VERSION 5.8 ;
BUSBITCHARS "[]" ;
DIVIDERCHAR "/" ;
UNITS
    DATABASE MICRONS 1000 ;
END UNITS

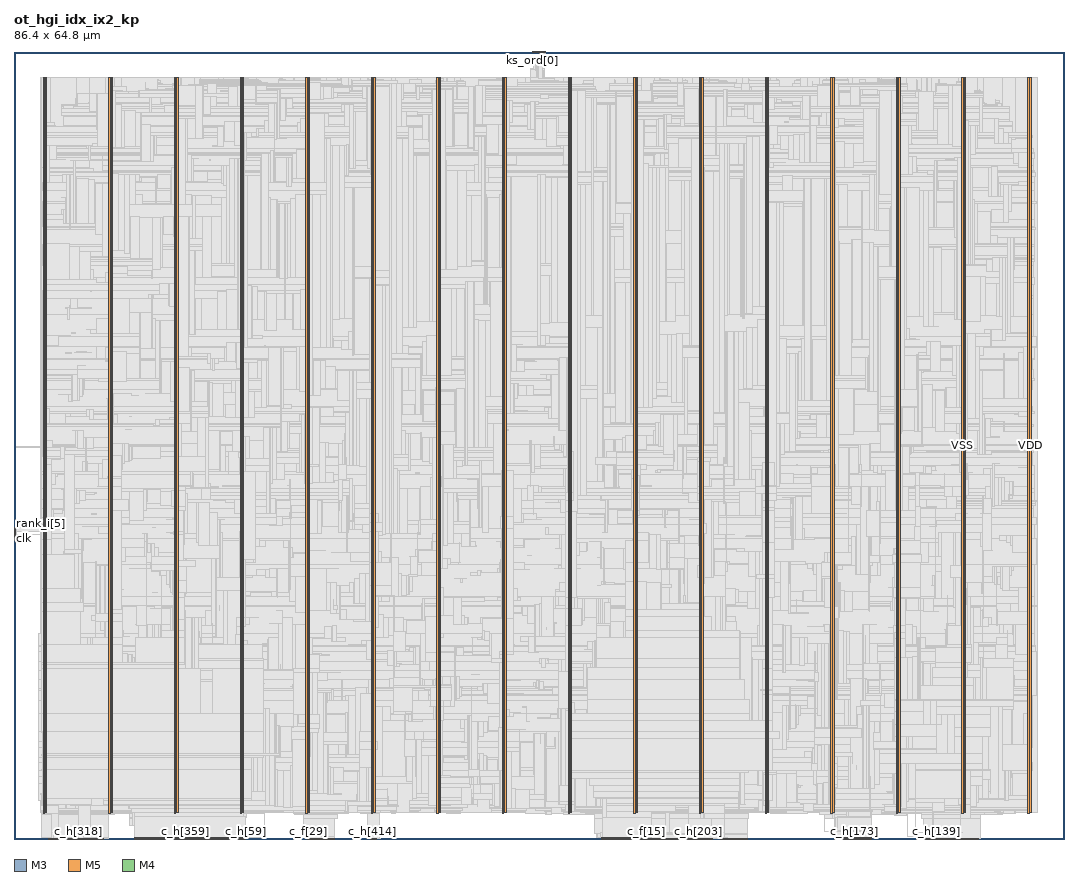
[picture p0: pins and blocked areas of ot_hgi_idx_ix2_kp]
MACRO ot_hgi_idx_ix2_kp
  FOREIGN ot_hgi_idx_ix2_kp 0 0 ;
  CLASS BLOCK ;
  SIZE 86.4 BY 64.8 ;
  PIN c_cr[0]
    DIRECTION OUTPUT ;
    USE SIGNAL ;
    PORT
      LAYER M3 ;
        RECT  50.652 0 50.67 0.037 ;
    END
  END c_cr[0]
  PIN c_cr[1]
    DIRECTION OUTPUT ;
    USE SIGNAL ;
    PORT
      LAYER M3 ;
        RECT  50.724 0 50.742 0.037 ;
    END
  END c_cr[1]
  PIN c_cr[2]
    DIRECTION OUTPUT ;
    USE SIGNAL ;
    PORT
      LAYER M3 ;
        RECT  50.796 0 50.814 0.037 ;
    END
  END c_cr[2]
  PIN c_cr[3]
    DIRECTION OUTPUT ;
    USE SIGNAL ;
    PORT
      LAYER M3 ;
        RECT  50.868 0 50.886 0.037 ;
    END
  END c_cr[3]
  PIN c_f[0]
    DIRECTION INPUT ;
    USE SIGNAL ;
    PORT
      LAYER M3 ;
        RECT  50.94 0 50.958 0.037 ;
    END
  END c_f[0]
  PIN c_f[10]
    DIRECTION INPUT ;
    USE SIGNAL ;
    PORT
      LAYER M3 ;
        RECT  51.66 0 51.678 0.037 ;
    END
  END c_f[10]
  PIN c_f[11]
    DIRECTION INPUT ;
    USE SIGNAL ;
    PORT
      LAYER M3 ;
        RECT  51.732 0 51.75 0.037 ;
    END
  END c_f[11]
  PIN c_f[12]
    DIRECTION INPUT ;
    USE SIGNAL ;
    PORT
      LAYER M3 ;
        RECT  51.804 0 51.822 0.037 ;
    END
  END c_f[12]
  PIN c_f[13]
    DIRECTION INPUT ;
    USE SIGNAL ;
    PORT
      LAYER M3 ;
        RECT  51.876 0 51.894 0.037 ;
    END
  END c_f[13]
  PIN c_f[14]
    DIRECTION INPUT ;
    USE SIGNAL ;
    PORT
      LAYER M3 ;
        RECT  51.948 0 51.966 0.037 ;
    END
  END c_f[14]
  PIN c_f[15]
    DIRECTION INPUT ;
    USE SIGNAL ;
    PORT
      LAYER M3 ;
        RECT  52.02 0 52.038 0.037 ;
    END
  END c_f[15]
  PIN c_f[16]
    DIRECTION INPUT ;
    USE SIGNAL ;
    PORT
      LAYER M3 ;
        RECT  52.092 0 52.11 0.037 ;
    END
  END c_f[16]
  PIN c_f[17]
    DIRECTION INPUT ;
    USE SIGNAL ;
    PORT
      LAYER M3 ;
        RECT  52.164 0 52.182 0.037 ;
    END
  END c_f[17]
  PIN c_f[18]
    DIRECTION INPUT ;
    USE SIGNAL ;
    PORT
      LAYER M3 ;
        RECT  52.236 0 52.254 0.037 ;
    END
  END c_f[18]
  PIN c_f[19]
    DIRECTION INPUT ;
    USE SIGNAL ;
    PORT
      LAYER M3 ;
        RECT  52.308 0 52.326 0.037 ;
    END
  END c_f[19]
  PIN c_f[1]
    DIRECTION INPUT ;
    USE SIGNAL ;
    PORT
      LAYER M3 ;
        RECT  51.012 0 51.03 0.037 ;
    END
  END c_f[1]
  PIN c_f[20]
    DIRECTION INPUT ;
    USE SIGNAL ;
    PORT
      LAYER M3 ;
        RECT  52.38 0 52.398 0.037 ;
    END
  END c_f[20]
  PIN c_f[21]
    DIRECTION INPUT ;
    USE SIGNAL ;
    PORT
      LAYER M3 ;
        RECT  52.452 0 52.47 0.037 ;
    END
  END c_f[21]
  PIN c_f[22]
    DIRECTION INPUT ;
    USE SIGNAL ;
    PORT
      LAYER M3 ;
        RECT  52.524 0 52.542 0.037 ;
    END
  END c_f[22]
  PIN c_f[23]
    DIRECTION INPUT ;
    USE SIGNAL ;
    PORT
      LAYER M3 ;
        RECT  52.596 0 52.614 0.037 ;
    END
  END c_f[23]
  PIN c_f[24]
    DIRECTION INPUT ;
    USE SIGNAL ;
    PORT
      LAYER M3 ;
        RECT  52.668 0 52.686 0.037 ;
    END
  END c_f[24]
  PIN c_f[25]
    DIRECTION INPUT ;
    USE SIGNAL ;
    PORT
      LAYER M3 ;
        RECT  52.74 0 52.758 0.037 ;
    END
  END c_f[25]
  PIN c_f[26]
    DIRECTION INPUT ;
    USE SIGNAL ;
    PORT
      LAYER M3 ;
        RECT  52.812 0 52.83 0.037 ;
    END
  END c_f[26]
  PIN c_f[27]
    DIRECTION INPUT ;
    USE SIGNAL ;
    PORT
      LAYER M3 ;
        RECT  52.884 0 52.902 0.037 ;
    END
  END c_f[27]
  PIN c_f[28]
    DIRECTION INPUT ;
    USE SIGNAL ;
    PORT
      LAYER M3 ;
        RECT  24.156 0 24.174 0.037 ;
    END
  END c_f[28]
  PIN c_f[29]
    DIRECTION INPUT ;
    USE SIGNAL ;
    PORT
      LAYER M3 ;
        RECT  24.228 0 24.246 0.037 ;
    END
  END c_f[29]
  PIN c_f[2]
    DIRECTION INPUT ;
    USE SIGNAL ;
    PORT
      LAYER M3 ;
        RECT  51.084 0 51.102 0.037 ;
    END
  END c_f[2]
  PIN c_f[30]
    DIRECTION INPUT ;
    USE SIGNAL ;
    PORT
      LAYER M3 ;
        RECT  24.3 0 24.318 0.037 ;
    END
  END c_f[30]
  PIN c_f[31]
    DIRECTION INPUT ;
    USE SIGNAL ;
    PORT
      LAYER M3 ;
        RECT  24.372 0 24.39 0.037 ;
    END
  END c_f[31]
  PIN c_f[3]
    DIRECTION INPUT ;
    USE SIGNAL ;
    PORT
      LAYER M3 ;
        RECT  51.156 0 51.174 0.037 ;
    END
  END c_f[3]
  PIN c_f[4]
    DIRECTION INPUT ;
    USE SIGNAL ;
    PORT
      LAYER M3 ;
        RECT  51.228 0 51.246 0.037 ;
    END
  END c_f[4]
  PIN c_f[5]
    DIRECTION INPUT ;
    USE SIGNAL ;
    PORT
      LAYER M3 ;
        RECT  51.3 0 51.318 0.037 ;
    END
  END c_f[5]
  PIN c_f[6]
    DIRECTION INPUT ;
    USE SIGNAL ;
    PORT
      LAYER M3 ;
        RECT  51.372 0 51.39 0.037 ;
    END
  END c_f[6]
  PIN c_f[7]
    DIRECTION INPUT ;
    USE SIGNAL ;
    PORT
      LAYER M3 ;
        RECT  51.444 0 51.462 0.037 ;
    END
  END c_f[7]
  PIN c_f[8]
    DIRECTION INPUT ;
    USE SIGNAL ;
    PORT
      LAYER M3 ;
        RECT  51.516 0 51.534 0.037 ;
    END
  END c_f[8]
  PIN c_f[9]
    DIRECTION INPUT ;
    USE SIGNAL ;
    PORT
      LAYER M3 ;
        RECT  51.588 0 51.606 0.037 ;
    END
  END c_f[9]
  PIN c_h[0]
    DIRECTION INPUT ;
    USE SIGNAL ;
    PORT
      LAYER M3 ;
        RECT  24.444 0 24.462 0.037 ;
    END
  END c_h[0]
  PIN c_h[100]
    DIRECTION INPUT ;
    USE SIGNAL ;
    PORT
      LAYER M3 ;
        RECT  53.532 0 53.55 0.037 ;
    END
  END c_h[100]
  PIN c_h[101]
    DIRECTION INPUT ;
    USE SIGNAL ;
    PORT
      LAYER M3 ;
        RECT  53.604 0 53.622 0.037 ;
    END
  END c_h[101]
  PIN c_h[102]
    DIRECTION INPUT ;
    USE SIGNAL ;
    PORT
      LAYER M3 ;
        RECT  53.676 0 53.694 0.037 ;
    END
  END c_h[102]
  PIN c_h[103]
    DIRECTION INPUT ;
    USE SIGNAL ;
    PORT
      LAYER M3 ;
        RECT  53.748 0 53.766 0.037 ;
    END
  END c_h[103]
  PIN c_h[104]
    DIRECTION INPUT ;
    USE SIGNAL ;
    PORT
      LAYER M3 ;
        RECT  53.82 0 53.838 0.037 ;
    END
  END c_h[104]
  PIN c_h[105]
    DIRECTION INPUT ;
    USE SIGNAL ;
    PORT
      LAYER M3 ;
        RECT  53.892 0 53.91 0.037 ;
    END
  END c_h[105]
  PIN c_h[106]
    DIRECTION INPUT ;
    USE SIGNAL ;
    PORT
      LAYER M3 ;
        RECT  53.964 0 53.982 0.037 ;
    END
  END c_h[106]
  PIN c_h[107]
    DIRECTION INPUT ;
    USE SIGNAL ;
    PORT
      LAYER M3 ;
        RECT  54.036 0 54.054 0.037 ;
    END
  END c_h[107]
  PIN c_h[108]
    DIRECTION INPUT ;
    USE SIGNAL ;
    PORT
      LAYER M3 ;
        RECT  54.108 0 54.126 0.037 ;
    END
  END c_h[108]
  PIN c_h[109]
    DIRECTION INPUT ;
    USE SIGNAL ;
    PORT
      LAYER M3 ;
        RECT  54.18 0 54.198 0.037 ;
    END
  END c_h[109]
  PIN c_h[10]
    DIRECTION INPUT ;
    USE SIGNAL ;
    PORT
      LAYER M3 ;
        RECT  25.164 0 25.182 0.037 ;
    END
  END c_h[10]
  PIN c_h[110]
    DIRECTION INPUT ;
    USE SIGNAL ;
    PORT
      LAYER M3 ;
        RECT  54.252 0 54.27 0.037 ;
    END
  END c_h[110]
  PIN c_h[111]
    DIRECTION INPUT ;
    USE SIGNAL ;
    PORT
      LAYER M3 ;
        RECT  54.324 0 54.342 0.037 ;
    END
  END c_h[111]
  PIN c_h[112]
    DIRECTION INPUT ;
    USE SIGNAL ;
    PORT
      LAYER M3 ;
        RECT  54.396 0 54.414 0.037 ;
    END
  END c_h[112]
  PIN c_h[113]
    DIRECTION INPUT ;
    USE SIGNAL ;
    PORT
      LAYER M3 ;
        RECT  54.468 0 54.486 0.037 ;
    END
  END c_h[113]
  PIN c_h[114]
    DIRECTION INPUT ;
    USE SIGNAL ;
    PORT
      LAYER M3 ;
        RECT  54.54 0 54.558 0.037 ;
    END
  END c_h[114]
  PIN c_h[115]
    DIRECTION INPUT ;
    USE SIGNAL ;
    PORT
      LAYER M3 ;
        RECT  54.612 0 54.63 0.037 ;
    END
  END c_h[115]
  PIN c_h[116]
    DIRECTION INPUT ;
    USE SIGNAL ;
    PORT
      LAYER M3 ;
        RECT  54.684 0 54.702 0.037 ;
    END
  END c_h[116]
  PIN c_h[117]
    DIRECTION INPUT ;
    USE SIGNAL ;
    PORT
      LAYER M3 ;
        RECT  54.756 0 54.774 0.037 ;
    END
  END c_h[117]
  PIN c_h[118]
    DIRECTION INPUT ;
    USE SIGNAL ;
    PORT
      LAYER M3 ;
        RECT  54.828 0 54.846 0.037 ;
    END
  END c_h[118]
  PIN c_h[119]
    DIRECTION INPUT ;
    USE SIGNAL ;
    PORT
      LAYER M3 ;
        RECT  54.9 0 54.918 0.037 ;
    END
  END c_h[119]
  PIN c_h[11]
    DIRECTION INPUT ;
    USE SIGNAL ;
    PORT
      LAYER M3 ;
        RECT  25.236 0 25.254 0.037 ;
    END
  END c_h[11]
  PIN c_h[120]
    DIRECTION INPUT ;
    USE SIGNAL ;
    PORT
      LAYER M3 ;
        RECT  54.972 0 54.99 0.037 ;
    END
  END c_h[120]
  PIN c_h[121]
    DIRECTION INPUT ;
    USE SIGNAL ;
    PORT
      LAYER M3 ;
        RECT  55.044 0 55.062 0.037 ;
    END
  END c_h[121]
  PIN c_h[122]
    DIRECTION INPUT ;
    USE SIGNAL ;
    PORT
      LAYER M3 ;
        RECT  55.116 0 55.134 0.037 ;
    END
  END c_h[122]
  PIN c_h[123]
    DIRECTION INPUT ;
    USE SIGNAL ;
    PORT
      LAYER M3 ;
        RECT  55.188 0 55.206 0.037 ;
    END
  END c_h[123]
  PIN c_h[124]
    DIRECTION INPUT ;
    USE SIGNAL ;
    PORT
      LAYER M3 ;
        RECT  74.844 0 74.862 0.037 ;
    END
  END c_h[124]
  PIN c_h[125]
    DIRECTION INPUT ;
    USE SIGNAL ;
    PORT
      LAYER M3 ;
        RECT  74.916 0 74.934 0.037 ;
    END
  END c_h[125]
  PIN c_h[126]
    DIRECTION INPUT ;
    USE SIGNAL ;
    PORT
      LAYER M3 ;
        RECT  74.988 0 75.006 0.037 ;
    END
  END c_h[126]
  PIN c_h[127]
    DIRECTION INPUT ;
    USE SIGNAL ;
    PORT
      LAYER M3 ;
        RECT  75.06 0 75.078 0.037 ;
    END
  END c_h[127]
  PIN c_h[128]
    DIRECTION INPUT ;
    USE SIGNAL ;
    PORT
      LAYER M3 ;
        RECT  75.132 0 75.15 0.037 ;
    END
  END c_h[128]
  PIN c_h[129]
    DIRECTION INPUT ;
    USE SIGNAL ;
    PORT
      LAYER M3 ;
        RECT  75.204 0 75.222 0.037 ;
    END
  END c_h[129]
  PIN c_h[12]
    DIRECTION INPUT ;
    USE SIGNAL ;
    PORT
      LAYER M3 ;
        RECT  25.308 0 25.326 0.037 ;
    END
  END c_h[12]
  PIN c_h[130]
    DIRECTION INPUT ;
    USE SIGNAL ;
    PORT
      LAYER M3 ;
        RECT  75.276 0 75.294 0.037 ;
    END
  END c_h[130]
  PIN c_h[131]
    DIRECTION INPUT ;
    USE SIGNAL ;
    PORT
      LAYER M3 ;
        RECT  75.348 0 75.366 0.037 ;
    END
  END c_h[131]
  PIN c_h[132]
    DIRECTION INPUT ;
    USE SIGNAL ;
    PORT
      LAYER M3 ;
        RECT  75.42 0 75.438 0.037 ;
    END
  END c_h[132]
  PIN c_h[133]
    DIRECTION INPUT ;
    USE SIGNAL ;
    PORT
      LAYER M3 ;
        RECT  75.492 0 75.51 0.037 ;
    END
  END c_h[133]
  PIN c_h[134]
    DIRECTION INPUT ;
    USE SIGNAL ;
    PORT
      LAYER M3 ;
        RECT  75.564 0 75.582 0.037 ;
    END
  END c_h[134]
  PIN c_h[135]
    DIRECTION INPUT ;
    USE SIGNAL ;
    PORT
      LAYER M3 ;
        RECT  75.636 0 75.654 0.037 ;
    END
  END c_h[135]
  PIN c_h[136]
    DIRECTION INPUT ;
    USE SIGNAL ;
    PORT
      LAYER M3 ;
        RECT  75.708 0 75.726 0.037 ;
    END
  END c_h[136]
  PIN c_h[137]
    DIRECTION INPUT ;
    USE SIGNAL ;
    PORT
      LAYER M3 ;
        RECT  75.78 0 75.798 0.037 ;
    END
  END c_h[137]
  PIN c_h[138]
    DIRECTION INPUT ;
    USE SIGNAL ;
    PORT
      LAYER M3 ;
        RECT  75.852 0 75.87 0.037 ;
    END
  END c_h[138]
  PIN c_h[139]
    DIRECTION INPUT ;
    USE SIGNAL ;
    PORT
      LAYER M3 ;
        RECT  75.924 0 75.942 0.037 ;
    END
  END c_h[139]
  PIN c_h[13]
    DIRECTION INPUT ;
    USE SIGNAL ;
    PORT
      LAYER M3 ;
        RECT  25.38 0 25.398 0.037 ;
    END
  END c_h[13]
  PIN c_h[140]
    DIRECTION INPUT ;
    USE SIGNAL ;
    PORT
      LAYER M3 ;
        RECT  75.996 0 76.014 0.037 ;
    END
  END c_h[140]
  PIN c_h[141]
    DIRECTION INPUT ;
    USE SIGNAL ;
    PORT
      LAYER M3 ;
        RECT  76.068 0 76.086 0.037 ;
    END
  END c_h[141]
  PIN c_h[142]
    DIRECTION INPUT ;
    USE SIGNAL ;
    PORT
      LAYER M3 ;
        RECT  76.14 0 76.158 0.037 ;
    END
  END c_h[142]
  PIN c_h[143]
    DIRECTION INPUT ;
    USE SIGNAL ;
    PORT
      LAYER M3 ;
        RECT  76.212 0 76.23 0.037 ;
    END
  END c_h[143]
  PIN c_h[144]
    DIRECTION INPUT ;
    USE SIGNAL ;
    PORT
      LAYER M3 ;
        RECT  76.284 0 76.302 0.037 ;
    END
  END c_h[144]
  PIN c_h[145]
    DIRECTION INPUT ;
    USE SIGNAL ;
    PORT
      LAYER M3 ;
        RECT  76.356 0 76.374 0.037 ;
    END
  END c_h[145]
  PIN c_h[146]
    DIRECTION INPUT ;
    USE SIGNAL ;
    PORT
      LAYER M3 ;
        RECT  76.428 0 76.446 0.037 ;
    END
  END c_h[146]
  PIN c_h[147]
    DIRECTION INPUT ;
    USE SIGNAL ;
    PORT
      LAYER M3 ;
        RECT  76.5 0 76.518 0.037 ;
    END
  END c_h[147]
  PIN c_h[148]
    DIRECTION INPUT ;
    USE SIGNAL ;
    PORT
      LAYER M3 ;
        RECT  76.572 0 76.59 0.037 ;
    END
  END c_h[148]
  PIN c_h[149]
    DIRECTION INPUT ;
    USE SIGNAL ;
    PORT
      LAYER M3 ;
        RECT  76.644 0 76.662 0.037 ;
    END
  END c_h[149]
  PIN c_h[14]
    DIRECTION INPUT ;
    USE SIGNAL ;
    PORT
      LAYER M3 ;
        RECT  25.452 0 25.47 0.037 ;
    END
  END c_h[14]
  PIN c_h[150]
    DIRECTION INPUT ;
    USE SIGNAL ;
    PORT
      LAYER M3 ;
        RECT  76.716 0 76.734 0.037 ;
    END
  END c_h[150]
  PIN c_h[151]
    DIRECTION INPUT ;
    USE SIGNAL ;
    PORT
      LAYER M3 ;
        RECT  76.788 0 76.806 0.037 ;
    END
  END c_h[151]
  PIN c_h[152]
    DIRECTION INPUT ;
    USE SIGNAL ;
    PORT
      LAYER M3 ;
        RECT  76.86 0 76.878 0.037 ;
    END
  END c_h[152]
  PIN c_h[153]
    DIRECTION INPUT ;
    USE SIGNAL ;
    PORT
      LAYER M3 ;
        RECT  76.932 0 76.95 0.037 ;
    END
  END c_h[153]
  PIN c_h[154]
    DIRECTION INPUT ;
    USE SIGNAL ;
    PORT
      LAYER M3 ;
        RECT  77.004 0 77.022 0.037 ;
    END
  END c_h[154]
  PIN c_h[155]
    DIRECTION INPUT ;
    USE SIGNAL ;
    PORT
      LAYER M3 ;
        RECT  77.076 0 77.094 0.037 ;
    END
  END c_h[155]
  PIN c_h[156]
    DIRECTION INPUT ;
    USE SIGNAL ;
    PORT
      LAYER M5 ;
        RECT  67.536 0 67.56 0.084 ;
    END
  END c_h[156]
  PIN c_h[157]
    DIRECTION INPUT ;
    USE SIGNAL ;
    PORT
      LAYER M5 ;
        RECT  67.632 0 67.656 0.084 ;
    END
  END c_h[157]
  PIN c_h[158]
    DIRECTION INPUT ;
    USE SIGNAL ;
    PORT
      LAYER M5 ;
        RECT  67.728 0 67.752 0.084 ;
    END
  END c_h[158]
  PIN c_h[159]
    DIRECTION INPUT ;
    USE SIGNAL ;
    PORT
      LAYER M5 ;
        RECT  67.824 0 67.848 0.084 ;
    END
  END c_h[159]
  PIN c_h[15]
    DIRECTION INPUT ;
    USE SIGNAL ;
    PORT
      LAYER M3 ;
        RECT  25.524 0 25.542 0.037 ;
    END
  END c_h[15]
  PIN c_h[160]
    DIRECTION INPUT ;
    USE SIGNAL ;
    PORT
      LAYER M5 ;
        RECT  67.92 0 67.944 0.084 ;
    END
  END c_h[160]
  PIN c_h[161]
    DIRECTION INPUT ;
    USE SIGNAL ;
    PORT
      LAYER M5 ;
        RECT  68.016 0 68.04 0.084 ;
    END
  END c_h[161]
  PIN c_h[162]
    DIRECTION INPUT ;
    USE SIGNAL ;
    PORT
      LAYER M5 ;
        RECT  68.112 0 68.136 0.084 ;
    END
  END c_h[162]
  PIN c_h[163]
    DIRECTION INPUT ;
    USE SIGNAL ;
    PORT
      LAYER M5 ;
        RECT  68.208 0 68.232 0.084 ;
    END
  END c_h[163]
  PIN c_h[164]
    DIRECTION INPUT ;
    USE SIGNAL ;
    PORT
      LAYER M5 ;
        RECT  68.304 0 68.328 0.084 ;
    END
  END c_h[164]
  PIN c_h[165]
    DIRECTION INPUT ;
    USE SIGNAL ;
    PORT
      LAYER M5 ;
        RECT  68.4 0 68.424 0.084 ;
    END
  END c_h[165]
  PIN c_h[166]
    DIRECTION INPUT ;
    USE SIGNAL ;
    PORT
      LAYER M5 ;
        RECT  68.496 0 68.52 0.084 ;
    END
  END c_h[166]
  PIN c_h[167]
    DIRECTION INPUT ;
    USE SIGNAL ;
    PORT
      LAYER M5 ;
        RECT  68.592 0 68.616 0.084 ;
    END
  END c_h[167]
  PIN c_h[168]
    DIRECTION INPUT ;
    USE SIGNAL ;
    PORT
      LAYER M5 ;
        RECT  68.688 0 68.712 0.084 ;
    END
  END c_h[168]
  PIN c_h[169]
    DIRECTION INPUT ;
    USE SIGNAL ;
    PORT
      LAYER M5 ;
        RECT  68.784 0 68.808 0.084 ;
    END
  END c_h[169]
  PIN c_h[16]
    DIRECTION INPUT ;
    USE SIGNAL ;
    PORT
      LAYER M3 ;
        RECT  25.596 0 25.614 0.037 ;
    END
  END c_h[16]
  PIN c_h[170]
    DIRECTION INPUT ;
    USE SIGNAL ;
    PORT
      LAYER M5 ;
        RECT  68.88 0 68.904 0.084 ;
    END
  END c_h[170]
  PIN c_h[171]
    DIRECTION INPUT ;
    USE SIGNAL ;
    PORT
      LAYER M5 ;
        RECT  68.976 0 69 0.084 ;
    END
  END c_h[171]
  PIN c_h[172]
    DIRECTION INPUT ;
    USE SIGNAL ;
    PORT
      LAYER M5 ;
        RECT  69.072 0 69.096 0.084 ;
    END
  END c_h[172]
  PIN c_h[173]
    DIRECTION INPUT ;
    USE SIGNAL ;
    PORT
      LAYER M5 ;
        RECT  69.168 0 69.192 0.084 ;
    END
  END c_h[173]
  PIN c_h[174]
    DIRECTION INPUT ;
    USE SIGNAL ;
    PORT
      LAYER M5 ;
        RECT  69.264 0 69.288 0.084 ;
    END
  END c_h[174]
  PIN c_h[175]
    DIRECTION INPUT ;
    USE SIGNAL ;
    PORT
      LAYER M5 ;
        RECT  69.36 0 69.384 0.084 ;
    END
  END c_h[175]
  PIN c_h[176]
    DIRECTION INPUT ;
    USE SIGNAL ;
    PORT
      LAYER M5 ;
        RECT  69.456 0 69.48 0.084 ;
    END
  END c_h[176]
  PIN c_h[177]
    DIRECTION INPUT ;
    USE SIGNAL ;
    PORT
      LAYER M5 ;
        RECT  69.552 0 69.576 0.084 ;
    END
  END c_h[177]
  PIN c_h[178]
    DIRECTION INPUT ;
    USE SIGNAL ;
    PORT
      LAYER M5 ;
        RECT  69.648 0 69.672 0.084 ;
    END
  END c_h[178]
  PIN c_h[179]
    DIRECTION INPUT ;
    USE SIGNAL ;
    PORT
      LAYER M5 ;
        RECT  69.744 0 69.768 0.084 ;
    END
  END c_h[179]
  PIN c_h[17]
    DIRECTION INPUT ;
    USE SIGNAL ;
    PORT
      LAYER M3 ;
        RECT  25.668 0 25.686 0.037 ;
    END
  END c_h[17]
  PIN c_h[180]
    DIRECTION INPUT ;
    USE SIGNAL ;
    PORT
      LAYER M5 ;
        RECT  69.84 0 69.864 0.084 ;
    END
  END c_h[180]
  PIN c_h[181]
    DIRECTION INPUT ;
    USE SIGNAL ;
    PORT
      LAYER M5 ;
        RECT  69.936 0 69.96 0.084 ;
    END
  END c_h[181]
  PIN c_h[182]
    DIRECTION INPUT ;
    USE SIGNAL ;
    PORT
      LAYER M5 ;
        RECT  70.032 0 70.056 0.084 ;
    END
  END c_h[182]
  PIN c_h[183]
    DIRECTION INPUT ;
    USE SIGNAL ;
    PORT
      LAYER M5 ;
        RECT  70.128 0 70.152 0.084 ;
    END
  END c_h[183]
  PIN c_h[184]
    DIRECTION INPUT ;
    USE SIGNAL ;
    PORT
      LAYER M5 ;
        RECT  70.224 0 70.248 0.084 ;
    END
  END c_h[184]
  PIN c_h[185]
    DIRECTION INPUT ;
    USE SIGNAL ;
    PORT
      LAYER M5 ;
        RECT  70.32 0 70.344 0.084 ;
    END
  END c_h[185]
  PIN c_h[186]
    DIRECTION INPUT ;
    USE SIGNAL ;
    PORT
      LAYER M5 ;
        RECT  70.416 0 70.44 0.084 ;
    END
  END c_h[186]
  PIN c_h[187]
    DIRECTION INPUT ;
    USE SIGNAL ;
    PORT
      LAYER M5 ;
        RECT  70.512 0 70.536 0.084 ;
    END
  END c_h[187]
  PIN c_h[188]
    DIRECTION INPUT ;
    USE SIGNAL ;
    PORT
      LAYER M3 ;
        RECT  55.26 0 55.278 0.037 ;
    END
  END c_h[188]
  PIN c_h[189]
    DIRECTION INPUT ;
    USE SIGNAL ;
    PORT
      LAYER M3 ;
        RECT  55.332 0 55.35 0.037 ;
    END
  END c_h[189]
  PIN c_h[18]
    DIRECTION INPUT ;
    USE SIGNAL ;
    PORT
      LAYER M3 ;
        RECT  25.74 0 25.758 0.037 ;
    END
  END c_h[18]
  PIN c_h[190]
    DIRECTION INPUT ;
    USE SIGNAL ;
    PORT
      LAYER M3 ;
        RECT  55.404 0 55.422 0.037 ;
    END
  END c_h[190]
  PIN c_h[191]
    DIRECTION INPUT ;
    USE SIGNAL ;
    PORT
      LAYER M3 ;
        RECT  55.476 0 55.494 0.037 ;
    END
  END c_h[191]
  PIN c_h[192]
    DIRECTION INPUT ;
    USE SIGNAL ;
    PORT
      LAYER M3 ;
        RECT  55.548 0 55.566 0.037 ;
    END
  END c_h[192]
  PIN c_h[193]
    DIRECTION INPUT ;
    USE SIGNAL ;
    PORT
      LAYER M3 ;
        RECT  55.62 0 55.638 0.037 ;
    END
  END c_h[193]
  PIN c_h[194]
    DIRECTION INPUT ;
    USE SIGNAL ;
    PORT
      LAYER M3 ;
        RECT  55.692 0 55.71 0.037 ;
    END
  END c_h[194]
  PIN c_h[195]
    DIRECTION INPUT ;
    USE SIGNAL ;
    PORT
      LAYER M3 ;
        RECT  55.764 0 55.782 0.037 ;
    END
  END c_h[195]
  PIN c_h[196]
    DIRECTION INPUT ;
    USE SIGNAL ;
    PORT
      LAYER M3 ;
        RECT  55.836 0 55.854 0.037 ;
    END
  END c_h[196]
  PIN c_h[197]
    DIRECTION INPUT ;
    USE SIGNAL ;
    PORT
      LAYER M3 ;
        RECT  55.908 0 55.926 0.037 ;
    END
  END c_h[197]
  PIN c_h[198]
    DIRECTION INPUT ;
    USE SIGNAL ;
    PORT
      LAYER M3 ;
        RECT  55.98 0 55.998 0.037 ;
    END
  END c_h[198]
  PIN c_h[199]
    DIRECTION INPUT ;
    USE SIGNAL ;
    PORT
      LAYER M3 ;
        RECT  56.052 0 56.07 0.037 ;
    END
  END c_h[199]
  PIN c_h[19]
    DIRECTION INPUT ;
    USE SIGNAL ;
    PORT
      LAYER M3 ;
        RECT  25.812 0 25.83 0.037 ;
    END
  END c_h[19]
  PIN c_h[1]
    DIRECTION INPUT ;
    USE SIGNAL ;
    PORT
      LAYER M3 ;
        RECT  24.516 0 24.534 0.037 ;
    END
  END c_h[1]
  PIN c_h[200]
    DIRECTION INPUT ;
    USE SIGNAL ;
    PORT
      LAYER M3 ;
        RECT  56.124 0 56.142 0.037 ;
    END
  END c_h[200]
  PIN c_h[201]
    DIRECTION INPUT ;
    USE SIGNAL ;
    PORT
      LAYER M3 ;
        RECT  56.196 0 56.214 0.037 ;
    END
  END c_h[201]
  PIN c_h[202]
    DIRECTION INPUT ;
    USE SIGNAL ;
    PORT
      LAYER M3 ;
        RECT  56.268 0 56.286 0.037 ;
    END
  END c_h[202]
  PIN c_h[203]
    DIRECTION INPUT ;
    USE SIGNAL ;
    PORT
      LAYER M3 ;
        RECT  56.34 0 56.358 0.037 ;
    END
  END c_h[203]
  PIN c_h[204]
    DIRECTION INPUT ;
    USE SIGNAL ;
    PORT
      LAYER M3 ;
        RECT  56.412 0 56.43 0.037 ;
    END
  END c_h[204]
  PIN c_h[205]
    DIRECTION INPUT ;
    USE SIGNAL ;
    PORT
      LAYER M3 ;
        RECT  56.484 0 56.502 0.037 ;
    END
  END c_h[205]
  PIN c_h[206]
    DIRECTION INPUT ;
    USE SIGNAL ;
    PORT
      LAYER M3 ;
        RECT  56.556 0 56.574 0.037 ;
    END
  END c_h[206]
  PIN c_h[207]
    DIRECTION INPUT ;
    USE SIGNAL ;
    PORT
      LAYER M3 ;
        RECT  56.628 0 56.646 0.037 ;
    END
  END c_h[207]
  PIN c_h[208]
    DIRECTION INPUT ;
    USE SIGNAL ;
    PORT
      LAYER M3 ;
        RECT  56.7 0 56.718 0.037 ;
    END
  END c_h[208]
  PIN c_h[209]
    DIRECTION INPUT ;
    USE SIGNAL ;
    PORT
      LAYER M3 ;
        RECT  56.772 0 56.79 0.037 ;
    END
  END c_h[209]
  PIN c_h[20]
    DIRECTION INPUT ;
    USE SIGNAL ;
    PORT
      LAYER M3 ;
        RECT  25.884 0 25.902 0.037 ;
    END
  END c_h[20]
  PIN c_h[210]
    DIRECTION INPUT ;
    USE SIGNAL ;
    PORT
      LAYER M3 ;
        RECT  56.844 0 56.862 0.037 ;
    END
  END c_h[210]
  PIN c_h[211]
    DIRECTION INPUT ;
    USE SIGNAL ;
    PORT
      LAYER M3 ;
        RECT  56.916 0 56.934 0.037 ;
    END
  END c_h[211]
  PIN c_h[212]
    DIRECTION INPUT ;
    USE SIGNAL ;
    PORT
      LAYER M3 ;
        RECT  56.988 0 57.006 0.037 ;
    END
  END c_h[212]
  PIN c_h[213]
    DIRECTION INPUT ;
    USE SIGNAL ;
    PORT
      LAYER M3 ;
        RECT  57.06 0 57.078 0.037 ;
    END
  END c_h[213]
  PIN c_h[214]
    DIRECTION INPUT ;
    USE SIGNAL ;
    PORT
      LAYER M3 ;
        RECT  57.132 0 57.15 0.037 ;
    END
  END c_h[214]
  PIN c_h[215]
    DIRECTION INPUT ;
    USE SIGNAL ;
    PORT
      LAYER M3 ;
        RECT  57.204 0 57.222 0.037 ;
    END
  END c_h[215]
  PIN c_h[216]
    DIRECTION INPUT ;
    USE SIGNAL ;
    PORT
      LAYER M3 ;
        RECT  57.276 0 57.294 0.037 ;
    END
  END c_h[216]
  PIN c_h[217]
    DIRECTION INPUT ;
    USE SIGNAL ;
    PORT
      LAYER M3 ;
        RECT  57.348 0 57.366 0.037 ;
    END
  END c_h[217]
  PIN c_h[218]
    DIRECTION INPUT ;
    USE SIGNAL ;
    PORT
      LAYER M3 ;
        RECT  57.42 0 57.438 0.037 ;
    END
  END c_h[218]
  PIN c_h[219]
    DIRECTION INPUT ;
    USE SIGNAL ;
    PORT
      LAYER M3 ;
        RECT  57.492 0 57.51 0.037 ;
    END
  END c_h[219]
  PIN c_h[21]
    DIRECTION INPUT ;
    USE SIGNAL ;
    PORT
      LAYER M3 ;
        RECT  25.956 0 25.974 0.037 ;
    END
  END c_h[21]
  PIN c_h[220]
    DIRECTION INPUT ;
    USE SIGNAL ;
    PORT
      LAYER M5 ;
        RECT  48.336 0 48.36 0.084 ;
    END
  END c_h[220]
  PIN c_h[221]
    DIRECTION INPUT ;
    USE SIGNAL ;
    PORT
      LAYER M5 ;
        RECT  48.432 0 48.456 0.084 ;
    END
  END c_h[221]
  PIN c_h[222]
    DIRECTION INPUT ;
    USE SIGNAL ;
    PORT
      LAYER M5 ;
        RECT  48.528 0 48.552 0.084 ;
    END
  END c_h[222]
  PIN c_h[223]
    DIRECTION INPUT ;
    USE SIGNAL ;
    PORT
      LAYER M5 ;
        RECT  48.624 0 48.648 0.084 ;
    END
  END c_h[223]
  PIN c_h[224]
    DIRECTION INPUT ;
    USE SIGNAL ;
    PORT
      LAYER M5 ;
        RECT  48.72 0 48.744 0.084 ;
    END
  END c_h[224]
  PIN c_h[225]
    DIRECTION INPUT ;
    USE SIGNAL ;
    PORT
      LAYER M5 ;
        RECT  48.816 0 48.84 0.084 ;
    END
  END c_h[225]
  PIN c_h[226]
    DIRECTION INPUT ;
    USE SIGNAL ;
    PORT
      LAYER M5 ;
        RECT  48.912 0 48.936 0.084 ;
    END
  END c_h[226]
  PIN c_h[227]
    DIRECTION INPUT ;
    USE SIGNAL ;
    PORT
      LAYER M5 ;
        RECT  49.008 0 49.032 0.084 ;
    END
  END c_h[227]
  PIN c_h[228]
    DIRECTION INPUT ;
    USE SIGNAL ;
    PORT
      LAYER M5 ;
        RECT  49.104 0 49.128 0.084 ;
    END
  END c_h[228]
  PIN c_h[229]
    DIRECTION INPUT ;
    USE SIGNAL ;
    PORT
      LAYER M5 ;
        RECT  49.2 0 49.224 0.084 ;
    END
  END c_h[229]
  PIN c_h[22]
    DIRECTION INPUT ;
    USE SIGNAL ;
    PORT
      LAYER M3 ;
        RECT  26.028 0 26.046 0.037 ;
    END
  END c_h[22]
  PIN c_h[230]
    DIRECTION INPUT ;
    USE SIGNAL ;
    PORT
      LAYER M5 ;
        RECT  49.296 0 49.32 0.084 ;
    END
  END c_h[230]
  PIN c_h[231]
    DIRECTION INPUT ;
    USE SIGNAL ;
    PORT
      LAYER M5 ;
        RECT  49.392 0 49.416 0.084 ;
    END
  END c_h[231]
  PIN c_h[232]
    DIRECTION INPUT ;
    USE SIGNAL ;
    PORT
      LAYER M5 ;
        RECT  49.488 0 49.512 0.084 ;
    END
  END c_h[232]
  PIN c_h[233]
    DIRECTION INPUT ;
    USE SIGNAL ;
    PORT
      LAYER M5 ;
        RECT  49.584 0 49.608 0.084 ;
    END
  END c_h[233]
  PIN c_h[234]
    DIRECTION INPUT ;
    USE SIGNAL ;
    PORT
      LAYER M5 ;
        RECT  49.68 0 49.704 0.084 ;
    END
  END c_h[234]
  PIN c_h[235]
    DIRECTION INPUT ;
    USE SIGNAL ;
    PORT
      LAYER M5 ;
        RECT  49.776 0 49.8 0.084 ;
    END
  END c_h[235]
  PIN c_h[236]
    DIRECTION INPUT ;
    USE SIGNAL ;
    PORT
      LAYER M5 ;
        RECT  49.872 0 49.896 0.084 ;
    END
  END c_h[236]
  PIN c_h[237]
    DIRECTION INPUT ;
    USE SIGNAL ;
    PORT
      LAYER M5 ;
        RECT  49.968 0 49.992 0.084 ;
    END
  END c_h[237]
  PIN c_h[238]
    DIRECTION INPUT ;
    USE SIGNAL ;
    PORT
      LAYER M5 ;
        RECT  50.064 0 50.088 0.084 ;
    END
  END c_h[238]
  PIN c_h[239]
    DIRECTION INPUT ;
    USE SIGNAL ;
    PORT
      LAYER M5 ;
        RECT  50.16 0 50.184 0.084 ;
    END
  END c_h[239]
  PIN c_h[23]
    DIRECTION INPUT ;
    USE SIGNAL ;
    PORT
      LAYER M3 ;
        RECT  26.1 0 26.118 0.037 ;
    END
  END c_h[23]
  PIN c_h[240]
    DIRECTION INPUT ;
    USE SIGNAL ;
    PORT
      LAYER M5 ;
        RECT  50.256 0 50.28 0.084 ;
    END
  END c_h[240]
  PIN c_h[241]
    DIRECTION INPUT ;
    USE SIGNAL ;
    PORT
      LAYER M5 ;
        RECT  50.352 0 50.376 0.084 ;
    END
  END c_h[241]
  PIN c_h[242]
    DIRECTION INPUT ;
    USE SIGNAL ;
    PORT
      LAYER M5 ;
        RECT  50.448 0 50.472 0.084 ;
    END
  END c_h[242]
  PIN c_h[243]
    DIRECTION INPUT ;
    USE SIGNAL ;
    PORT
      LAYER M5 ;
        RECT  50.544 0 50.568 0.084 ;
    END
  END c_h[243]
  PIN c_h[244]
    DIRECTION INPUT ;
    USE SIGNAL ;
    PORT
      LAYER M5 ;
        RECT  50.64 0 50.664 0.084 ;
    END
  END c_h[244]
  PIN c_h[245]
    DIRECTION INPUT ;
    USE SIGNAL ;
    PORT
      LAYER M5 ;
        RECT  50.736 0 50.76 0.084 ;
    END
  END c_h[245]
  PIN c_h[246]
    DIRECTION INPUT ;
    USE SIGNAL ;
    PORT
      LAYER M5 ;
        RECT  50.832 0 50.856 0.084 ;
    END
  END c_h[246]
  PIN c_h[247]
    DIRECTION INPUT ;
    USE SIGNAL ;
    PORT
      LAYER M5 ;
        RECT  50.928 0 50.952 0.084 ;
    END
  END c_h[247]
  PIN c_h[248]
    DIRECTION INPUT ;
    USE SIGNAL ;
    PORT
      LAYER M5 ;
        RECT  51.024 0 51.048 0.084 ;
    END
  END c_h[248]
  PIN c_h[249]
    DIRECTION INPUT ;
    USE SIGNAL ;
    PORT
      LAYER M5 ;
        RECT  51.12 0 51.144 0.084 ;
    END
  END c_h[249]
  PIN c_h[24]
    DIRECTION INPUT ;
    USE SIGNAL ;
    PORT
      LAYER M3 ;
        RECT  26.172 0 26.19 0.037 ;
    END
  END c_h[24]
  PIN c_h[250]
    DIRECTION INPUT ;
    USE SIGNAL ;
    PORT
      LAYER M5 ;
        RECT  51.216 0 51.24 0.084 ;
    END
  END c_h[250]
  PIN c_h[251]
    DIRECTION INPUT ;
    USE SIGNAL ;
    PORT
      LAYER M5 ;
        RECT  51.312 0 51.336 0.084 ;
    END
  END c_h[251]
  PIN c_h[252]
    DIRECTION INPUT ;
    USE SIGNAL ;
    PORT
      LAYER M3 ;
        RECT  58.14 0 58.158 0.037 ;
    END
  END c_h[252]
  PIN c_h[253]
    DIRECTION INPUT ;
    USE SIGNAL ;
    PORT
      LAYER M3 ;
        RECT  58.212 0 58.23 0.037 ;
    END
  END c_h[253]
  PIN c_h[254]
    DIRECTION INPUT ;
    USE SIGNAL ;
    PORT
      LAYER M3 ;
        RECT  58.284 0 58.302 0.037 ;
    END
  END c_h[254]
  PIN c_h[255]
    DIRECTION INPUT ;
    USE SIGNAL ;
    PORT
      LAYER M3 ;
        RECT  58.356 0 58.374 0.037 ;
    END
  END c_h[255]
  PIN c_h[256]
    DIRECTION INPUT ;
    USE SIGNAL ;
    PORT
      LAYER M3 ;
        RECT  58.428 0 58.446 0.037 ;
    END
  END c_h[256]
  PIN c_h[257]
    DIRECTION INPUT ;
    USE SIGNAL ;
    PORT
      LAYER M3 ;
        RECT  58.5 0 58.518 0.037 ;
    END
  END c_h[257]
  PIN c_h[258]
    DIRECTION INPUT ;
    USE SIGNAL ;
    PORT
      LAYER M3 ;
        RECT  58.572 0 58.59 0.037 ;
    END
  END c_h[258]
  PIN c_h[259]
    DIRECTION INPUT ;
    USE SIGNAL ;
    PORT
      LAYER M3 ;
        RECT  58.644 0 58.662 0.037 ;
    END
  END c_h[259]
  PIN c_h[25]
    DIRECTION INPUT ;
    USE SIGNAL ;
    PORT
      LAYER M3 ;
        RECT  26.244 0 26.262 0.037 ;
    END
  END c_h[25]
  PIN c_h[260]
    DIRECTION INPUT ;
    USE SIGNAL ;
    PORT
      LAYER M3 ;
        RECT  58.716 0 58.734 0.037 ;
    END
  END c_h[260]
  PIN c_h[261]
    DIRECTION INPUT ;
    USE SIGNAL ;
    PORT
      LAYER M3 ;
        RECT  58.788 0 58.806 0.037 ;
    END
  END c_h[261]
  PIN c_h[262]
    DIRECTION INPUT ;
    USE SIGNAL ;
    PORT
      LAYER M3 ;
        RECT  58.86 0 58.878 0.037 ;
    END
  END c_h[262]
  PIN c_h[263]
    DIRECTION INPUT ;
    USE SIGNAL ;
    PORT
      LAYER M3 ;
        RECT  58.932 0 58.95 0.037 ;
    END
  END c_h[263]
  PIN c_h[264]
    DIRECTION INPUT ;
    USE SIGNAL ;
    PORT
      LAYER M3 ;
        RECT  59.004 0 59.022 0.037 ;
    END
  END c_h[264]
  PIN c_h[265]
    DIRECTION INPUT ;
    USE SIGNAL ;
    PORT
      LAYER M3 ;
        RECT  59.076 0 59.094 0.037 ;
    END
  END c_h[265]
  PIN c_h[266]
    DIRECTION INPUT ;
    USE SIGNAL ;
    PORT
      LAYER M3 ;
        RECT  59.148 0 59.166 0.037 ;
    END
  END c_h[266]
  PIN c_h[267]
    DIRECTION INPUT ;
    USE SIGNAL ;
    PORT
      LAYER M3 ;
        RECT  59.22 0 59.238 0.037 ;
    END
  END c_h[267]
  PIN c_h[268]
    DIRECTION INPUT ;
    USE SIGNAL ;
    PORT
      LAYER M3 ;
        RECT  59.292 0 59.31 0.037 ;
    END
  END c_h[268]
  PIN c_h[269]
    DIRECTION INPUT ;
    USE SIGNAL ;
    PORT
      LAYER M3 ;
        RECT  59.364 0 59.382 0.037 ;
    END
  END c_h[269]
  PIN c_h[26]
    DIRECTION INPUT ;
    USE SIGNAL ;
    PORT
      LAYER M3 ;
        RECT  26.316 0 26.334 0.037 ;
    END
  END c_h[26]
  PIN c_h[270]
    DIRECTION INPUT ;
    USE SIGNAL ;
    PORT
      LAYER M3 ;
        RECT  59.436 0 59.454 0.037 ;
    END
  END c_h[270]
  PIN c_h[271]
    DIRECTION INPUT ;
    USE SIGNAL ;
    PORT
      LAYER M3 ;
        RECT  59.508 0 59.526 0.037 ;
    END
  END c_h[271]
  PIN c_h[272]
    DIRECTION INPUT ;
    USE SIGNAL ;
    PORT
      LAYER M3 ;
        RECT  59.58 0 59.598 0.037 ;
    END
  END c_h[272]
  PIN c_h[273]
    DIRECTION INPUT ;
    USE SIGNAL ;
    PORT
      LAYER M3 ;
        RECT  59.652 0 59.67 0.037 ;
    END
  END c_h[273]
  PIN c_h[274]
    DIRECTION INPUT ;
    USE SIGNAL ;
    PORT
      LAYER M3 ;
        RECT  59.724 0 59.742 0.037 ;
    END
  END c_h[274]
  PIN c_h[275]
    DIRECTION INPUT ;
    USE SIGNAL ;
    PORT
      LAYER M3 ;
        RECT  59.796 0 59.814 0.037 ;
    END
  END c_h[275]
  PIN c_h[276]
    DIRECTION INPUT ;
    USE SIGNAL ;
    PORT
      LAYER M3 ;
        RECT  59.868 0 59.886 0.037 ;
    END
  END c_h[276]
  PIN c_h[277]
    DIRECTION INPUT ;
    USE SIGNAL ;
    PORT
      LAYER M3 ;
        RECT  59.94 0 59.958 0.037 ;
    END
  END c_h[277]
  PIN c_h[278]
    DIRECTION INPUT ;
    USE SIGNAL ;
    PORT
      LAYER M3 ;
        RECT  60.012 0 60.03 0.037 ;
    END
  END c_h[278]
  PIN c_h[279]
    DIRECTION INPUT ;
    USE SIGNAL ;
    PORT
      LAYER M3 ;
        RECT  60.084 0 60.102 0.037 ;
    END
  END c_h[279]
  PIN c_h[27]
    DIRECTION INPUT ;
    USE SIGNAL ;
    PORT
      LAYER M3 ;
        RECT  26.388 0 26.406 0.037 ;
    END
  END c_h[27]
  PIN c_h[280]
    DIRECTION INPUT ;
    USE SIGNAL ;
    PORT
      LAYER M3 ;
        RECT  60.156 0 60.174 0.037 ;
    END
  END c_h[280]
  PIN c_h[281]
    DIRECTION INPUT ;
    USE SIGNAL ;
    PORT
      LAYER M3 ;
        RECT  60.228 0 60.246 0.037 ;
    END
  END c_h[281]
  PIN c_h[282]
    DIRECTION INPUT ;
    USE SIGNAL ;
    PORT
      LAYER M3 ;
        RECT  60.3 0 60.318 0.037 ;
    END
  END c_h[282]
  PIN c_h[283]
    DIRECTION INPUT ;
    USE SIGNAL ;
    PORT
      LAYER M3 ;
        RECT  60.372 0 60.39 0.037 ;
    END
  END c_h[283]
  PIN c_h[284]
    DIRECTION INPUT ;
    USE SIGNAL ;
    PORT
      LAYER M3 ;
        RECT  77.148 0 77.166 0.037 ;
    END
  END c_h[284]
  PIN c_h[285]
    DIRECTION INPUT ;
    USE SIGNAL ;
    PORT
      LAYER M3 ;
        RECT  77.22 0 77.238 0.037 ;
    END
  END c_h[285]
  PIN c_h[286]
    DIRECTION INPUT ;
    USE SIGNAL ;
    PORT
      LAYER M3 ;
        RECT  77.292 0 77.31 0.037 ;
    END
  END c_h[286]
  PIN c_h[287]
    DIRECTION INPUT ;
    USE SIGNAL ;
    PORT
      LAYER M3 ;
        RECT  77.364 0 77.382 0.037 ;
    END
  END c_h[287]
  PIN c_h[288]
    DIRECTION INPUT ;
    USE SIGNAL ;
    PORT
      LAYER M3 ;
        RECT  77.436 0 77.454 0.037 ;
    END
  END c_h[288]
  PIN c_h[289]
    DIRECTION INPUT ;
    USE SIGNAL ;
    PORT
      LAYER M3 ;
        RECT  77.508 0 77.526 0.037 ;
    END
  END c_h[289]
  PIN c_h[28]
    DIRECTION INPUT ;
    USE SIGNAL ;
    PORT
      LAYER M5 ;
        RECT  16.08 0 16.104 0.084 ;
    END
  END c_h[28]
  PIN c_h[290]
    DIRECTION INPUT ;
    USE SIGNAL ;
    PORT
      LAYER M3 ;
        RECT  77.58 0 77.598 0.037 ;
    END
  END c_h[290]
  PIN c_h[291]
    DIRECTION INPUT ;
    USE SIGNAL ;
    PORT
      LAYER M3 ;
        RECT  77.652 0 77.67 0.037 ;
    END
  END c_h[291]
  PIN c_h[292]
    DIRECTION INPUT ;
    USE SIGNAL ;
    PORT
      LAYER M3 ;
        RECT  77.724 0 77.742 0.037 ;
    END
  END c_h[292]
  PIN c_h[293]
    DIRECTION INPUT ;
    USE SIGNAL ;
    PORT
      LAYER M3 ;
        RECT  77.796 0 77.814 0.037 ;
    END
  END c_h[293]
  PIN c_h[294]
    DIRECTION INPUT ;
    USE SIGNAL ;
    PORT
      LAYER M3 ;
        RECT  77.868 0 77.886 0.037 ;
    END
  END c_h[294]
  PIN c_h[295]
    DIRECTION INPUT ;
    USE SIGNAL ;
    PORT
      LAYER M3 ;
        RECT  77.94 0 77.958 0.037 ;
    END
  END c_h[295]
  PIN c_h[296]
    DIRECTION INPUT ;
    USE SIGNAL ;
    PORT
      LAYER M3 ;
        RECT  78.012 0 78.03 0.037 ;
    END
  END c_h[296]
  PIN c_h[297]
    DIRECTION INPUT ;
    USE SIGNAL ;
    PORT
      LAYER M3 ;
        RECT  78.084 0 78.102 0.037 ;
    END
  END c_h[297]
  PIN c_h[298]
    DIRECTION INPUT ;
    USE SIGNAL ;
    PORT
      LAYER M3 ;
        RECT  78.156 0 78.174 0.037 ;
    END
  END c_h[298]
  PIN c_h[299]
    DIRECTION INPUT ;
    USE SIGNAL ;
    PORT
      LAYER M3 ;
        RECT  78.228 0 78.246 0.037 ;
    END
  END c_h[299]
  PIN c_h[29]
    DIRECTION INPUT ;
    USE SIGNAL ;
    PORT
      LAYER M5 ;
        RECT  16.176 0 16.2 0.084 ;
    END
  END c_h[29]
  PIN c_h[2]
    DIRECTION INPUT ;
    USE SIGNAL ;
    PORT
      LAYER M3 ;
        RECT  24.588 0 24.606 0.037 ;
    END
  END c_h[2]
  PIN c_h[300]
    DIRECTION INPUT ;
    USE SIGNAL ;
    PORT
      LAYER M3 ;
        RECT  78.3 0 78.318 0.037 ;
    END
  END c_h[300]
  PIN c_h[301]
    DIRECTION INPUT ;
    USE SIGNAL ;
    PORT
      LAYER M3 ;
        RECT  78.372 0 78.39 0.037 ;
    END
  END c_h[301]
  PIN c_h[302]
    DIRECTION INPUT ;
    USE SIGNAL ;
    PORT
      LAYER M3 ;
        RECT  78.444 0 78.462 0.037 ;
    END
  END c_h[302]
  PIN c_h[303]
    DIRECTION INPUT ;
    USE SIGNAL ;
    PORT
      LAYER M3 ;
        RECT  78.516 0 78.534 0.037 ;
    END
  END c_h[303]
  PIN c_h[304]
    DIRECTION INPUT ;
    USE SIGNAL ;
    PORT
      LAYER M3 ;
        RECT  78.588 0 78.606 0.037 ;
    END
  END c_h[304]
  PIN c_h[305]
    DIRECTION INPUT ;
    USE SIGNAL ;
    PORT
      LAYER M3 ;
        RECT  78.66 0 78.678 0.037 ;
    END
  END c_h[305]
  PIN c_h[306]
    DIRECTION INPUT ;
    USE SIGNAL ;
    PORT
      LAYER M3 ;
        RECT  78.732 0 78.75 0.037 ;
    END
  END c_h[306]
  PIN c_h[307]
    DIRECTION INPUT ;
    USE SIGNAL ;
    PORT
      LAYER M3 ;
        RECT  78.804 0 78.822 0.037 ;
    END
  END c_h[307]
  PIN c_h[308]
    DIRECTION INPUT ;
    USE SIGNAL ;
    PORT
      LAYER M3 ;
        RECT  78.876 0 78.894 0.037 ;
    END
  END c_h[308]
  PIN c_h[309]
    DIRECTION INPUT ;
    USE SIGNAL ;
    PORT
      LAYER M3 ;
        RECT  78.948 0 78.966 0.037 ;
    END
  END c_h[309]
  PIN c_h[30]
    DIRECTION INPUT ;
    USE SIGNAL ;
    PORT
      LAYER M5 ;
        RECT  16.272 0 16.296 0.084 ;
    END
  END c_h[30]
  PIN c_h[310]
    DIRECTION INPUT ;
    USE SIGNAL ;
    PORT
      LAYER M3 ;
        RECT  79.02 0 79.038 0.037 ;
    END
  END c_h[310]
  PIN c_h[311]
    DIRECTION INPUT ;
    USE SIGNAL ;
    PORT
      LAYER M3 ;
        RECT  79.092 0 79.11 0.037 ;
    END
  END c_h[311]
  PIN c_h[312]
    DIRECTION INPUT ;
    USE SIGNAL ;
    PORT
      LAYER M3 ;
        RECT  79.164 0 79.182 0.037 ;
    END
  END c_h[312]
  PIN c_h[313]
    DIRECTION INPUT ;
    USE SIGNAL ;
    PORT
      LAYER M3 ;
        RECT  79.236 0 79.254 0.037 ;
    END
  END c_h[313]
  PIN c_h[314]
    DIRECTION INPUT ;
    USE SIGNAL ;
    PORT
      LAYER M3 ;
        RECT  79.308 0 79.326 0.037 ;
    END
  END c_h[314]
  PIN c_h[315]
    DIRECTION INPUT ;
    USE SIGNAL ;
    PORT
      LAYER M3 ;
        RECT  79.38 0 79.398 0.037 ;
    END
  END c_h[315]
  PIN c_h[316]
    DIRECTION INPUT ;
    USE SIGNAL ;
    PORT
      LAYER M3 ;
        RECT  5.148 0 5.166 0.037 ;
    END
  END c_h[316]
  PIN c_h[317]
    DIRECTION INPUT ;
    USE SIGNAL ;
    PORT
      LAYER M3 ;
        RECT  5.22 0 5.238 0.037 ;
    END
  END c_h[317]
  PIN c_h[318]
    DIRECTION INPUT ;
    USE SIGNAL ;
    PORT
      LAYER M3 ;
        RECT  5.292 0 5.31 0.037 ;
    END
  END c_h[318]
  PIN c_h[319]
    DIRECTION INPUT ;
    USE SIGNAL ;
    PORT
      LAYER M3 ;
        RECT  5.364 0 5.382 0.037 ;
    END
  END c_h[319]
  PIN c_h[31]
    DIRECTION INPUT ;
    USE SIGNAL ;
    PORT
      LAYER M5 ;
        RECT  16.368 0 16.392 0.084 ;
    END
  END c_h[31]
  PIN c_h[320]
    DIRECTION INPUT ;
    USE SIGNAL ;
    PORT
      LAYER M3 ;
        RECT  5.436 0 5.454 0.037 ;
    END
  END c_h[320]
  PIN c_h[321]
    DIRECTION INPUT ;
    USE SIGNAL ;
    PORT
      LAYER M3 ;
        RECT  5.508 0 5.526 0.037 ;
    END
  END c_h[321]
  PIN c_h[322]
    DIRECTION INPUT ;
    USE SIGNAL ;
    PORT
      LAYER M3 ;
        RECT  5.58 0 5.598 0.037 ;
    END
  END c_h[322]
  PIN c_h[323]
    DIRECTION INPUT ;
    USE SIGNAL ;
    PORT
      LAYER M3 ;
        RECT  5.652 0 5.67 0.037 ;
    END
  END c_h[323]
  PIN c_h[324]
    DIRECTION INPUT ;
    USE SIGNAL ;
    PORT
      LAYER M3 ;
        RECT  5.724 0 5.742 0.037 ;
    END
  END c_h[324]
  PIN c_h[325]
    DIRECTION INPUT ;
    USE SIGNAL ;
    PORT
      LAYER M3 ;
        RECT  5.796 0 5.814 0.037 ;
    END
  END c_h[325]
  PIN c_h[326]
    DIRECTION INPUT ;
    USE SIGNAL ;
    PORT
      LAYER M3 ;
        RECT  5.868 0 5.886 0.037 ;
    END
  END c_h[326]
  PIN c_h[327]
    DIRECTION INPUT ;
    USE SIGNAL ;
    PORT
      LAYER M3 ;
        RECT  5.94 0 5.958 0.037 ;
    END
  END c_h[327]
  PIN c_h[328]
    DIRECTION INPUT ;
    USE SIGNAL ;
    PORT
      LAYER M3 ;
        RECT  6.012 0 6.03 0.037 ;
    END
  END c_h[328]
  PIN c_h[329]
    DIRECTION INPUT ;
    USE SIGNAL ;
    PORT
      LAYER M3 ;
        RECT  6.084 0 6.102 0.037 ;
    END
  END c_h[329]
  PIN c_h[32]
    DIRECTION INPUT ;
    USE SIGNAL ;
    PORT
      LAYER M5 ;
        RECT  16.464 0 16.488 0.084 ;
    END
  END c_h[32]
  PIN c_h[330]
    DIRECTION INPUT ;
    USE SIGNAL ;
    PORT
      LAYER M3 ;
        RECT  6.156 0 6.174 0.037 ;
    END
  END c_h[330]
  PIN c_h[331]
    DIRECTION INPUT ;
    USE SIGNAL ;
    PORT
      LAYER M3 ;
        RECT  6.228 0 6.246 0.037 ;
    END
  END c_h[331]
  PIN c_h[332]
    DIRECTION INPUT ;
    USE SIGNAL ;
    PORT
      LAYER M3 ;
        RECT  6.3 0 6.318 0.037 ;
    END
  END c_h[332]
  PIN c_h[333]
    DIRECTION INPUT ;
    USE SIGNAL ;
    PORT
      LAYER M3 ;
        RECT  6.372 0 6.39 0.037 ;
    END
  END c_h[333]
  PIN c_h[334]
    DIRECTION INPUT ;
    USE SIGNAL ;
    PORT
      LAYER M3 ;
        RECT  6.444 0 6.462 0.037 ;
    END
  END c_h[334]
  PIN c_h[335]
    DIRECTION INPUT ;
    USE SIGNAL ;
    PORT
      LAYER M3 ;
        RECT  6.516 0 6.534 0.037 ;
    END
  END c_h[335]
  PIN c_h[336]
    DIRECTION INPUT ;
    USE SIGNAL ;
    PORT
      LAYER M3 ;
        RECT  6.588 0 6.606 0.037 ;
    END
  END c_h[336]
  PIN c_h[337]
    DIRECTION INPUT ;
    USE SIGNAL ;
    PORT
      LAYER M3 ;
        RECT  6.66 0 6.678 0.037 ;
    END
  END c_h[337]
  PIN c_h[338]
    DIRECTION INPUT ;
    USE SIGNAL ;
    PORT
      LAYER M3 ;
        RECT  6.732 0 6.75 0.037 ;
    END
  END c_h[338]
  PIN c_h[339]
    DIRECTION INPUT ;
    USE SIGNAL ;
    PORT
      LAYER M3 ;
        RECT  6.804 0 6.822 0.037 ;
    END
  END c_h[339]
  PIN c_h[33]
    DIRECTION INPUT ;
    USE SIGNAL ;
    PORT
      LAYER M5 ;
        RECT  16.56 0 16.584 0.084 ;
    END
  END c_h[33]
  PIN c_h[340]
    DIRECTION INPUT ;
    USE SIGNAL ;
    PORT
      LAYER M3 ;
        RECT  6.876 0 6.894 0.037 ;
    END
  END c_h[340]
  PIN c_h[341]
    DIRECTION INPUT ;
    USE SIGNAL ;
    PORT
      LAYER M3 ;
        RECT  6.948 0 6.966 0.037 ;
    END
  END c_h[341]
  PIN c_h[342]
    DIRECTION INPUT ;
    USE SIGNAL ;
    PORT
      LAYER M3 ;
        RECT  7.02 0 7.038 0.037 ;
    END
  END c_h[342]
  PIN c_h[343]
    DIRECTION INPUT ;
    USE SIGNAL ;
    PORT
      LAYER M3 ;
        RECT  7.092 0 7.11 0.037 ;
    END
  END c_h[343]
  PIN c_h[344]
    DIRECTION INPUT ;
    USE SIGNAL ;
    PORT
      LAYER M3 ;
        RECT  7.164 0 7.182 0.037 ;
    END
  END c_h[344]
  PIN c_h[345]
    DIRECTION INPUT ;
    USE SIGNAL ;
    PORT
      LAYER M3 ;
        RECT  7.236 0 7.254 0.037 ;
    END
  END c_h[345]
  PIN c_h[346]
    DIRECTION INPUT ;
    USE SIGNAL ;
    PORT
      LAYER M3 ;
        RECT  7.308 0 7.326 0.037 ;
    END
  END c_h[346]
  PIN c_h[347]
    DIRECTION INPUT ;
    USE SIGNAL ;
    PORT
      LAYER M3 ;
        RECT  7.38 0 7.398 0.037 ;
    END
  END c_h[347]
  PIN c_h[348]
    DIRECTION INPUT ;
    USE SIGNAL ;
    PORT
      LAYER M5 ;
        RECT  13.008 0 13.032 0.084 ;
    END
  END c_h[348]
  PIN c_h[349]
    DIRECTION INPUT ;
    USE SIGNAL ;
    PORT
      LAYER M5 ;
        RECT  13.104 0 13.128 0.084 ;
    END
  END c_h[349]
  PIN c_h[34]
    DIRECTION INPUT ;
    USE SIGNAL ;
    PORT
      LAYER M5 ;
        RECT  16.656 0 16.68 0.084 ;
    END
  END c_h[34]
  PIN c_h[350]
    DIRECTION INPUT ;
    USE SIGNAL ;
    PORT
      LAYER M5 ;
        RECT  13.2 0 13.224 0.084 ;
    END
  END c_h[350]
  PIN c_h[351]
    DIRECTION INPUT ;
    USE SIGNAL ;
    PORT
      LAYER M5 ;
        RECT  13.296 0 13.32 0.084 ;
    END
  END c_h[351]
  PIN c_h[352]
    DIRECTION INPUT ;
    USE SIGNAL ;
    PORT
      LAYER M5 ;
        RECT  13.392 0 13.416 0.084 ;
    END
  END c_h[352]
  PIN c_h[353]
    DIRECTION INPUT ;
    USE SIGNAL ;
    PORT
      LAYER M5 ;
        RECT  13.488 0 13.512 0.084 ;
    END
  END c_h[353]
  PIN c_h[354]
    DIRECTION INPUT ;
    USE SIGNAL ;
    PORT
      LAYER M5 ;
        RECT  13.584 0 13.608 0.084 ;
    END
  END c_h[354]
  PIN c_h[355]
    DIRECTION INPUT ;
    USE SIGNAL ;
    PORT
      LAYER M5 ;
        RECT  13.68 0 13.704 0.084 ;
    END
  END c_h[355]
  PIN c_h[356]
    DIRECTION INPUT ;
    USE SIGNAL ;
    PORT
      LAYER M5 ;
        RECT  13.776 0 13.8 0.084 ;
    END
  END c_h[356]
  PIN c_h[357]
    DIRECTION INPUT ;
    USE SIGNAL ;
    PORT
      LAYER M5 ;
        RECT  13.872 0 13.896 0.084 ;
    END
  END c_h[357]
  PIN c_h[358]
    DIRECTION INPUT ;
    USE SIGNAL ;
    PORT
      LAYER M5 ;
        RECT  13.968 0 13.992 0.084 ;
    END
  END c_h[358]
  PIN c_h[359]
    DIRECTION INPUT ;
    USE SIGNAL ;
    PORT
      LAYER M5 ;
        RECT  14.064 0 14.088 0.084 ;
    END
  END c_h[359]
  PIN c_h[35]
    DIRECTION INPUT ;
    USE SIGNAL ;
    PORT
      LAYER M5 ;
        RECT  16.752 0 16.776 0.084 ;
    END
  END c_h[35]
  PIN c_h[360]
    DIRECTION INPUT ;
    USE SIGNAL ;
    PORT
      LAYER M5 ;
        RECT  14.16 0 14.184 0.084 ;
    END
  END c_h[360]
  PIN c_h[361]
    DIRECTION INPUT ;
    USE SIGNAL ;
    PORT
      LAYER M5 ;
        RECT  14.256 0 14.28 0.084 ;
    END
  END c_h[361]
  PIN c_h[362]
    DIRECTION INPUT ;
    USE SIGNAL ;
    PORT
      LAYER M5 ;
        RECT  14.352 0 14.376 0.084 ;
    END
  END c_h[362]
  PIN c_h[363]
    DIRECTION INPUT ;
    USE SIGNAL ;
    PORT
      LAYER M5 ;
        RECT  14.448 0 14.472 0.084 ;
    END
  END c_h[363]
  PIN c_h[364]
    DIRECTION INPUT ;
    USE SIGNAL ;
    PORT
      LAYER M5 ;
        RECT  14.544 0 14.568 0.084 ;
    END
  END c_h[364]
  PIN c_h[365]
    DIRECTION INPUT ;
    USE SIGNAL ;
    PORT
      LAYER M5 ;
        RECT  14.64 0 14.664 0.084 ;
    END
  END c_h[365]
  PIN c_h[366]
    DIRECTION INPUT ;
    USE SIGNAL ;
    PORT
      LAYER M5 ;
        RECT  14.736 0 14.76 0.084 ;
    END
  END c_h[366]
  PIN c_h[367]
    DIRECTION INPUT ;
    USE SIGNAL ;
    PORT
      LAYER M5 ;
        RECT  14.832 0 14.856 0.084 ;
    END
  END c_h[367]
  PIN c_h[368]
    DIRECTION INPUT ;
    USE SIGNAL ;
    PORT
      LAYER M5 ;
        RECT  14.928 0 14.952 0.084 ;
    END
  END c_h[368]
  PIN c_h[369]
    DIRECTION INPUT ;
    USE SIGNAL ;
    PORT
      LAYER M5 ;
        RECT  15.024 0 15.048 0.084 ;
    END
  END c_h[369]
  PIN c_h[36]
    DIRECTION INPUT ;
    USE SIGNAL ;
    PORT
      LAYER M5 ;
        RECT  16.848 0 16.872 0.084 ;
    END
  END c_h[36]
  PIN c_h[370]
    DIRECTION INPUT ;
    USE SIGNAL ;
    PORT
      LAYER M5 ;
        RECT  15.12 0 15.144 0.084 ;
    END
  END c_h[370]
  PIN c_h[371]
    DIRECTION INPUT ;
    USE SIGNAL ;
    PORT
      LAYER M5 ;
        RECT  15.216 0 15.24 0.084 ;
    END
  END c_h[371]
  PIN c_h[372]
    DIRECTION INPUT ;
    USE SIGNAL ;
    PORT
      LAYER M5 ;
        RECT  15.312 0 15.336 0.084 ;
    END
  END c_h[372]
  PIN c_h[373]
    DIRECTION INPUT ;
    USE SIGNAL ;
    PORT
      LAYER M5 ;
        RECT  15.408 0 15.432 0.084 ;
    END
  END c_h[373]
  PIN c_h[374]
    DIRECTION INPUT ;
    USE SIGNAL ;
    PORT
      LAYER M5 ;
        RECT  15.504 0 15.528 0.084 ;
    END
  END c_h[374]
  PIN c_h[375]
    DIRECTION INPUT ;
    USE SIGNAL ;
    PORT
      LAYER M5 ;
        RECT  15.6 0 15.624 0.084 ;
    END
  END c_h[375]
  PIN c_h[376]
    DIRECTION INPUT ;
    USE SIGNAL ;
    PORT
      LAYER M5 ;
        RECT  15.696 0 15.72 0.084 ;
    END
  END c_h[376]
  PIN c_h[377]
    DIRECTION INPUT ;
    USE SIGNAL ;
    PORT
      LAYER M5 ;
        RECT  15.792 0 15.816 0.084 ;
    END
  END c_h[377]
  PIN c_h[378]
    DIRECTION INPUT ;
    USE SIGNAL ;
    PORT
      LAYER M5 ;
        RECT  15.888 0 15.912 0.084 ;
    END
  END c_h[378]
  PIN c_h[379]
    DIRECTION INPUT ;
    USE SIGNAL ;
    PORT
      LAYER M5 ;
        RECT  15.984 0 16.008 0.084 ;
    END
  END c_h[379]
  PIN c_h[37]
    DIRECTION INPUT ;
    USE SIGNAL ;
    PORT
      LAYER M5 ;
        RECT  16.944 0 16.968 0.084 ;
    END
  END c_h[37]
  PIN c_h[380]
    DIRECTION INPUT ;
    USE SIGNAL ;
    PORT
      LAYER M5 ;
        RECT  9.936 0 9.96 0.084 ;
    END
  END c_h[380]
  PIN c_h[381]
    DIRECTION INPUT ;
    USE SIGNAL ;
    PORT
      LAYER M5 ;
        RECT  10.032 0 10.056 0.084 ;
    END
  END c_h[381]
  PIN c_h[382]
    DIRECTION INPUT ;
    USE SIGNAL ;
    PORT
      LAYER M5 ;
        RECT  10.128 0 10.152 0.084 ;
    END
  END c_h[382]
  PIN c_h[383]
    DIRECTION INPUT ;
    USE SIGNAL ;
    PORT
      LAYER M5 ;
        RECT  10.224 0 10.248 0.084 ;
    END
  END c_h[383]
  PIN c_h[384]
    DIRECTION INPUT ;
    USE SIGNAL ;
    PORT
      LAYER M5 ;
        RECT  10.32 0 10.344 0.084 ;
    END
  END c_h[384]
  PIN c_h[385]
    DIRECTION INPUT ;
    USE SIGNAL ;
    PORT
      LAYER M5 ;
        RECT  10.416 0 10.44 0.084 ;
    END
  END c_h[385]
  PIN c_h[386]
    DIRECTION INPUT ;
    USE SIGNAL ;
    PORT
      LAYER M5 ;
        RECT  10.512 0 10.536 0.084 ;
    END
  END c_h[386]
  PIN c_h[387]
    DIRECTION INPUT ;
    USE SIGNAL ;
    PORT
      LAYER M5 ;
        RECT  10.608 0 10.632 0.084 ;
    END
  END c_h[387]
  PIN c_h[388]
    DIRECTION INPUT ;
    USE SIGNAL ;
    PORT
      LAYER M5 ;
        RECT  10.704 0 10.728 0.084 ;
    END
  END c_h[388]
  PIN c_h[389]
    DIRECTION INPUT ;
    USE SIGNAL ;
    PORT
      LAYER M5 ;
        RECT  10.8 0 10.824 0.084 ;
    END
  END c_h[389]
  PIN c_h[38]
    DIRECTION INPUT ;
    USE SIGNAL ;
    PORT
      LAYER M5 ;
        RECT  17.04 0 17.064 0.084 ;
    END
  END c_h[38]
  PIN c_h[390]
    DIRECTION INPUT ;
    USE SIGNAL ;
    PORT
      LAYER M5 ;
        RECT  10.896 0 10.92 0.084 ;
    END
  END c_h[390]
  PIN c_h[391]
    DIRECTION INPUT ;
    USE SIGNAL ;
    PORT
      LAYER M5 ;
        RECT  10.992 0 11.016 0.084 ;
    END
  END c_h[391]
  PIN c_h[392]
    DIRECTION INPUT ;
    USE SIGNAL ;
    PORT
      LAYER M5 ;
        RECT  11.088 0 11.112 0.084 ;
    END
  END c_h[392]
  PIN c_h[393]
    DIRECTION INPUT ;
    USE SIGNAL ;
    PORT
      LAYER M5 ;
        RECT  11.184 0 11.208 0.084 ;
    END
  END c_h[393]
  PIN c_h[394]
    DIRECTION INPUT ;
    USE SIGNAL ;
    PORT
      LAYER M5 ;
        RECT  11.28 0 11.304 0.084 ;
    END
  END c_h[394]
  PIN c_h[395]
    DIRECTION INPUT ;
    USE SIGNAL ;
    PORT
      LAYER M5 ;
        RECT  11.376 0 11.4 0.084 ;
    END
  END c_h[395]
  PIN c_h[396]
    DIRECTION INPUT ;
    USE SIGNAL ;
    PORT
      LAYER M5 ;
        RECT  11.472 0 11.496 0.084 ;
    END
  END c_h[396]
  PIN c_h[397]
    DIRECTION INPUT ;
    USE SIGNAL ;
    PORT
      LAYER M5 ;
        RECT  11.568 0 11.592 0.084 ;
    END
  END c_h[397]
  PIN c_h[398]
    DIRECTION INPUT ;
    USE SIGNAL ;
    PORT
      LAYER M5 ;
        RECT  11.664 0 11.688 0.084 ;
    END
  END c_h[398]
  PIN c_h[399]
    DIRECTION INPUT ;
    USE SIGNAL ;
    PORT
      LAYER M5 ;
        RECT  11.76 0 11.784 0.084 ;
    END
  END c_h[399]
  PIN c_h[39]
    DIRECTION INPUT ;
    USE SIGNAL ;
    PORT
      LAYER M5 ;
        RECT  17.136 0 17.16 0.084 ;
    END
  END c_h[39]
  PIN c_h[3]
    DIRECTION INPUT ;
    USE SIGNAL ;
    PORT
      LAYER M3 ;
        RECT  24.66 0 24.678 0.037 ;
    END
  END c_h[3]
  PIN c_h[400]
    DIRECTION INPUT ;
    USE SIGNAL ;
    PORT
      LAYER M5 ;
        RECT  11.856 0 11.88 0.084 ;
    END
  END c_h[400]
  PIN c_h[401]
    DIRECTION INPUT ;
    USE SIGNAL ;
    PORT
      LAYER M5 ;
        RECT  11.952 0 11.976 0.084 ;
    END
  END c_h[401]
  PIN c_h[402]
    DIRECTION INPUT ;
    USE SIGNAL ;
    PORT
      LAYER M5 ;
        RECT  12.048 0 12.072 0.084 ;
    END
  END c_h[402]
  PIN c_h[403]
    DIRECTION INPUT ;
    USE SIGNAL ;
    PORT
      LAYER M5 ;
        RECT  12.144 0 12.168 0.084 ;
    END
  END c_h[403]
  PIN c_h[404]
    DIRECTION INPUT ;
    USE SIGNAL ;
    PORT
      LAYER M5 ;
        RECT  12.24 0 12.264 0.084 ;
    END
  END c_h[404]
  PIN c_h[405]
    DIRECTION INPUT ;
    USE SIGNAL ;
    PORT
      LAYER M5 ;
        RECT  12.336 0 12.36 0.084 ;
    END
  END c_h[405]
  PIN c_h[406]
    DIRECTION INPUT ;
    USE SIGNAL ;
    PORT
      LAYER M5 ;
        RECT  12.432 0 12.456 0.084 ;
    END
  END c_h[406]
  PIN c_h[407]
    DIRECTION INPUT ;
    USE SIGNAL ;
    PORT
      LAYER M5 ;
        RECT  12.528 0 12.552 0.084 ;
    END
  END c_h[407]
  PIN c_h[408]
    DIRECTION INPUT ;
    USE SIGNAL ;
    PORT
      LAYER M5 ;
        RECT  12.624 0 12.648 0.084 ;
    END
  END c_h[408]
  PIN c_h[409]
    DIRECTION INPUT ;
    USE SIGNAL ;
    PORT
      LAYER M5 ;
        RECT  12.72 0 12.744 0.084 ;
    END
  END c_h[409]
  PIN c_h[40]
    DIRECTION INPUT ;
    USE SIGNAL ;
    PORT
      LAYER M5 ;
        RECT  17.232 0 17.256 0.084 ;
    END
  END c_h[40]
  PIN c_h[410]
    DIRECTION INPUT ;
    USE SIGNAL ;
    PORT
      LAYER M5 ;
        RECT  12.816 0 12.84 0.084 ;
    END
  END c_h[410]
  PIN c_h[411]
    DIRECTION INPUT ;
    USE SIGNAL ;
    PORT
      LAYER M5 ;
        RECT  12.912 0 12.936 0.084 ;
    END
  END c_h[411]
  PIN c_h[412]
    DIRECTION INPUT ;
    USE SIGNAL ;
    PORT
      LAYER M3 ;
        RECT  29.34 0 29.358 0.037 ;
    END
  END c_h[412]
  PIN c_h[413]
    DIRECTION INPUT ;
    USE SIGNAL ;
    PORT
      LAYER M3 ;
        RECT  29.412 0 29.43 0.037 ;
    END
  END c_h[413]
  PIN c_h[414]
    DIRECTION INPUT ;
    USE SIGNAL ;
    PORT
      LAYER M3 ;
        RECT  29.484 0 29.502 0.037 ;
    END
  END c_h[414]
  PIN c_h[415]
    DIRECTION INPUT ;
    USE SIGNAL ;
    PORT
      LAYER M3 ;
        RECT  29.556 0 29.574 0.037 ;
    END
  END c_h[415]
  PIN c_h[41]
    DIRECTION INPUT ;
    USE SIGNAL ;
    PORT
      LAYER M5 ;
        RECT  17.328 0 17.352 0.084 ;
    END
  END c_h[41]
  PIN c_h[42]
    DIRECTION INPUT ;
    USE SIGNAL ;
    PORT
      LAYER M5 ;
        RECT  17.424 0 17.448 0.084 ;
    END
  END c_h[42]
  PIN c_h[43]
    DIRECTION INPUT ;
    USE SIGNAL ;
    PORT
      LAYER M5 ;
        RECT  17.52 0 17.544 0.084 ;
    END
  END c_h[43]
  PIN c_h[44]
    DIRECTION INPUT ;
    USE SIGNAL ;
    PORT
      LAYER M5 ;
        RECT  17.616 0 17.64 0.084 ;
    END
  END c_h[44]
  PIN c_h[45]
    DIRECTION INPUT ;
    USE SIGNAL ;
    PORT
      LAYER M5 ;
        RECT  17.712 0 17.736 0.084 ;
    END
  END c_h[45]
  PIN c_h[46]
    DIRECTION INPUT ;
    USE SIGNAL ;
    PORT
      LAYER M5 ;
        RECT  17.808 0 17.832 0.084 ;
    END
  END c_h[46]
  PIN c_h[47]
    DIRECTION INPUT ;
    USE SIGNAL ;
    PORT
      LAYER M5 ;
        RECT  17.904 0 17.928 0.084 ;
    END
  END c_h[47]
  PIN c_h[48]
    DIRECTION INPUT ;
    USE SIGNAL ;
    PORT
      LAYER M5 ;
        RECT  18 0 18.024 0.084 ;
    END
  END c_h[48]
  PIN c_h[49]
    DIRECTION INPUT ;
    USE SIGNAL ;
    PORT
      LAYER M5 ;
        RECT  18.096 0 18.12 0.084 ;
    END
  END c_h[49]
  PIN c_h[4]
    DIRECTION INPUT ;
    USE SIGNAL ;
    PORT
      LAYER M3 ;
        RECT  24.732 0 24.75 0.037 ;
    END
  END c_h[4]
  PIN c_h[50]
    DIRECTION INPUT ;
    USE SIGNAL ;
    PORT
      LAYER M5 ;
        RECT  18.192 0 18.216 0.084 ;
    END
  END c_h[50]
  PIN c_h[51]
    DIRECTION INPUT ;
    USE SIGNAL ;
    PORT
      LAYER M5 ;
        RECT  18.288 0 18.312 0.084 ;
    END
  END c_h[51]
  PIN c_h[52]
    DIRECTION INPUT ;
    USE SIGNAL ;
    PORT
      LAYER M5 ;
        RECT  18.384 0 18.408 0.084 ;
    END
  END c_h[52]
  PIN c_h[53]
    DIRECTION INPUT ;
    USE SIGNAL ;
    PORT
      LAYER M5 ;
        RECT  18.48 0 18.504 0.084 ;
    END
  END c_h[53]
  PIN c_h[54]
    DIRECTION INPUT ;
    USE SIGNAL ;
    PORT
      LAYER M5 ;
        RECT  18.576 0 18.6 0.084 ;
    END
  END c_h[54]
  PIN c_h[55]
    DIRECTION INPUT ;
    USE SIGNAL ;
    PORT
      LAYER M5 ;
        RECT  18.672 0 18.696 0.084 ;
    END
  END c_h[55]
  PIN c_h[56]
    DIRECTION INPUT ;
    USE SIGNAL ;
    PORT
      LAYER M5 ;
        RECT  18.768 0 18.792 0.084 ;
    END
  END c_h[56]
  PIN c_h[57]
    DIRECTION INPUT ;
    USE SIGNAL ;
    PORT
      LAYER M5 ;
        RECT  18.864 0 18.888 0.084 ;
    END
  END c_h[57]
  PIN c_h[58]
    DIRECTION INPUT ;
    USE SIGNAL ;
    PORT
      LAYER M5 ;
        RECT  18.96 0 18.984 0.084 ;
    END
  END c_h[58]
  PIN c_h[59]
    DIRECTION INPUT ;
    USE SIGNAL ;
    PORT
      LAYER M5 ;
        RECT  19.056 0 19.08 0.084 ;
    END
  END c_h[59]
  PIN c_h[5]
    DIRECTION INPUT ;
    USE SIGNAL ;
    PORT
      LAYER M3 ;
        RECT  24.804 0 24.822 0.037 ;
    END
  END c_h[5]
  PIN c_h[60]
    DIRECTION INPUT ;
    USE SIGNAL ;
    PORT
      LAYER M3 ;
        RECT  2.844 0 2.862 0.037 ;
    END
  END c_h[60]
  PIN c_h[61]
    DIRECTION INPUT ;
    USE SIGNAL ;
    PORT
      LAYER M3 ;
        RECT  2.916 0 2.934 0.037 ;
    END
  END c_h[61]
  PIN c_h[62]
    DIRECTION INPUT ;
    USE SIGNAL ;
    PORT
      LAYER M3 ;
        RECT  2.988 0 3.006 0.037 ;
    END
  END c_h[62]
  PIN c_h[63]
    DIRECTION INPUT ;
    USE SIGNAL ;
    PORT
      LAYER M3 ;
        RECT  3.06 0 3.078 0.037 ;
    END
  END c_h[63]
  PIN c_h[64]
    DIRECTION INPUT ;
    USE SIGNAL ;
    PORT
      LAYER M3 ;
        RECT  3.132 0 3.15 0.037 ;
    END
  END c_h[64]
  PIN c_h[65]
    DIRECTION INPUT ;
    USE SIGNAL ;
    PORT
      LAYER M3 ;
        RECT  3.204 0 3.222 0.037 ;
    END
  END c_h[65]
  PIN c_h[66]
    DIRECTION INPUT ;
    USE SIGNAL ;
    PORT
      LAYER M3 ;
        RECT  3.276 0 3.294 0.037 ;
    END
  END c_h[66]
  PIN c_h[67]
    DIRECTION INPUT ;
    USE SIGNAL ;
    PORT
      LAYER M3 ;
        RECT  3.348 0 3.366 0.037 ;
    END
  END c_h[67]
  PIN c_h[68]
    DIRECTION INPUT ;
    USE SIGNAL ;
    PORT
      LAYER M3 ;
        RECT  3.42 0 3.438 0.037 ;
    END
  END c_h[68]
  PIN c_h[69]
    DIRECTION INPUT ;
    USE SIGNAL ;
    PORT
      LAYER M3 ;
        RECT  3.492 0 3.51 0.037 ;
    END
  END c_h[69]
  PIN c_h[6]
    DIRECTION INPUT ;
    USE SIGNAL ;
    PORT
      LAYER M3 ;
        RECT  24.876 0 24.894 0.037 ;
    END
  END c_h[6]
  PIN c_h[70]
    DIRECTION INPUT ;
    USE SIGNAL ;
    PORT
      LAYER M3 ;
        RECT  3.564 0 3.582 0.037 ;
    END
  END c_h[70]
  PIN c_h[71]
    DIRECTION INPUT ;
    USE SIGNAL ;
    PORT
      LAYER M3 ;
        RECT  3.636 0 3.654 0.037 ;
    END
  END c_h[71]
  PIN c_h[72]
    DIRECTION INPUT ;
    USE SIGNAL ;
    PORT
      LAYER M3 ;
        RECT  3.708 0 3.726 0.037 ;
    END
  END c_h[72]
  PIN c_h[73]
    DIRECTION INPUT ;
    USE SIGNAL ;
    PORT
      LAYER M3 ;
        RECT  3.78 0 3.798 0.037 ;
    END
  END c_h[73]
  PIN c_h[74]
    DIRECTION INPUT ;
    USE SIGNAL ;
    PORT
      LAYER M3 ;
        RECT  3.852 0 3.87 0.037 ;
    END
  END c_h[74]
  PIN c_h[75]
    DIRECTION INPUT ;
    USE SIGNAL ;
    PORT
      LAYER M3 ;
        RECT  3.924 0 3.942 0.037 ;
    END
  END c_h[75]
  PIN c_h[76]
    DIRECTION INPUT ;
    USE SIGNAL ;
    PORT
      LAYER M3 ;
        RECT  3.996 0 4.014 0.037 ;
    END
  END c_h[76]
  PIN c_h[77]
    DIRECTION INPUT ;
    USE SIGNAL ;
    PORT
      LAYER M3 ;
        RECT  4.068 0 4.086 0.037 ;
    END
  END c_h[77]
  PIN c_h[78]
    DIRECTION INPUT ;
    USE SIGNAL ;
    PORT
      LAYER M3 ;
        RECT  4.14 0 4.158 0.037 ;
    END
  END c_h[78]
  PIN c_h[79]
    DIRECTION INPUT ;
    USE SIGNAL ;
    PORT
      LAYER M3 ;
        RECT  4.212 0 4.23 0.037 ;
    END
  END c_h[79]
  PIN c_h[7]
    DIRECTION INPUT ;
    USE SIGNAL ;
    PORT
      LAYER M3 ;
        RECT  24.948 0 24.966 0.037 ;
    END
  END c_h[7]
  PIN c_h[80]
    DIRECTION INPUT ;
    USE SIGNAL ;
    PORT
      LAYER M3 ;
        RECT  4.284 0 4.302 0.037 ;
    END
  END c_h[80]
  PIN c_h[81]
    DIRECTION INPUT ;
    USE SIGNAL ;
    PORT
      LAYER M3 ;
        RECT  4.356 0 4.374 0.037 ;
    END
  END c_h[81]
  PIN c_h[82]
    DIRECTION INPUT ;
    USE SIGNAL ;
    PORT
      LAYER M3 ;
        RECT  4.428 0 4.446 0.037 ;
    END
  END c_h[82]
  PIN c_h[83]
    DIRECTION INPUT ;
    USE SIGNAL ;
    PORT
      LAYER M3 ;
        RECT  4.5 0 4.518 0.037 ;
    END
  END c_h[83]
  PIN c_h[84]
    DIRECTION INPUT ;
    USE SIGNAL ;
    PORT
      LAYER M3 ;
        RECT  4.572 0 4.59 0.037 ;
    END
  END c_h[84]
  PIN c_h[85]
    DIRECTION INPUT ;
    USE SIGNAL ;
    PORT
      LAYER M3 ;
        RECT  4.644 0 4.662 0.037 ;
    END
  END c_h[85]
  PIN c_h[86]
    DIRECTION INPUT ;
    USE SIGNAL ;
    PORT
      LAYER M3 ;
        RECT  4.716 0 4.734 0.037 ;
    END
  END c_h[86]
  PIN c_h[87]
    DIRECTION INPUT ;
    USE SIGNAL ;
    PORT
      LAYER M3 ;
        RECT  4.788 0 4.806 0.037 ;
    END
  END c_h[87]
  PIN c_h[88]
    DIRECTION INPUT ;
    USE SIGNAL ;
    PORT
      LAYER M3 ;
        RECT  4.86 0 4.878 0.037 ;
    END
  END c_h[88]
  PIN c_h[89]
    DIRECTION INPUT ;
    USE SIGNAL ;
    PORT
      LAYER M3 ;
        RECT  4.932 0 4.95 0.037 ;
    END
  END c_h[89]
  PIN c_h[8]
    DIRECTION INPUT ;
    USE SIGNAL ;
    PORT
      LAYER M3 ;
        RECT  25.02 0 25.038 0.037 ;
    END
  END c_h[8]
  PIN c_h[90]
    DIRECTION INPUT ;
    USE SIGNAL ;
    PORT
      LAYER M3 ;
        RECT  5.004 0 5.022 0.037 ;
    END
  END c_h[90]
  PIN c_h[91]
    DIRECTION INPUT ;
    USE SIGNAL ;
    PORT
      LAYER M3 ;
        RECT  5.076 0 5.094 0.037 ;
    END
  END c_h[91]
  PIN c_h[92]
    DIRECTION INPUT ;
    USE SIGNAL ;
    PORT
      LAYER M3 ;
        RECT  52.956 0 52.974 0.037 ;
    END
  END c_h[92]
  PIN c_h[93]
    DIRECTION INPUT ;
    USE SIGNAL ;
    PORT
      LAYER M3 ;
        RECT  53.028 0 53.046 0.037 ;
    END
  END c_h[93]
  PIN c_h[94]
    DIRECTION INPUT ;
    USE SIGNAL ;
    PORT
      LAYER M3 ;
        RECT  53.1 0 53.118 0.037 ;
    END
  END c_h[94]
  PIN c_h[95]
    DIRECTION INPUT ;
    USE SIGNAL ;
    PORT
      LAYER M3 ;
        RECT  53.172 0 53.19 0.037 ;
    END
  END c_h[95]
  PIN c_h[96]
    DIRECTION INPUT ;
    USE SIGNAL ;
    PORT
      LAYER M3 ;
        RECT  53.244 0 53.262 0.037 ;
    END
  END c_h[96]
  PIN c_h[97]
    DIRECTION INPUT ;
    USE SIGNAL ;
    PORT
      LAYER M3 ;
        RECT  53.316 0 53.334 0.037 ;
    END
  END c_h[97]
  PIN c_h[98]
    DIRECTION INPUT ;
    USE SIGNAL ;
    PORT
      LAYER M3 ;
        RECT  53.388 0 53.406 0.037 ;
    END
  END c_h[98]
  PIN c_h[99]
    DIRECTION INPUT ;
    USE SIGNAL ;
    PORT
      LAYER M3 ;
        RECT  53.46 0 53.478 0.037 ;
    END
  END c_h[99]
  PIN c_h[9]
    DIRECTION INPUT ;
    USE SIGNAL ;
    PORT
      LAYER M3 ;
        RECT  25.092 0 25.11 0.037 ;
    END
  END c_h[9]
  PIN c_v[0]
    DIRECTION INPUT ;
    USE SIGNAL ;
    PORT
      LAYER M3 ;
        RECT  29.628 0 29.646 0.037 ;
    END
  END c_v[0]
  PIN c_v[1]
    DIRECTION INPUT ;
    USE SIGNAL ;
    PORT
      LAYER M3 ;
        RECT  29.7 0 29.718 0.037 ;
    END
  END c_v[1]
  PIN c_v[2]
    DIRECTION INPUT ;
    USE SIGNAL ;
    PORT
      LAYER M3 ;
        RECT  29.772 0 29.79 0.037 ;
    END
  END c_v[2]
  PIN c_v[3]
    DIRECTION INPUT ;
    USE SIGNAL ;
    PORT
      LAYER M3 ;
        RECT  29.844 0 29.862 0.037 ;
    END
  END c_v[3]
  PIN clk
    DIRECTION INPUT ;
    USE SIGNAL ;
    PORT
      LAYER M4 ;
        RECT  0 24.72 0.084 24.744 ;
    END
  END clk
  PIN ks_ord[0]
    DIRECTION OUTPUT ;
    USE SIGNAL ;
    PORT
      LAYER M5 ;
        RECT  42.672 64.716 42.696 64.8 ;
    END
  END ks_ord[0]
  PIN ks_ord[10]
    DIRECTION OUTPUT ;
    USE SIGNAL ;
    PORT
      LAYER M5 ;
        RECT  43.632 64.716 43.656 64.8 ;
    END
  END ks_ord[10]
  PIN ks_ord[1]
    DIRECTION OUTPUT ;
    USE SIGNAL ;
    PORT
      LAYER M5 ;
        RECT  42.768 64.716 42.792 64.8 ;
    END
  END ks_ord[1]
  PIN ks_ord[2]
    DIRECTION OUTPUT ;
    USE SIGNAL ;
    PORT
      LAYER M5 ;
        RECT  42.864 64.716 42.888 64.8 ;
    END
  END ks_ord[2]
  PIN ks_ord[3]
    DIRECTION OUTPUT ;
    USE SIGNAL ;
    PORT
      LAYER M5 ;
        RECT  42.96 64.716 42.984 64.8 ;
    END
  END ks_ord[3]
  PIN ks_ord[4]
    DIRECTION OUTPUT ;
    USE SIGNAL ;
    PORT
      LAYER M5 ;
        RECT  43.056 64.716 43.08 64.8 ;
    END
  END ks_ord[4]
  PIN ks_ord[5]
    DIRECTION OUTPUT ;
    USE SIGNAL ;
    PORT
      LAYER M5 ;
        RECT  43.152 64.716 43.176 64.8 ;
    END
  END ks_ord[5]
  PIN ks_ord[6]
    DIRECTION OUTPUT ;
    USE SIGNAL ;
    PORT
      LAYER M5 ;
        RECT  43.248 64.716 43.272 64.8 ;
    END
  END ks_ord[6]
  PIN ks_ord[7]
    DIRECTION OUTPUT ;
    USE SIGNAL ;
    PORT
      LAYER M5 ;
        RECT  43.344 64.716 43.368 64.8 ;
    END
  END ks_ord[7]
  PIN ks_ord[8]
    DIRECTION OUTPUT ;
    USE SIGNAL ;
    PORT
      LAYER M5 ;
        RECT  43.44 64.716 43.464 64.8 ;
    END
  END ks_ord[8]
  PIN ks_ord[9]
    DIRECTION OUTPUT ;
    USE SIGNAL ;
    PORT
      LAYER M5 ;
        RECT  43.536 64.716 43.56 64.8 ;
    END
  END ks_ord[9]
  PIN ks_v
    DIRECTION OUTPUT ;
    USE SIGNAL ;
    PORT
      LAYER M5 ;
        RECT  43.728 64.716 43.752 64.8 ;
    END
  END ks_v
  PIN rank_i[0]
    DIRECTION INPUT ;
    USE SIGNAL ;
    PORT
      LAYER M4 ;
        RECT  0 24.816 0.084 24.84 ;
    END
  END rank_i[0]
  PIN rank_i[1]
    DIRECTION INPUT ;
    USE SIGNAL ;
    PORT
      LAYER M4 ;
        RECT  0 24.912 0.084 24.936 ;
    END
  END rank_i[1]
  PIN rank_i[2]
    DIRECTION INPUT ;
    USE SIGNAL ;
    PORT
      LAYER M4 ;
        RECT  0 25.008 0.084 25.032 ;
    END
  END rank_i[2]
  PIN rank_i[3]
    DIRECTION INPUT ;
    USE SIGNAL ;
    PORT
      LAYER M4 ;
        RECT  0 25.104 0.084 25.128 ;
    END
  END rank_i[3]
  PIN rank_i[4]
    DIRECTION INPUT ;
    USE SIGNAL ;
    PORT
      LAYER M4 ;
        RECT  0 25.2 0.084 25.224 ;
    END
  END rank_i[4]
  PIN rank_i[5]
    DIRECTION INPUT ;
    USE SIGNAL ;
    PORT
      LAYER M4 ;
        RECT  0 25.296 0.084 25.32 ;
    END
  END rank_i[5]
  PIN rank_i[6]
    DIRECTION INPUT ;
    USE SIGNAL ;
    PORT
      LAYER M4 ;
        RECT  0 25.392 0.084 25.416 ;
    END
  END rank_i[6]
  PIN rst_n
    DIRECTION INPUT ;
    USE SIGNAL ;
    PORT
      LAYER M4 ;
        RECT  0 25.488 0.084 25.512 ;
    END
  END rst_n
  PIN start
    DIRECTION INPUT ;
    USE SIGNAL ;
    PORT
      LAYER M4 ;
        RECT  0 25.584 0.084 25.608 ;
    END
  END start
  PIN VDD
    DIRECTION INOUT ;
    USE POWER ;
    PORT
      LAYER M5 ;
        RECT  83.592 2.151 83.712 62.649 ;
        RECT  78.192 2.151 78.312 62.649 ;
        RECT  72.792 2.151 72.912 62.649 ;
        RECT  67.392 2.151 67.512 62.649 ;
        RECT  61.992 2.151 62.112 62.649 ;
        RECT  56.592 2.151 56.712 62.649 ;
        RECT  51.192 2.151 51.312 62.649 ;
        RECT  45.792 2.151 45.912 62.649 ;
        RECT  40.392 2.151 40.512 62.649 ;
        RECT  34.992 2.151 35.112 62.649 ;
        RECT  29.592 2.151 29.712 62.649 ;
        RECT  24.192 2.151 24.312 62.649 ;
        RECT  18.792 2.151 18.912 62.649 ;
        RECT  13.392 2.151 13.512 62.649 ;
        RECT  7.992 2.151 8.112 62.649 ;
        RECT  2.592 2.151 2.712 62.649 ;
    END
  END VDD
  PIN VSS
    DIRECTION INOUT ;
    USE GROUND ;
    PORT
      LAYER M5 ;
        RECT  83.4 2.137 83.52 62.663 ;
        RECT  78 2.137 78.12 62.663 ;
        RECT  72.6 2.137 72.72 62.663 ;
        RECT  67.2 2.137 67.32 62.663 ;
        RECT  61.8 2.137 61.92 62.663 ;
        RECT  56.4 2.137 56.52 62.663 ;
        RECT  51 2.137 51.12 62.663 ;
        RECT  45.6 2.137 45.72 62.663 ;
        RECT  40.2 2.137 40.32 62.663 ;
        RECT  34.8 2.137 34.92 62.663 ;
        RECT  29.4 2.137 29.52 62.663 ;
        RECT  24 2.137 24.12 62.663 ;
        RECT  18.6 2.137 18.72 62.663 ;
        RECT  13.2 2.137 13.32 62.663 ;
        RECT  7.8 2.137 7.92 62.663 ;
        RECT  2.4 2.137 2.52 62.663 ;
    END
  END VSS
  # OT_OBS_CLOSED layer=M5 d_um=1.536 added=485
  OBS
    LAYER RVTN ;
     RECT  2.16 2.16 84.24 2.295 ;
     RECT  2.16 2.565 84.24 2.835 ;
     RECT  2.16 3.105 84.24 3.375 ;
     RECT  2.16 3.645 84.24 3.915 ;
     RECT  2.16 4.185 84.24 4.455 ;
     RECT  2.16 4.725 84.24 4.995 ;
     RECT  2.16 5.265 84.24 5.535 ;
     RECT  2.16 5.805 84.24 6.075 ;
     RECT  2.16 6.345 84.24 6.615 ;
     RECT  2.16 6.885 84.24 7.155 ;
     RECT  2.16 7.425 84.24 7.695 ;
     RECT  2.16 7.965 84.24 8.235 ;
     RECT  2.16 8.505 84.24 8.775 ;
     RECT  2.16 9.045 84.24 9.315 ;
     RECT  2.16 9.585 84.24 9.855 ;
     RECT  2.16 10.125 84.24 10.395 ;
     RECT  2.16 10.665 84.24 10.935 ;
     RECT  2.16 11.205 84.24 11.475 ;
     RECT  2.16 11.745 84.24 12.015 ;
     RECT  2.16 12.285 84.24 12.555 ;
     RECT  2.16 12.825 84.24 13.095 ;
     RECT  2.16 13.365 84.24 13.635 ;
     RECT  2.16 13.905 84.24 14.175 ;
     RECT  2.16 14.445 84.24 14.715 ;
     RECT  2.16 14.985 84.24 15.255 ;
     RECT  2.16 15.525 84.24 15.795 ;
     RECT  2.16 16.065 84.24 16.335 ;
     RECT  2.16 16.605 84.24 16.875 ;
     RECT  2.16 17.145 84.24 17.415 ;
     RECT  2.16 17.685 84.24 17.955 ;
     RECT  2.16 18.225 84.24 18.495 ;
     RECT  2.16 18.765 84.24 19.035 ;
     RECT  2.16 19.305 84.24 19.575 ;
     RECT  2.16 19.845 84.24 20.115 ;
     RECT  2.16 20.385 84.24 20.655 ;
     RECT  2.16 20.925 84.24 21.195 ;
     RECT  2.16 21.465 84.24 21.735 ;
     RECT  2.16 22.005 84.24 22.275 ;
     RECT  2.16 22.545 84.24 22.815 ;
     RECT  2.16 23.085 84.24 23.355 ;
     RECT  2.16 23.625 84.24 23.895 ;
     RECT  2.16 24.165 84.24 24.435 ;
     RECT  2.16 24.705 84.24 24.975 ;
     RECT  2.16 25.245 84.24 25.515 ;
     RECT  2.16 25.785 84.24 26.055 ;
     RECT  2.16 26.325 84.24 26.595 ;
     RECT  2.16 26.865 84.24 27.135 ;
     RECT  2.16 27.405 84.24 27.675 ;
     RECT  2.16 27.945 84.24 28.215 ;
     RECT  2.16 28.485 84.24 28.755 ;
     RECT  2.16 29.025 84.24 29.295 ;
     RECT  2.16 29.565 84.24 29.835 ;
     RECT  2.16 30.105 84.24 30.375 ;
     RECT  2.16 30.645 84.24 30.915 ;
     RECT  2.16 31.185 84.24 31.455 ;
     RECT  2.16 31.725 84.24 31.995 ;
     RECT  2.16 32.265 84.24 32.535 ;
     RECT  2.16 32.805 84.24 33.075 ;
     RECT  2.16 33.345 84.24 33.615 ;
     RECT  2.16 33.885 84.24 34.155 ;
     RECT  2.16 34.425 84.24 34.695 ;
     RECT  2.16 34.965 84.24 35.235 ;
     RECT  2.16 35.505 84.24 35.775 ;
     RECT  2.16 36.045 84.24 36.315 ;
     RECT  2.16 36.585 84.24 36.855 ;
     RECT  2.16 37.125 84.24 37.395 ;
     RECT  2.16 37.665 84.24 37.935 ;
     RECT  2.16 38.205 84.24 38.475 ;
     RECT  2.16 38.745 84.24 39.015 ;
     RECT  2.16 39.285 84.24 39.555 ;
     RECT  2.16 39.825 84.24 40.095 ;
     RECT  2.16 40.365 84.24 40.635 ;
     RECT  2.16 40.905 84.24 41.175 ;
     RECT  2.16 41.445 84.24 41.715 ;
     RECT  2.16 41.985 84.24 42.255 ;
     RECT  2.16 42.525 84.24 42.795 ;
     RECT  2.16 43.065 84.24 43.335 ;
     RECT  2.16 43.605 84.24 43.875 ;
     RECT  2.16 44.145 84.24 44.415 ;
     RECT  2.16 44.685 84.24 44.955 ;
     RECT  2.16 45.225 84.24 45.495 ;
     RECT  2.16 45.765 84.24 46.035 ;
     RECT  2.16 46.305 84.24 46.575 ;
     RECT  2.16 46.845 84.24 47.115 ;
     RECT  2.16 47.385 84.24 47.655 ;
     RECT  2.16 47.925 84.24 48.195 ;
     RECT  2.16 48.465 84.24 48.735 ;
     RECT  2.16 49.005 84.24 49.275 ;
     RECT  2.16 49.545 84.24 49.815 ;
     RECT  2.16 50.085 84.24 50.355 ;
     RECT  2.16 50.625 84.24 50.895 ;
     RECT  2.16 51.165 84.24 51.435 ;
     RECT  2.16 51.705 84.24 51.975 ;
     RECT  2.16 52.245 84.24 52.515 ;
     RECT  2.16 52.785 84.24 53.055 ;
     RECT  2.16 53.325 84.24 53.595 ;
     RECT  2.16 53.865 84.24 54.135 ;
     RECT  2.16 54.405 84.24 54.675 ;
     RECT  2.16 54.945 84.24 55.215 ;
     RECT  2.16 55.485 84.24 55.755 ;
     RECT  2.16 56.025 84.24 56.295 ;
     RECT  2.16 56.565 84.24 56.835 ;
     RECT  2.16 57.105 84.24 57.375 ;
     RECT  2.16 57.645 84.24 57.915 ;
     RECT  2.16 58.185 84.24 58.455 ;
     RECT  2.16 58.725 84.24 58.995 ;
     RECT  2.16 59.265 84.24 59.535 ;
     RECT  2.16 59.805 84.24 60.075 ;
     RECT  2.16 60.345 84.24 60.615 ;
     RECT  2.16 60.885 84.24 61.155 ;
     RECT  2.16 61.425 84.24 61.695 ;
     RECT  2.16 61.965 84.24 62.235 ;
     RECT  2.16 62.505 84.24 62.64 ;
    LAYER RVTP ;
     RECT  2.16 2.295 84.24 2.565 ;
     RECT  2.16 2.835 84.24 3.105 ;
     RECT  2.16 3.375 84.24 3.645 ;
     RECT  2.16 3.915 84.24 4.185 ;
     RECT  2.16 4.455 84.24 4.725 ;
     RECT  2.16 4.995 84.24 5.265 ;
     RECT  2.16 5.535 84.24 5.805 ;
     RECT  2.16 6.075 84.24 6.345 ;
     RECT  2.16 6.615 84.24 6.885 ;
     RECT  2.16 7.155 84.24 7.425 ;
     RECT  2.16 7.695 84.24 7.965 ;
     RECT  2.16 8.235 84.24 8.505 ;
     RECT  2.16 8.775 84.24 9.045 ;
     RECT  2.16 9.315 84.24 9.585 ;
     RECT  2.16 9.855 84.24 10.125 ;
     RECT  2.16 10.395 84.24 10.665 ;
     RECT  2.16 10.935 84.24 11.205 ;
     RECT  2.16 11.475 84.24 11.745 ;
     RECT  2.16 12.015 84.24 12.285 ;
     RECT  2.16 12.555 84.24 12.825 ;
     RECT  2.16 13.095 84.24 13.365 ;
     RECT  2.16 13.635 84.24 13.905 ;
     RECT  2.16 14.175 84.24 14.445 ;
     RECT  2.16 14.715 84.24 14.985 ;
     RECT  2.16 15.255 84.24 15.525 ;
     RECT  2.16 15.795 84.24 16.065 ;
     RECT  2.16 16.335 84.24 16.605 ;
     RECT  2.16 16.875 84.24 17.145 ;
     RECT  2.16 17.415 84.24 17.685 ;
     RECT  2.16 17.955 84.24 18.225 ;
     RECT  2.16 18.495 84.24 18.765 ;
     RECT  2.16 19.035 84.24 19.305 ;
     RECT  2.16 19.575 84.24 19.845 ;
     RECT  2.16 20.115 84.24 20.385 ;
     RECT  2.16 20.655 84.24 20.925 ;
     RECT  2.16 21.195 84.24 21.465 ;
     RECT  2.16 21.735 84.24 22.005 ;
     RECT  2.16 22.275 84.24 22.545 ;
     RECT  2.16 22.815 84.24 23.085 ;
     RECT  2.16 23.355 84.24 23.625 ;
     RECT  2.16 23.895 84.24 24.165 ;
     RECT  2.16 24.435 84.24 24.705 ;
     RECT  2.16 24.975 84.24 25.245 ;
     RECT  2.16 25.515 84.24 25.785 ;
     RECT  2.16 26.055 84.24 26.325 ;
     RECT  2.16 26.595 84.24 26.865 ;
     RECT  2.16 27.135 84.24 27.405 ;
     RECT  2.16 27.675 84.24 27.945 ;
     RECT  2.16 28.215 84.24 28.485 ;
     RECT  2.16 28.755 84.24 29.025 ;
     RECT  2.16 29.295 84.24 29.565 ;
     RECT  2.16 29.835 84.24 30.105 ;
     RECT  2.16 30.375 84.24 30.645 ;
     RECT  2.16 30.915 84.24 31.185 ;
     RECT  2.16 31.455 84.24 31.725 ;
     RECT  2.16 31.995 84.24 32.265 ;
     RECT  2.16 32.535 84.24 32.805 ;
     RECT  2.16 33.075 84.24 33.345 ;
     RECT  2.16 33.615 84.24 33.885 ;
     RECT  2.16 34.155 84.24 34.425 ;
     RECT  2.16 34.695 84.24 34.965 ;
     RECT  2.16 35.235 84.24 35.505 ;
     RECT  2.16 35.775 84.24 36.045 ;
     RECT  2.16 36.315 84.24 36.585 ;
     RECT  2.16 36.855 84.24 37.125 ;
     RECT  2.16 37.395 84.24 37.665 ;
     RECT  2.16 37.935 84.24 38.205 ;
     RECT  2.16 38.475 84.24 38.745 ;
     RECT  2.16 39.015 84.24 39.285 ;
     RECT  2.16 39.555 84.24 39.825 ;
     RECT  2.16 40.095 84.24 40.365 ;
     RECT  2.16 40.635 84.24 40.905 ;
     RECT  2.16 41.175 84.24 41.445 ;
     RECT  2.16 41.715 84.24 41.985 ;
     RECT  2.16 42.255 84.24 42.525 ;
     RECT  2.16 42.795 84.24 43.065 ;
     RECT  2.16 43.335 84.24 43.605 ;
     RECT  2.16 43.875 84.24 44.145 ;
     RECT  2.16 44.415 84.24 44.685 ;
     RECT  2.16 44.955 84.24 45.225 ;
     RECT  2.16 45.495 84.24 45.765 ;
     RECT  2.16 46.035 84.24 46.305 ;
     RECT  2.16 46.575 84.24 46.845 ;
     RECT  2.16 47.115 84.24 47.385 ;
     RECT  2.16 47.655 84.24 47.925 ;
     RECT  2.16 48.195 84.24 48.465 ;
     RECT  2.16 48.735 84.24 49.005 ;
     RECT  2.16 49.275 84.24 49.545 ;
     RECT  2.16 49.815 84.24 50.085 ;
     RECT  2.16 50.355 84.24 50.625 ;
     RECT  2.16 50.895 84.24 51.165 ;
     RECT  2.16 51.435 84.24 51.705 ;
     RECT  2.16 51.975 84.24 52.245 ;
     RECT  2.16 52.515 84.24 52.785 ;
     RECT  2.16 53.055 84.24 53.325 ;
     RECT  2.16 53.595 84.24 53.865 ;
     RECT  2.16 54.135 84.24 54.405 ;
     RECT  2.16 54.675 84.24 54.945 ;
     RECT  2.16 55.215 84.24 55.485 ;
     RECT  2.16 55.755 84.24 56.025 ;
     RECT  2.16 56.295 84.24 56.565 ;
     RECT  2.16 56.835 84.24 57.105 ;
     RECT  2.16 57.375 84.24 57.645 ;
     RECT  2.16 57.915 84.24 58.185 ;
     RECT  2.16 58.455 84.24 58.725 ;
     RECT  2.16 58.995 84.24 59.265 ;
     RECT  2.16 59.535 84.24 59.805 ;
     RECT  2.16 60.075 84.24 60.345 ;
     RECT  2.16 60.615 84.24 60.885 ;
     RECT  2.16 61.155 84.24 61.425 ;
     RECT  2.16 61.695 84.24 61.965 ;
     RECT  2.16 62.235 84.24 62.505 ;
    LAYER M1 ;
     RECT  2.16 2.151 84.24 62.649 ;
    LAYER M2 ;
     RECT  1.975 6.696 2.047 6.714 ;
     RECT  2.047 13.446 2.083 13.464 ;
     RECT  2.047 6.426 2.119 6.714 ;
     RECT  2.083 12.906 2.119 13.464 ;
     RECT  2.119 6.156 2.155 6.714 ;
     RECT  2.119 12.87 2.155 13.464 ;
     RECT  2.011 3.186 2.16 3.204 ;
     RECT  2.155 5.616 2.16 6.714 ;
     RECT  2.083 7.506 2.16 7.524 ;
     RECT  1.975 10.296 2.16 10.314 ;
     RECT  2.155 12.87 2.16 13.86 ;
     RECT  2.011 16.848 2.16 16.866 ;
     RECT  0.103 25.02 2.16 25.038 ;
     RECT  2.16 2.151 2.299 62.649 ;
     RECT  2.263 0.108 2.947 0.126 ;
     RECT  2.299 2.106 3.011 62.649 ;
     RECT  2.947 0.036 3.083 0.126 ;
     RECT  3.083 0.108 3.811 0.126 ;
     RECT  3.811 0.036 4.135 0.126 ;
     RECT  4.459 1.152 4.559 1.17 ;
     RECT  4.135 0.036 4.595 0.234 ;
     RECT  4.595 0.036 4.667 0.126 ;
     RECT  4.667 0.108 4.739 0.126 ;
     RECT  3.011 2.151 5.143 62.649 ;
     RECT  5.143 2.106 6.215 62.649 ;
     RECT  5.539 0.108 6.295 0.126 ;
     RECT  6.295 0.036 6.395 0.234 ;
     RECT  6.395 0.036 6.719 0.198 ;
     RECT  6.719 0.036 7.403 0.09 ;
     RECT  6.215 2.151 7.555 62.649 ;
     RECT  7.403 0.036 7.763 0.054 ;
     RECT  7.555 2.034 8.231 62.649 ;
     RECT  8.231 2.106 8.879 62.649 ;
     RECT  12.559 1.152 12.695 1.17 ;
     RECT  8.879 2.151 13.711 62.649 ;
     RECT  13.711 1.656 13.811 62.649 ;
     RECT  13.811 2.106 14.819 62.649 ;
     RECT  16.987 1.152 17.087 1.17 ;
     RECT  14.819 2.151 17.203 62.649 ;
     RECT  17.203 2.106 19.967 62.649 ;
     RECT  19.967 2.151 22.963 62.649 ;
     RECT  22.963 2.106 23.071 62.649 ;
     RECT  23.071 2.034 23.971 62.649 ;
     RECT  23.971 1.728 24.251 62.649 ;
     RECT  23.791 0.18 24.295 0.198 ;
     RECT  24.295 0.108 24.331 0.198 ;
     RECT  24.251 2.106 24.547 62.649 ;
     RECT  24.331 0.036 24.611 0.198 ;
     RECT  24.611 0.036 24.971 0.126 ;
     RECT  25.087 1.152 25.223 1.17 ;
     RECT  24.971 0.036 25.259 0.054 ;
     RECT  24.547 2.106 25.735 62.694 ;
     RECT  26.095 0.036 26.375 0.054 ;
     RECT  25.735 1.728 26.627 62.694 ;
     RECT  26.627 2.106 26.915 62.694 ;
     RECT  26.915 2.106 27.491 62.649 ;
     RECT  27.491 2.151 28.543 62.649 ;
     RECT  29.047 0.036 29.083 0.054 ;
     RECT  28.543 2.106 29.119 62.649 ;
     RECT  29.119 2.07 29.155 62.649 ;
     RECT  29.155 1.998 29.651 62.649 ;
     RECT  29.695 1.152 29.795 1.17 ;
     RECT  29.083 0.036 29.867 0.126 ;
     RECT  29.867 0.036 30.119 0.054 ;
     RECT  29.651 2.151 31.099 62.649 ;
     RECT  31.099 2.106 31.415 62.649 ;
     RECT  31.415 2.151 35.599 62.649 ;
     RECT  35.599 2.106 35.635 62.649 ;
     RECT  35.635 2.07 36.239 62.649 ;
     RECT  36.239 2.106 36.743 62.649 ;
     RECT  36.743 2.151 42.079 62.649 ;
     RECT  42.079 2.106 43.771 62.649 ;
     RECT  43.771 2.034 44.267 62.649 ;
     RECT  44.267 2.106 45.175 62.649 ;
     RECT  45.175 2.034 50.503 62.649 ;
     RECT  50.791 0.576 51.295 0.594 ;
     RECT  51.295 0.108 51.367 0.594 ;
     RECT  51.367 0.036 51.575 0.594 ;
     RECT  50.503 1.728 51.611 62.649 ;
     RECT  51.575 0.108 51.647 0.594 ;
     RECT  51.647 0.18 52.295 0.594 ;
     RECT  52.295 0.18 52.447 0.198 ;
     RECT  52.447 0.036 52.511 0.198 ;
     RECT  51.611 2.151 52.699 62.649 ;
     RECT  52.511 0.18 52.799 0.198 ;
     RECT  52.699 2.106 53.159 62.649 ;
     RECT  53.095 1.224 53.167 1.242 ;
     RECT  53.347 0.036 53.635 0.126 ;
     RECT  53.167 1.152 53.635 1.242 ;
     RECT  53.635 0.036 53.915 1.242 ;
     RECT  53.159 2.151 54.607 62.649 ;
     RECT  53.915 0.036 54.707 0.594 ;
     RECT  54.607 1.728 55.031 62.649 ;
     RECT  54.707 0.036 55.427 0.279 ;
     RECT  55.031 2.106 55.867 62.649 ;
     RECT  55.427 0.036 56.075 0.054 ;
     RECT  55.867 1.728 56.695 62.649 ;
     RECT  56.695 1.224 56.767 62.649 ;
     RECT  56.767 1.152 57.011 62.649 ;
     RECT  57.011 1.728 57.191 62.649 ;
     RECT  57.191 1.8 57.227 62.649 ;
     RECT  56.875 0.036 57.271 0.054 ;
     RECT  57.271 0.036 57.479 0.549 ;
     RECT  57.479 0.531 58.279 0.549 ;
     RECT  58.279 0.108 58.351 0.549 ;
     RECT  58.351 0.036 58.847 0.549 ;
     RECT  58.847 0.036 58.919 0.504 ;
     RECT  58.919 0.036 59.459 0.234 ;
     RECT  57.227 2.151 59.971 62.649 ;
     RECT  59.459 0.036 60.035 0.126 ;
     RECT  59.971 1.728 60.431 62.649 ;
     RECT  60.431 2.151 62.239 62.649 ;
     RECT  62.239 2.106 65.291 62.649 ;
     RECT  65.291 2.151 66.271 62.649 ;
     RECT  66.271 2.034 66.883 62.649 ;
     RECT  66.883 1.962 67.567 62.649 ;
     RECT  67.567 1.926 69.035 62.649 ;
     RECT  69.035 1.998 71.375 62.649 ;
     RECT  71.375 2.034 72.427 62.649 ;
     RECT  72.427 1.962 73.463 62.649 ;
     RECT  73.463 2.106 74.659 62.649 ;
     RECT  73.507 0.18 75.091 0.198 ;
     RECT  74.659 1.728 75.091 62.649 ;
     RECT  75.091 1.152 75.191 62.649 ;
     RECT  75.191 1.728 75.515 62.649 ;
     RECT  75.091 0.036 75.703 0.198 ;
     RECT  75.703 0.036 75.803 0.279 ;
     RECT  75.803 0.036 76.271 0.198 ;
     RECT  76.271 0.108 76.559 0.198 ;
     RECT  76.559 0.18 77.171 0.198 ;
     RECT  75.515 2.106 77.755 62.649 ;
     RECT  77.755 1.728 77.963 62.649 ;
     RECT  77.611 0.036 78.295 0.054 ;
     RECT  78.295 0.036 78.727 0.126 ;
     RECT  78.727 0.036 78.799 0.162 ;
     RECT  78.799 0.036 79.231 0.198 ;
     RECT  77.963 2.151 79.267 62.649 ;
     RECT  79.231 0.036 79.331 0.234 ;
     RECT  79.331 0.036 79.439 0.09 ;
     RECT  79.439 0.036 79.511 0.054 ;
     RECT  79.267 2.106 79.807 62.649 ;
     RECT  79.807 2.034 81.311 62.649 ;
     RECT  81.311 2.106 82.391 62.649 ;
     RECT  82.391 2.151 84.24 62.649 ;
    LAYER M3 ;
     RECT  2.844 0.012 7.398 0.031 ;
     RECT  29.34 0.012 29.862 0.031 ;
     RECT  74.844 0.012 79.398 0.031 ;
     RECT  2.844 0.031 7.758 0.103 ;
     RECT  12.24 0.091 12.258 0.139 ;
     RECT  18.396 0.091 18.774 0.139 ;
     RECT  48.06 0.091 48.078 0.139 ;
     RECT  24.156 0.012 26.406 0.175 ;
     RECT  17.532 0.139 17.55 0.187 ;
     RECT  18.288 0.139 18.774 0.187 ;
     RECT  47.916 0.139 48.078 0.187 ;
     RECT  49.248 0.091 49.266 0.379 ;
     RECT  50.652 0.012 60.39 0.379 ;
     RECT  47.916 0.187 48.402 0.427 ;
     RECT  47.772 0.427 48.402 0.475 ;
     RECT  49.248 0.379 60.39 0.475 ;
     RECT  11.016 0.091 11.034 0.523 ;
     RECT  11.844 0.139 12.258 0.523 ;
     RECT  13.788 0.091 13.806 0.523 ;
     RECT  15.3 0.427 15.318 0.523 ;
     RECT  17.532 0.187 18.774 0.523 ;
     RECT  68.328 0.091 68.922 0.523 ;
     RECT  10.8 0.523 11.034 0.571 ;
     RECT  11.844 0.523 12.582 0.571 ;
     RECT  13.356 0.523 13.806 0.571 ;
     RECT  15.264 0.523 15.318 0.571 ;
     RECT  67.86 0.523 68.922 0.571 ;
     RECT  9.9 0.571 11.034 1.099 ;
     RECT  67.536 0.571 68.922 1.099 ;
     RECT  15.264 0.571 16.002 1.147 ;
     RECT  9.54 1.099 11.034 1.723 ;
     RECT  11.844 0.571 13.806 1.723 ;
     RECT  14.832 1.147 16.002 1.723 ;
     RECT  16.92 0.523 18.774 1.723 ;
     RECT  23.796 0.175 26.406 1.723 ;
     RECT  47.772 0.475 60.39 1.723 ;
     RECT  66.708 0.619 66.726 1.723 ;
     RECT  67.536 1.099 69.066 1.723 ;
     RECT  70.128 0.571 70.146 1.723 ;
     RECT  74.844 0.031 79.506 1.723 ;
     RECT  9.54 1.723 19.062 1.771 ;
     RECT  73.512 0.175 73.53 1.957 ;
     RECT  2.268 0.103 7.758 2.029 ;
     RECT  23.796 1.723 26.622 2.029 ;
     RECT  66.708 1.723 70.542 2.029 ;
     RECT  72.432 1.957 72.45 2.029 ;
     RECT  74.664 1.723 79.506 2.029 ;
     RECT  2.268 2.029 8.226 2.101 ;
     RECT  9.54 1.771 19.134 2.101 ;
     RECT  20.592 0.091 20.61 2.101 ;
     RECT  23.076 2.029 26.622 2.101 ;
     RECT  29.052 0.031 30.114 2.101 ;
     RECT  35.64 2.065 36.234 2.101 ;
     RECT  47.772 1.723 60.426 2.101 ;
     RECT  71.352 1.993 71.37 2.101 ;
     RECT  72.432 2.029 72.594 2.101 ;
     RECT  73.44 1.957 73.53 2.101 ;
     RECT  81.288 2.029 81.306 2.101 ;
     RECT  35.604 2.101 36.738 2.143 ;
     RECT  45.18 2.029 45.198 2.143 ;
     RECT  62.244 2.101 63.27 2.143 ;
     RECT  2.268 2.101 19.134 2.191 ;
     RECT  19.944 2.101 20.61 2.191 ;
     RECT  22.968 2.101 26.622 2.191 ;
     RECT  27.468 2.101 27.486 2.191 ;
     RECT  28.548 2.101 30.114 2.191 ;
     RECT  31.104 2.101 31.41 2.191 ;
     RECT  47.052 2.101 60.426 2.191 ;
     RECT  61.815 2.143 63.27 2.191 ;
     RECT  71.352 2.101 73.602 2.191 ;
     RECT  74.664 2.029 79.83 2.191 ;
     RECT  80.892 2.101 81.306 2.191 ;
     RECT  30.996 2.191 31.41 2.227 ;
     RECT  40.215 2.143 40.305 2.227 ;
     RECT  41.256 2.191 41.274 2.227 ;
     RECT  45.18 2.143 45.705 2.227 ;
     RECT  46.656 2.191 60.426 2.227 ;
     RECT  61.815 2.191 63.594 2.227 ;
     RECT  66.276 2.029 70.542 2.227 ;
     RECT  2.268 2.191 20.61 2.263 ;
     RECT  22.068 2.191 22.086 2.263 ;
     RECT  40.215 2.227 41.274 2.263 ;
     RECT  42.084 2.101 42.102 2.263 ;
     RECT  43.776 2.029 44.262 2.263 ;
     RECT  45.18 2.227 60.426 2.263 ;
     RECT  65.268 2.101 65.286 2.263 ;
     RECT  65.052 2.263 65.322 2.293 ;
     RECT  32.508 2.191 32.526 2.299 ;
     RECT  34.815 2.143 36.738 2.299 ;
     RECT  45.036 2.263 60.426 2.299 ;
     RECT  61.272 2.227 63.594 2.299 ;
     RECT  64.98 2.293 65.322 2.299 ;
     RECT  66.276 2.227 70.614 2.299 ;
     RECT  2.268 2.263 22.194 2.335 ;
     RECT  22.968 2.191 27.486 2.335 ;
     RECT  28.26 2.191 30.15 2.335 ;
     RECT  30.996 2.227 31.482 2.335 ;
     RECT  32.508 2.299 33.282 2.335 ;
     RECT  40.215 2.263 42.102 2.335 ;
     RECT  43.668 2.263 44.262 2.335 ;
     RECT  45.036 2.299 63.594 2.335 ;
     RECT  2.268 2.335 27.486 2.371 ;
     RECT  32.508 2.335 33.354 2.371 ;
     RECT  34.632 2.299 36.738 2.371 ;
     RECT  39.276 2.299 39.294 2.371 ;
     RECT  40.215 2.335 42.21 2.371 ;
     RECT  45.036 2.335 63.846 2.371 ;
     RECT  64.98 2.299 70.614 2.371 ;
     RECT  71.352 2.191 81.414 2.371 ;
     RECT  82.368 2.101 82.386 2.371 ;
     RECT  83.415 2.143 83.505 2.371 ;
     RECT  71.352 2.371 83.505 2.413 ;
     RECT  45.036 2.371 70.614 2.461 ;
     RECT  71.352 2.413 83.697 2.461 ;
     RECT  32.508 2.371 33.462 2.497 ;
     RECT  34.632 2.371 36.918 2.497 ;
     RECT  39.276 2.371 42.21 2.497 ;
     RECT  42.948 2.335 44.262 2.497 ;
     RECT  39.276 2.497 44.262 2.533 ;
     RECT  39.168 2.533 44.262 2.569 ;
     RECT  45.036 2.461 83.697 2.569 ;
     RECT  32.508 2.497 36.918 2.605 ;
     RECT  28.26 2.335 31.482 2.641 ;
     RECT  28.26 2.641 31.626 2.759 ;
     RECT  2.196 2.371 27.486 2.767 ;
     RECT  28.26 2.759 31.554 2.767 ;
     RECT  32.508 2.605 37.35 2.827 ;
     RECT  38.16 2.641 38.178 2.827 ;
     RECT  32.508 2.827 38.178 2.861 ;
     RECT  32.508 2.861 36.846 3.173 ;
     RECT  2.196 2.767 31.554 3.181 ;
     RECT  37.62 2.861 38.178 3.271 ;
     RECT  39.132 2.569 83.697 3.271 ;
     RECT  32.76 3.173 36.846 3.407 ;
     RECT  32.76 3.407 36.81 3.443 ;
     RECT  37.62 3.271 83.697 3.721 ;
     RECT  37.62 3.721 83.754 3.749 ;
     RECT  37.62 3.749 37.638 4.109 ;
     RECT  32.832 3.443 36.81 4.225 ;
     RECT  32.832 4.225 36.882 4.261 ;
     RECT  2.016 3.181 31.554 4.531 ;
     RECT  32.832 4.261 37.566 4.531 ;
     RECT  2.016 4.531 37.566 5.161 ;
     RECT  38.412 3.749 83.754 5.161 ;
     RECT  2.016 5.161 83.754 5.611 ;
     RECT  2.016 5.611 83.79 6.305 ;
     RECT  2.016 6.305 83.754 6.691 ;
     RECT  1.98 6.691 83.754 7.501 ;
     RECT  1.98 7.501 83.79 8.033 ;
     RECT  1.98 8.033 32.922 8.851 ;
     RECT  33.696 8.033 83.79 8.851 ;
     RECT  1.98 8.851 83.79 10.319 ;
     RECT  2.016 10.319 83.79 11.435 ;
     RECT  34.092 11.435 83.79 11.821 ;
     RECT  34.092 11.821 84.114 11.885 ;
     RECT  2.016 11.435 33.282 12.181 ;
     RECT  34.092 11.885 83.898 12.181 ;
     RECT  2.016 12.181 83.898 12.365 ;
     RECT  34.128 12.365 83.898 12.515 ;
     RECT  2.016 12.365 33.354 13.099 ;
     RECT  34.128 12.515 83.862 13.099 ;
     RECT  2.016 13.099 83.862 13.829 ;
     RECT  2.016 13.829 33.426 13.865 ;
     RECT  2.016 13.865 33.354 14.611 ;
     RECT  34.164 13.829 83.862 14.611 ;
     RECT  2.016 14.611 83.862 15.403 ;
     RECT  2.016 15.403 83.898 15.835 ;
     RECT  2.016 15.835 84.042 15.899 ;
     RECT  2.016 15.899 83.97 16.871 ;
     RECT  2.268 16.871 83.97 19.111 ;
     RECT  2.268 19.111 84.114 19.229 ;
     RECT  2.268 19.229 84.006 19.235 ;
     RECT  2.268 19.235 44.082 19.963 ;
     RECT  44.82 19.235 84.006 19.963 ;
     RECT  2.268 19.963 84.006 22.621 ;
     RECT  2.268 22.621 84.114 24.701 ;
     RECT  0.108 25.015 0.126 25.421 ;
     RECT  2.268 24.701 84.006 25.861 ;
     RECT  2.268 25.861 84.114 26.429 ;
     RECT  2.268 26.429 83.898 27.167 ;
     RECT  77.544 27.167 83.898 27.481 ;
     RECT  77.544 27.481 84.042 27.599 ;
     RECT  77.58 27.599 84.042 27.751 ;
     RECT  77.58 27.751 84.114 27.869 ;
     RECT  2.268 27.167 76.77 27.905 ;
     RECT  16.2 27.905 76.77 28.291 ;
     RECT  16.2 28.291 76.842 28.502 ;
     RECT  77.58 27.869 83.934 28.502 ;
     RECT  2.268 27.905 15.426 28.831 ;
     RECT  16.2 28.502 83.934 28.831 ;
     RECT  2.268 28.831 83.934 30.029 ;
     RECT  2.268 30.029 17.658 30.269 ;
     RECT  18.54 30.029 83.934 30.749 ;
     RECT  18.54 30.749 83.79 31.387 ;
     RECT  2.268 30.269 17.622 31.487 ;
     RECT  18.468 31.387 83.79 31.801 ;
     RECT  2.34 31.487 17.622 31.963 ;
     RECT  18.468 31.801 83.898 31.963 ;
     RECT  2.34 31.963 83.898 32.341 ;
     RECT  2.34 32.341 84.114 32.459 ;
     RECT  2.34 32.459 83.754 33.925 ;
     RECT  2.34 33.925 83.862 34.079 ;
     RECT  2.34 34.079 83.754 34.159 ;
     RECT  2.304 34.159 83.754 35.005 ;
     RECT  2.304 35.005 83.934 35.159 ;
     RECT  2.304 35.159 83.79 35.573 ;
     RECT  2.304 35.573 83.754 37.021 ;
     RECT  2.304 37.021 83.79 37.705 ;
     RECT  2.304 37.705 83.934 37.859 ;
     RECT  2.304 37.859 83.862 38.669 ;
     RECT  2.304 38.669 83.79 39.487 ;
     RECT  2.304 39.487 83.934 39.515 ;
     RECT  7.524 39.515 83.934 40.405 ;
     RECT  2.304 39.515 6.786 40.531 ;
     RECT  7.524 40.405 84.114 40.531 ;
     RECT  2.304 40.531 84.114 41.369 ;
     RECT  2.304 41.369 83.898 43.169 ;
     RECT  2.376 43.169 83.898 44.447 ;
     RECT  75.888 44.447 83.898 44.717 ;
     RECT  2.376 44.447 75.15 45.149 ;
     RECT  2.415 45.149 75.15 45.595 ;
     RECT  76.032 44.717 83.898 45.595 ;
     RECT  2.415 45.595 83.898 45.661 ;
     RECT  2.415 45.661 83.97 46.229 ;
     RECT  2.415 46.229 83.898 47.191 ;
     RECT  2.376 47.191 83.898 47.551 ;
     RECT  2.376 47.551 83.97 47.723 ;
     RECT  74.844 47.723 83.97 47.741 ;
     RECT  2.376 47.723 74.106 47.849 ;
     RECT  74.88 47.741 83.97 47.993 ;
     RECT  2.376 47.849 74.07 48.775 ;
     RECT  74.988 47.993 83.97 48.775 ;
     RECT  2.376 48.775 83.97 48.929 ;
     RECT  2.415 48.929 83.97 50.161 ;
     RECT  2.415 50.161 84.042 50.315 ;
     RECT  2.415 50.315 83.97 50.395 ;
     RECT  2.34 50.395 83.97 50.999 ;
     RECT  2.376 50.999 83.97 52.285 ;
     RECT  2.376 52.285 84.114 52.439 ;
     RECT  2.415 52.439 83.97 53.401 ;
     RECT  2.376 53.401 83.97 54.059 ;
     RECT  2.415 54.059 83.97 54.481 ;
     RECT  2.415 54.481 84.042 54.869 ;
     RECT  2.415 54.869 83.97 54.905 ;
     RECT  7.308 54.905 83.97 54.977 ;
     RECT  2.415 54.905 6.534 55.139 ;
     RECT  2.415 55.139 6.174 55.243 ;
     RECT  2.34 55.243 6.174 55.283 ;
     RECT  7.308 54.977 83.898 55.409 ;
     RECT  53.532 55.409 83.898 55.993 ;
     RECT  2.415 55.283 6.174 56.065 ;
     RECT  2.415 56.065 6.246 56.101 ;
     RECT  2.415 56.101 6.318 56.227 ;
     RECT  7.308 55.409 52.65 56.227 ;
     RECT  2.415 56.227 52.65 56.299 ;
     RECT  2.415 56.299 52.794 56.371 ;
     RECT  53.532 55.993 83.97 56.371 ;
     RECT  2.415 56.371 83.97 56.489 ;
     RECT  2.415 56.489 83.898 56.831 ;
     RECT  63.432 56.831 83.697 57.649 ;
     RECT  2.415 56.831 62.514 57.721 ;
     RECT  63.396 57.649 83.697 57.721 ;
     RECT  2.415 57.721 83.826 57.875 ;
     RECT  2.415 57.875 83.697 58.109 ;
     RECT  2.415 58.109 82.134 58.649 ;
     RECT  4.068 58.649 82.134 58.685 ;
     RECT  2.415 58.649 3.294 58.955 ;
     RECT  67.215 58.685 82.134 59.063 ;
     RECT  67.215 59.063 81.954 59.189 ;
     RECT  4.068 58.685 66.222 59.431 ;
     RECT  4.068 59.431 66.474 59.503 ;
     RECT  3.924 59.503 66.474 59.809 ;
     RECT  67.215 59.189 81.882 59.809 ;
     RECT  3.924 59.809 81.882 60.071 ;
     RECT  3.924 60.071 4.086 60.269 ;
     RECT  4.86 60.071 81.882 60.269 ;
     RECT  3.924 60.269 3.942 60.419 ;
     RECT  5.04 60.269 80.01 60.539 ;
     RECT  80.784 60.269 81.234 60.539 ;
     RECT  6.156 60.539 79.866 60.575 ;
     RECT  80.784 60.539 81.09 60.575 ;
     RECT  6.156 60.575 79.794 60.611 ;
     RECT  5.04 60.539 5.202 60.749 ;
     RECT  80.784 60.575 81.054 60.809 ;
     RECT  80.784 60.809 80.802 60.845 ;
     RECT  5.04 60.749 5.058 60.917 ;
     RECT  6.192 60.611 79.794 60.989 ;
     RECT  26.64 60.989 79.794 61.181 ;
     RECT  6.192 60.989 25.902 61.339 ;
     RECT  5.976 61.339 25.902 61.349 ;
     RECT  26.64 61.181 74.934 61.349 ;
     RECT  75.816 61.181 79.794 61.349 ;
     RECT  7.128 61.349 9.414 61.373 ;
     RECT  5.976 61.349 5.994 61.385 ;
     RECT  79.056 61.349 79.794 61.421 ;
     RECT  26.64 61.349 74.682 61.493 ;
     RECT  7.815 61.373 9.414 61.529 ;
     RECT  48.78 61.493 74.682 61.529 ;
     RECT  79.056 61.421 79.686 61.529 ;
     RECT  10.26 61.349 15.93 61.619 ;
     RECT  48.96 61.529 74.682 61.619 ;
     RECT  79.056 61.529 79.506 61.619 ;
     RECT  10.8 61.619 15.93 61.655 ;
     RECT  74.268 61.619 74.502 61.655 ;
     RECT  79.416 61.619 79.434 61.655 ;
     RECT  26.64 61.493 47.934 61.691 ;
     RECT  10.8 61.655 11.07 61.727 ;
     RECT  16.668 61.349 25.902 61.771 ;
     RECT  26.64 61.691 47.862 61.771 ;
     RECT  7.815 61.529 9.27 61.889 ;
     RECT  11.844 61.655 15.93 61.889 ;
     RECT  16.668 61.771 47.862 61.889 ;
     RECT  52.416 61.619 73.53 61.889 ;
     RECT  16.668 61.889 47.682 61.925 ;
     RECT  52.416 61.889 73.494 61.925 ;
     RECT  16.668 61.925 40.554 61.949 ;
     RECT  63.9 61.925 64.818 61.961 ;
     RECT  16.668 61.949 37.134 61.997 ;
     RECT  37.98 61.949 40.554 61.997 ;
     RECT  48.96 61.619 51.642 61.997 ;
     RECT  14.328 61.889 15.93 62.045 ;
     RECT  65.664 61.925 73.494 62.045 ;
     RECT  11.844 61.889 13.497 62.069 ;
     RECT  15.012 62.045 15.93 62.069 ;
     RECT  16.668 61.997 27.054 62.069 ;
     RECT  41.436 61.925 47.682 62.069 ;
     RECT  75.816 61.349 78.318 62.069 ;
     RECT  15.264 62.069 15.93 62.131 ;
     RECT  16.668 62.069 26.982 62.131 ;
     RECT  27.792 61.997 37.134 62.159 ;
     RECT  46.764 62.069 47.682 62.159 ;
     RECT  48.96 61.997 51.297 62.159 ;
     RECT  52.416 61.925 63.018 62.159 ;
     RECT  66.492 62.045 73.494 62.159 ;
     RECT  75.816 62.069 76.77 62.159 ;
     RECT  27.792 62.159 33.57 62.189 ;
     RECT  11.844 62.069 12.258 62.195 ;
     RECT  13.032 62.069 13.497 62.195 ;
     RECT  15.264 62.131 26.982 62.195 ;
     RECT  32.364 62.189 33.57 62.195 ;
     RECT  48.96 62.159 50.094 62.195 ;
     RECT  52.416 62.159 55.422 62.195 ;
     RECT  56.268 62.159 63.018 62.195 ;
     RECT  64.08 61.961 64.746 62.195 ;
     RECT  66.492 62.159 73.314 62.195 ;
     RECT  10.8 61.727 10.818 62.231 ;
     RECT  11.844 62.195 12.078 62.231 ;
     RECT  41.436 62.069 45.897 62.231 ;
     RECT  56.415 62.195 59.49 62.231 ;
     RECT  69.552 62.195 72.954 62.231 ;
     RECT  77.544 62.069 78.318 62.231 ;
     RECT  15.264 62.195 20.862 62.267 ;
     RECT  52.596 62.195 55.422 62.267 ;
     RECT  57.96 62.231 59.49 62.267 ;
     RECT  34.704 62.159 37.134 62.303 ;
     RECT  57.96 62.267 58.698 62.303 ;
     RECT  71.064 62.231 72.954 62.303 ;
     RECT  77.544 62.231 78.297 62.303 ;
     RECT  15.264 62.267 20.358 62.339 ;
     RECT  34.704 62.303 37.026 62.339 ;
     RECT  42.516 62.231 45.897 62.339 ;
     RECT  65.664 62.045 65.682 62.339 ;
     RECT  2.415 58.955 2.697 62.387 ;
     RECT  7.815 61.889 8.097 62.387 ;
     RECT  13.215 62.195 13.497 62.387 ;
     RECT  38.232 61.997 40.497 62.387 ;
     RECT  45.615 62.339 45.897 62.387 ;
     RECT  51.015 62.159 51.297 62.387 ;
     RECT  60.48 62.195 63.018 62.387 ;
     RECT  71.064 62.303 72.897 62.387 ;
     RECT  78.015 62.303 78.297 62.387 ;
     RECT  83.415 58.109 83.697 62.387 ;
     RECT  11.844 62.231 12.042 62.429 ;
     RECT  15.264 62.339 20.25 62.429 ;
     RECT  21.744 62.195 26.982 62.429 ;
     RECT  27.792 62.189 31.59 62.429 ;
     RECT  34.704 62.339 35.334 62.429 ;
     RECT  36.396 62.339 37.026 62.429 ;
     RECT  42.516 62.339 44.802 62.429 ;
     RECT  46.836 62.159 47.682 62.429 ;
     RECT  49.428 62.195 49.518 62.429 ;
     RECT  51.015 62.387 51.138 62.429 ;
     RECT  52.596 62.267 53.982 62.429 ;
     RECT  54.972 62.267 55.422 62.429 ;
     RECT  56.415 62.231 57.114 62.429 ;
     RECT  57.96 62.303 58.626 62.429 ;
     RECT  60.48 62.387 61.905 62.429 ;
     RECT  62.748 62.387 63.018 62.429 ;
     RECT  64.224 62.195 64.746 62.429 ;
     RECT  66.492 62.195 68.67 62.429 ;
     RECT  74.268 61.655 74.358 62.429 ;
     RECT  76.104 62.159 76.194 62.429 ;
     RECT  36.396 62.429 36.414 62.435 ;
     RECT  11.844 62.429 11.862 62.465 ;
     RECT  15.264 62.429 20.142 62.465 ;
     RECT  21.744 62.429 22.374 62.465 ;
     RECT  24.015 62.429 25.218 62.465 ;
     RECT  26.604 62.429 26.91 62.465 ;
     RECT  27.792 62.429 27.81 62.465 ;
     RECT  29.088 62.429 30.438 62.465 ;
     RECT  32.508 62.195 33.57 62.465 ;
     RECT  38.232 62.387 40.305 62.465 ;
     RECT  41.436 62.231 41.454 62.465 ;
     RECT  49.428 62.429 49.446 62.465 ;
     RECT  53.1 62.429 53.838 62.465 ;
     RECT  55.26 62.429 55.278 62.465 ;
     RECT  59.436 62.267 59.49 62.465 ;
     RECT  60.48 62.429 60.498 62.465 ;
     RECT  62.748 62.429 62.91 62.465 ;
     RECT  66.6 62.429 68.67 62.465 ;
     RECT  71.064 62.387 72.705 62.465 ;
     RECT  74.268 62.429 74.286 62.465 ;
     RECT  76.104 62.429 76.122 62.465 ;
     RECT  57.96 62.429 57.978 62.477 ;
     RECT  21.816 62.465 22.374 62.501 ;
     RECT  29.34 62.465 30.438 62.501 ;
     RECT  32.508 62.465 33.21 62.501 ;
     RECT  38.7 62.465 40.305 62.501 ;
     RECT  64.404 62.429 64.746 62.501 ;
     RECT  66.6 62.465 68.598 62.501 ;
     RECT  69.552 62.231 70.074 62.501 ;
     RECT  71.064 62.465 71.802 62.501 ;
     RECT  15.264 62.465 15.354 62.537 ;
     RECT  16.596 62.465 17.01 62.537 ;
     RECT  38.7 62.501 38.718 62.537 ;
     RECT  56.415 62.429 56.574 62.537 ;
     RECT  59.436 62.465 59.454 62.537 ;
     RECT  71.064 62.501 71.622 62.537 ;
     RECT  18.615 62.465 19.314 62.573 ;
     RECT  21.816 62.501 22.122 62.573 ;
     RECT  24.015 62.465 25.182 62.573 ;
     RECT  29.415 62.501 29.826 62.573 ;
     RECT  33.192 62.501 33.21 62.573 ;
     RECT  34.815 62.429 35.334 62.573 ;
     RECT  39.708 62.501 40.305 62.573 ;
     RECT  47.664 62.429 47.682 62.573 ;
     RECT  53.1 62.465 53.118 62.573 ;
     RECT  64.728 62.501 64.746 62.573 ;
     RECT  68.58 62.501 68.598 62.573 ;
     RECT  71.064 62.537 71.19 62.573 ;
     RECT  15.336 62.537 15.354 62.609 ;
     RECT  16.812 62.537 16.83 62.609 ;
     RECT  62.748 62.465 62.766 62.609 ;
     RECT  71.172 62.573 71.19 62.609 ;
     RECT  42.516 62.429 44.478 62.621 ;
     RECT  2.415 62.387 2.505 62.657 ;
     RECT  7.815 62.387 7.905 62.657 ;
     RECT  13.215 62.387 13.305 62.657 ;
     RECT  18.615 62.573 18.705 62.657 ;
     RECT  24.015 62.573 24.642 62.657 ;
     RECT  29.415 62.573 29.505 62.657 ;
     RECT  34.815 62.573 34.905 62.657 ;
     RECT  40.215 62.573 40.305 62.657 ;
     RECT  45.615 62.387 45.705 62.657 ;
     RECT  51.015 62.429 51.105 62.657 ;
     RECT  56.415 62.537 56.505 62.657 ;
     RECT  61.815 62.429 61.905 62.657 ;
     RECT  67.215 62.501 67.305 62.657 ;
     RECT  72.615 62.465 72.705 62.657 ;
     RECT  78.015 62.387 78.105 62.657 ;
     RECT  83.415 62.387 83.505 62.657 ;
     RECT  42.516 62.621 43.758 62.669 ;
     RECT  24.552 62.657 24.642 62.699 ;
     RECT  26.892 62.465 26.91 62.699 ;
     RECT  42.516 62.669 43.686 63.389 ;
     RECT  42.984 63.389 43.686 63.821 ;
     RECT  43.668 63.821 43.686 64.685 ;
    LAYER M4 ;
     RECT  0.06 24.72 0.227 25.608 ;
     RECT  0.227 25.296 2.245 25.608 ;
     RECT  2.221 3.696 2.293 3.72 ;
     RECT  2.245 8.88 2.293 8.904 ;
     RECT  2.293 6.912 2.329 6.936 ;
     RECT  2.293 8.736 2.329 9.096 ;
     RECT  2.293 10.944 2.329 10.968 ;
     RECT  2.293 2.784 2.365 3.72 ;
     RECT  2.293 5.712 2.365 5.736 ;
     RECT  2.329 6.912 2.365 7.752 ;
     RECT  2.365 5.712 2.401 7.752 ;
     RECT  2.329 8.736 2.401 10.968 ;
     RECT  2.365 2.784 2.408 4.152 ;
     RECT  2.401 5.712 2.408 10.968 ;
     RECT  2.293 13.68 2.408 13.704 ;
     RECT  2.245 24.624 2.408 25.608 ;
     RECT  0.181 32.256 2.408 32.28 ;
     RECT  2.365 44.448 2.408 44.472 ;
     RECT  2.365 48.432 2.408 48.456 ;
     RECT  2.365 51.36 2.408 51.384 ;
     RECT  2.329 55.248 2.408 55.272 ;
     RECT  2.408 2.148 2.512 62.652 ;
     RECT  2.512 2.418 2.704 62.382 ;
     RECT  2.704 19.968 2.873 19.992 ;
     RECT  2.704 54.048 2.915 57.048 ;
     RECT  2.704 34.224 2.945 35.448 ;
     RECT  2.704 29.136 3.107 31.272 ;
     RECT  3.061 0.528 3.121 0.552 ;
     RECT  2.704 32.256 3.203 32.76 ;
     RECT  2.704 26.208 3.233 27.144 ;
     RECT  3.121 0.048 3.305 0.552 ;
     RECT  3.107 29.136 3.413 30.072 ;
     RECT  2.704 58.608 3.443 58.728 ;
     RECT  2.704 44.448 3.485 44.472 ;
     RECT  3.443 58.608 3.485 58.632 ;
     RECT  2.915 55.92 3.521 57.048 ;
     RECT  3.413 29.808 3.593 30.072 ;
     RECT  3.305 0.048 3.635 0.072 ;
     RECT  2.704 18.192 3.697 18.744 ;
     RECT  2.704 21.648 3.697 22.008 ;
     RECT  2.704 40.608 3.701 41.4 ;
     RECT  3.697 21.648 3.733 22.824 ;
     RECT  3.697 18.192 3.773 18.792 ;
     RECT  3.107 31.248 3.805 31.272 ;
     RECT  3.203 32.256 3.805 32.28 ;
     RECT  3.733 21.648 3.841 23.4 ;
     RECT  3.805 31.248 3.845 32.28 ;
     RECT  2.704 51.36 3.877 51.384 ;
     RECT  3.773 18.624 3.913 18.792 ;
     RECT  3.233 26.784 3.953 27.144 ;
     RECT  3.913 18.624 3.997 19.416 ;
     RECT  2.915 54.048 4.021 54.6 ;
     RECT  3.953 27.024 4.057 27.144 ;
     RECT  3.913 28.8 4.057 28.824 ;
     RECT  3.997 18.624 4.067 18.84 ;
     RECT  3.841 20.736 4.093 23.4 ;
     RECT  3.877 51.36 4.093 51.816 ;
     RECT  3.593 30 4.129 30.072 ;
     RECT  4.129 30 4.133 30.264 ;
     RECT  4.067 18.768 4.141 18.84 ;
     RECT  3.845 31.344 4.169 32.28 ;
     RECT  4.169 31.92 4.213 32.28 ;
     RECT  4.093 50.688 4.237 51.816 ;
     RECT  3.949 52.8 4.237 52.824 ;
     RECT  2.945 34.224 4.241 35.016 ;
     RECT  2.704 2.496 4.268 16.872 ;
     RECT  3.521 55.92 4.277 55.944 ;
     RECT  4.237 50.688 4.345 52.824 ;
     RECT  4.021 54.048 4.345 54.648 ;
     RECT  4.268 2.496 4.355 17.112 ;
     RECT  4.237 43.68 4.417 43.704 ;
     RECT  4.093 20.736 4.489 23.64 ;
     RECT  3.697 36.576 4.525 36.6 ;
     RECT  4.417 42.72 4.549 43.704 ;
     RECT  4.345 50.688 4.549 54.648 ;
     RECT  4.489 20.016 4.556 23.64 ;
     RECT  4.556 20.016 4.561 24.024 ;
     RECT  4.201 39.984 4.561 40.008 ;
     RECT  4.549 42.72 4.595 43.896 ;
     RECT  2.704 46.08 4.595 49.032 ;
     RECT  4.561 20.016 4.597 24.12 ;
     RECT  2.704 25.152 4.597 25.176 ;
     RECT  4.057 27.024 4.601 28.824 ;
     RECT  4.549 50.256 4.636 54.648 ;
     RECT  4.241 34.752 4.637 35.016 ;
     RECT  4.595 43.68 4.655 43.896 ;
     RECT  3.701 41.376 4.673 41.4 ;
     RECT  4.525 36 4.741 36.6 ;
     RECT  2.704 38.16 4.741 38.184 ;
     RECT  4.561 39.936 4.745 40.008 ;
     RECT  4.741 36 4.781 38.184 ;
     RECT  4.636 50.688 4.885 54.648 ;
     RECT  4.633 55.824 4.885 55.848 ;
     RECT  4.705 41.616 5.027 41.64 ;
     RECT  4.885 50.688 5.033 55.848 ;
     RECT  4.355 2.496 5.069 16.584 ;
     RECT  4.213 32.256 5.101 32.28 ;
     RECT  4.777 33.6 5.101 33.624 ;
     RECT  5.033 50.688 5.105 54.504 ;
     RECT  3.913 60.384 5.132 60.408 ;
     RECT  4.993 40.032 5.137 40.056 ;
     RECT  4.601 27.648 5.141 28.824 ;
     RECT  5.132 60.384 5.173 60.744 ;
     RECT  5.101 32.256 5.209 33.624 ;
     RECT  4.957 58.128 5.213 58.152 ;
     RECT  5.173 60.384 5.219 61.368 ;
     RECT  4.781 36.048 5.245 38.184 ;
     RECT  5.245 36.048 5.249 39 ;
     RECT  4.655 43.68 5.249 44.472 ;
     RECT  4.849 0.096 5.281 0.12 ;
     RECT  4.597 20.016 5.285 25.176 ;
     RECT  5.281 0.048 5.309 0.12 ;
     RECT  5.141 27.648 5.357 28.68 ;
     RECT  5.249 36.048 5.357 37.896 ;
     RECT  4.595 46.08 5.429 48.744 ;
     RECT  5.069 2.496 5.501 3.432 ;
     RECT  5.285 20.016 5.533 24.696 ;
     RECT  5.533 19.776 5.603 24.696 ;
     RECT  4.133 30.24 5.605 30.264 ;
     RECT  5.357 36.432 5.645 37.896 ;
     RECT  4.141 18.768 5.653 18.792 ;
     RECT  5.603 19.776 5.653 22.776 ;
     RECT  5.603 23.76 5.681 24.696 ;
     RECT  5.209 32.16 5.681 33.624 ;
     RECT  5.645 36.576 5.681 37.896 ;
     RECT  5.653 18.768 5.699 22.776 ;
     RECT  5.137 40.032 5.713 40.104 ;
     RECT  3.521 57.024 5.713 57.048 ;
     RECT  5.681 32.16 5.753 33.096 ;
     RECT  5.681 37.104 5.789 37.896 ;
     RECT  5.309 0.048 5.795 0.552 ;
     RECT  5.605 30.24 5.845 31.08 ;
     RECT  5.753 32.16 5.845 33 ;
     RECT  5.357 27.888 5.897 28.68 ;
     RECT  5.249 38.976 5.897 39 ;
     RECT  5.713 57.024 5.929 57.096 ;
     RECT  5.845 30.24 5.932 33 ;
     RECT  4.637 34.752 5.965 34.776 ;
     RECT  5.713 40.032 6.005 40.152 ;
     RECT  5.795 0.096 6.035 0.552 ;
     RECT  5.069 4.56 6.073 16.584 ;
     RECT  5.932 30.24 6.077 31.08 ;
     RECT  5.033 55.824 6.145 55.848 ;
     RECT  5.929 56.832 6.145 57.096 ;
     RECT  5.105 50.688 6.149 54.36 ;
     RECT  5.219 61.344 6.181 61.368 ;
     RECT  6.035 0.384 6.185 0.552 ;
     RECT  5.965 34.752 6.217 35.352 ;
     RECT  6.181 60.816 6.253 61.368 ;
     RECT  6.185 0.384 6.257 0.504 ;
     RECT  5.429 46.08 6.293 48.312 ;
     RECT  6.145 55.824 6.293 57.096 ;
     RECT  5.929 41.904 6.325 41.928 ;
     RECT  6.073 4.512 6.329 16.584 ;
     RECT  5.501 2.736 6.361 3.432 ;
     RECT  5.681 24.672 6.365 24.696 ;
     RECT  6.361 2.736 6.371 4.152 ;
     RECT  5.249 43.68 6.371 43.704 ;
     RECT  6.289 45.024 6.373 45.048 ;
     RECT  6.005 40.032 6.401 40.056 ;
     RECT  6.293 57.024 6.433 57.096 ;
     RECT  5.932 32.16 6.509 33 ;
     RECT  6.293 46.08 6.509 46.824 ;
     RECT  6.329 5.28 6.515 16.584 ;
     RECT  6.257 0.384 6.545 0.456 ;
     RECT  6.217 34.56 6.545 35.352 ;
     RECT  5.897 28.368 6.617 28.488 ;
     RECT  6.149 50.688 6.653 54.264 ;
     RECT  6.653 50.688 6.685 53.928 ;
     RECT  5.699 19.392 6.709 22.776 ;
     RECT  6.073 58.704 6.757 58.728 ;
     RECT  6.361 26.736 6.761 26.76 ;
     RECT  6.617 28.464 6.761 28.488 ;
     RECT  6.325 41.616 6.764 41.928 ;
     RECT  6.509 46.08 6.793 46.2 ;
     RECT  6.709 19.392 6.797 22.824 ;
     RECT  6.361 18 6.829 18.408 ;
     RECT  6.797 19.392 6.829 22.488 ;
     RECT  6.757 58.704 6.829 58.872 ;
     RECT  6.253 59.904 6.829 61.368 ;
     RECT  6.545 0.384 6.833 0.408 ;
     RECT  6.433 57.024 6.853 57.192 ;
     RECT  6.829 58.368 6.853 61.368 ;
     RECT  6.908 28.992 6.949 29.016 ;
     RECT  6.077 30.24 6.949 30.888 ;
     RECT  5.677 25.728 6.973 25.752 ;
     RECT  5.789 37.872 6.973 37.896 ;
     RECT  6.829 18 7.009 22.488 ;
     RECT  7.009 17.904 7.117 22.488 ;
     RECT  6.293 47.904 7.261 48.312 ;
     RECT  6.685 49.776 7.261 53.928 ;
     RECT  6.515 5.28 7.297 16.008 ;
     RECT  6.949 28.992 7.297 30.888 ;
     RECT  7.297 5.136 7.477 16.008 ;
     RECT  7.117 17.136 7.477 22.488 ;
     RECT  6.371 2.784 7.513 4.152 ;
     RECT  7.477 5.136 7.513 22.488 ;
     RECT  6.793 45.792 7.549 46.2 ;
     RECT  6.545 34.56 7.657 34.92 ;
     RECT  7.621 36.24 7.657 36.264 ;
     RECT  7.513 2.784 7.808 22.488 ;
     RECT  6.973 25.104 7.808 25.752 ;
     RECT  7.297 28.992 7.808 31.224 ;
     RECT  6.509 32.256 7.808 33 ;
     RECT  7.657 34.56 7.808 36.264 ;
     RECT  6.973 37.632 7.808 37.896 ;
     RECT  7.549 39.312 7.808 39.336 ;
     RECT  6.764 41.616 7.808 42.792 ;
     RECT  7.549 45.792 7.808 46.632 ;
     RECT  7.261 47.904 7.808 53.928 ;
     RECT  6.293 55.824 7.808 55.896 ;
     RECT  6.853 57.024 7.808 61.368 ;
     RECT  7.808 2.148 7.912 62.652 ;
     RECT  7.912 2.418 8.104 62.382 ;
     RECT  8.104 18.432 8.201 20.616 ;
     RECT  8.104 34.176 8.201 36.648 ;
     RECT  8.201 18.432 8.273 19.368 ;
     RECT  8.104 22.464 8.273 25.944 ;
     RECT  8.201 20.496 8.309 20.616 ;
     RECT  8.104 56.88 8.345 61.608 ;
     RECT  8.104 16.608 8.381 17.448 ;
     RECT  8.201 34.176 8.525 34.92 ;
     RECT  8.104 2.736 8.561 15.336 ;
     RECT  8.273 22.8 8.561 25.944 ;
     RECT  8.104 48.432 8.597 54.744 ;
     RECT  8.381 16.656 8.633 17.448 ;
     RECT  8.104 27.072 8.669 29.064 ;
     RECT  8.525 34.176 8.749 34.2 ;
     RECT  8.561 25.248 8.805 25.944 ;
     RECT  8.561 22.8 8.812 24.264 ;
     RECT  8.273 18.72 8.849 19.368 ;
     RECT  8.849 18.864 8.867 19.368 ;
     RECT  8.805 25.728 8.867 25.944 ;
     RECT  8.104 55.776 8.867 55.848 ;
     RECT  8.345 56.88 8.885 60.408 ;
     RECT  8.345 61.584 8.893 61.608 ;
     RECT  8.867 18.864 8.915 19.224 ;
     RECT  8.104 30.384 8.957 32.52 ;
     RECT  8.633 16.656 9.029 17.16 ;
     RECT  8.309 20.496 9.029 20.52 ;
     RECT  8.957 30.864 9.065 32.52 ;
     RECT  8.885 56.88 9.101 59.976 ;
     RECT  8.597 48.432 9.133 54.696 ;
     RECT  8.812 22.8 9.173 24.024 ;
     RECT  8.104 37.632 9.245 40.104 ;
     RECT  8.104 46.56 9.313 47.112 ;
     RECT  8.561 2.736 9.317 15.24 ;
     RECT  9.313 46.368 9.317 47.112 ;
     RECT  9.065 31.104 9.425 32.52 ;
     RECT  9.317 2.736 9.452 15.144 ;
     RECT  9.133 48.192 9.484 54.696 ;
     RECT  8.867 25.92 9.493 25.944 ;
     RECT  8.669 27.072 9.493 28.632 ;
     RECT  9.029 16.656 9.533 16.68 ;
     RECT  9.493 25.92 9.533 28.632 ;
     RECT  9.425 31.104 9.533 32.28 ;
     RECT  8.104 41.616 9.533 44.472 ;
     RECT  9.484 48.192 9.601 51.24 ;
     RECT  9.452 2.544 9.637 15.144 ;
     RECT  8.201 36.624 9.637 36.648 ;
     RECT  9.533 31.152 9.677 32.28 ;
     RECT  9.205 33.696 9.677 33.72 ;
     RECT  9.529 34.752 9.683 34.776 ;
     RECT  9.637 36.48 9.683 36.648 ;
     RECT  9.637 2.208 9.713 15.144 ;
     RECT  9.529 1.104 9.745 1.128 ;
     RECT  9.713 2.208 9.745 14.904 ;
     RECT  9.677 31.2 9.785 32.28 ;
     RECT  9.745 1.104 9.889 14.904 ;
     RECT  9.101 56.976 9.971 59.976 ;
     RECT  9.889 0.576 10.001 14.904 ;
     RECT  9.484 52.224 10.001 54.696 ;
     RECT  8.915 19.2 10.137 19.224 ;
     RECT  10.001 0.576 10.163 9.72 ;
     RECT  9.385 61.488 10.213 61.512 ;
     RECT  9.683 36.48 10.253 36.504 ;
     RECT  9.601 47.808 10.289 51.24 ;
     RECT  10.213 61.008 10.289 61.512 ;
     RECT  10.213 18.816 10.297 18.84 ;
     RECT  10.001 54.096 10.325 54.696 ;
     RECT  9.245 37.872 10.357 39.912 ;
     RECT  9.533 41.616 10.357 43.32 ;
     RECT  10.357 37.872 10.403 43.32 ;
     RECT  8.867 55.776 10.429 55.8 ;
     RECT  9.971 56.976 10.429 59.784 ;
     RECT  10.325 54.096 10.469 54.456 ;
     RECT  10.429 55.776 10.469 59.784 ;
     RECT  10.001 52.224 10.613 53.064 ;
     RECT  9.533 26.208 10.645 28.632 ;
     RECT  10.645 26.208 10.649 28.776 ;
     RECT  10.001 10.848 10.681 14.904 ;
     RECT  10.163 0.576 10.739 0.6 ;
     RECT  9.173 23.28 10.741 24.024 ;
     RECT  10.609 25.104 10.741 25.128 ;
     RECT  10.649 27.072 10.937 28.776 ;
     RECT  10.741 23.28 10.945 25.128 ;
     RECT  10.789 0.528 10.961 0.552 ;
     RECT  10.021 16.56 10.969 16.584 ;
     RECT  10.028 17.616 10.969 17.64 ;
     RECT  9.533 44.448 11.077 44.472 ;
     RECT  10.469 59.76 11.113 59.784 ;
     RECT  10.289 61.008 11.113 61.032 ;
     RECT  10.961 0.096 11.123 0.552 ;
     RECT  10.469 55.776 11.233 58.776 ;
     RECT  9.493 22.224 11.257 22.248 ;
     RECT  10.945 23.28 11.257 24.312 ;
     RECT  11.233 55.776 11.257 57.912 ;
     RECT  11.257 22.224 11.293 24.312 ;
     RECT  10.403 40.368 11.324 43.32 ;
     RECT  11.077 44.448 11.324 44.808 ;
     RECT  10.163 1.728 11.329 9.72 ;
     RECT  10.681 10.848 11.329 15.048 ;
     RECT  9.317 46.368 11.329 46.776 ;
     RECT  10.613 52.224 11.329 52.248 ;
     RECT  11.113 59.76 11.333 61.032 ;
     RECT  11.293 22.032 11.341 24.312 ;
     RECT  11.329 46.128 11.365 46.776 ;
     RECT  10.289 47.808 11.365 51.144 ;
     RECT  11.329 1.728 11.401 15.048 ;
     RECT  10.969 16.56 11.401 17.64 ;
     RECT  11.324 40.368 11.411 44.808 ;
     RECT  11.365 46.128 11.413 51.144 ;
     RECT  11.411 44.544 11.452 44.808 ;
     RECT  11.257 55.728 11.477 57.912 ;
     RECT  10.213 34.176 11.509 34.2 ;
     RECT  11.221 18.96 11.545 18.984 ;
     RECT  11.401 1.728 11.549 17.64 ;
     RECT  11.341 23.28 11.549 24.312 ;
     RECT  11.477 56.304 11.549 57.912 ;
     RECT  11.329 52.176 11.612 52.248 ;
     RECT  11.509 34.032 11.617 34.2 ;
     RECT  10.403 37.872 11.617 39.384 ;
     RECT  11.411 40.368 11.617 42.84 ;
     RECT  11.365 25.632 11.621 25.656 ;
     RECT  11.612 52.176 11.653 52.68 ;
     RECT  10.469 54.432 11.653 54.456 ;
     RECT  11.617 37.872 11.657 42.84 ;
     RECT  11.549 56.304 11.693 57.864 ;
     RECT  11.653 52.176 11.699 54.456 ;
     RECT  11.699 53.568 11.833 54.456 ;
     RECT  11.437 20.256 11.837 20.28 ;
     RECT  11.549 23.28 11.873 23.976 ;
     RECT  11.549 3.84 11.891 17.64 ;
     RECT  10.789 36.624 11.941 36.648 ;
     RECT  11.657 37.872 11.941 42.648 ;
     RECT  11.617 34.032 11.945 34.536 ;
     RECT  11.341 22.032 11.977 22.056 ;
     RECT  11.452 44.784 11.989 44.808 ;
     RECT  10.937 27.648 12.017 28.776 ;
     RECT  11.941 36.624 12.017 42.648 ;
     RECT  11.333 60.432 12.017 61.032 ;
     RECT  11.891 5.088 12.028 17.64 ;
     RECT  9.785 31.344 12.053 32.28 ;
     RECT  11.977 21.696 12.077 22.056 ;
     RECT  12.017 27.648 12.085 28.632 ;
     RECT  11.413 46.848 12.089 51.144 ;
     RECT  11.699 52.176 12.089 52.248 ;
     RECT  11.545 18.96 12.125 19.176 ;
     RECT  12.017 36.624 12.161 39.384 ;
     RECT  12.089 47.04 12.197 51.144 ;
     RECT  12.017 60.432 12.197 60.456 ;
     RECT  12.197 49.776 12.265 51.144 ;
     RECT  11.123 0.096 12.269 0.168 ;
     RECT  12.269 0.144 12.553 0.168 ;
     RECT  12.077 21.648 12.589 22.056 ;
     RECT  12.553 0.144 12.625 0.552 ;
     RECT  11.549 1.728 12.733 2.328 ;
     RECT  11.891 3.84 12.733 3.96 ;
     RECT  11.989 44.784 12.733 45.72 ;
     RECT  12.589 20.976 12.805 22.056 ;
     RECT  11.945 34.512 12.805 34.536 ;
     RECT  12.733 43.872 12.805 45.72 ;
     RECT  12.028 9.072 12.841 17.64 ;
     RECT  12.125 18.96 12.841 19.08 ;
     RECT  12.805 20.688 12.841 22.056 ;
     RECT  12.517 25.2 12.841 25.224 ;
     RECT  12.089 52.224 12.841 52.248 ;
     RECT  11.833 53.568 12.841 54.696 ;
     RECT  12.733 1.728 12.853 3.96 ;
     RECT  12.028 5.088 12.853 7.752 ;
     RECT  12.161 36.624 12.913 39.288 ;
     RECT  12.841 52.224 12.985 54.696 ;
     RECT  12.841 9.072 13.013 19.08 ;
     RECT  12.841 25.152 13.055 25.224 ;
     RECT  12.841 20.256 13.057 22.056 ;
     RECT  12.589 26.304 13.057 26.328 ;
     RECT  12.445 61.728 13.057 61.752 ;
     RECT  12.625 0.144 13.093 0.6 ;
     RECT  12.853 1.728 13.093 7.752 ;
     RECT  13.013 8.832 13.093 19.08 ;
     RECT  13.057 20.16 13.093 22.056 ;
     RECT  13.055 25.104 13.093 25.224 ;
     RECT  12.265 49.776 13.165 51.24 ;
     RECT  13.093 0.144 13.177 7.752 ;
     RECT  12.805 34.512 13.201 34.68 ;
     RECT  12.913 36 13.201 39.288 ;
     RECT  12.805 43.824 13.201 45.72 ;
     RECT  12.197 47.04 13.201 48.504 ;
     RECT  13.177 1.728 13.208 7.752 ;
     RECT  13.093 8.832 13.208 22.056 ;
     RECT  11.873 23.28 13.208 23.544 ;
     RECT  13.093 25.104 13.208 25.272 ;
     RECT  13.057 26.304 13.208 26.376 ;
     RECT  12.085 27.408 13.208 28.632 ;
     RECT  12.053 31.92 13.208 32.28 ;
     RECT  13.201 34.512 13.208 39.288 ;
     RECT  12.017 40.416 13.208 42.648 ;
     RECT  13.201 43.824 13.208 48.504 ;
     RECT  13.165 49.584 13.208 51.24 ;
     RECT  12.985 52.224 13.208 55.272 ;
     RECT  11.693 56.304 13.208 57.048 ;
     RECT  12.625 58.656 13.208 58.68 ;
     RECT  12.409 59.76 13.208 60.36 ;
     RECT  13.057 61.728 13.208 62.04 ;
     RECT  13.208 1.728 13.312 62.652 ;
     RECT  13.312 1.728 13.504 62.382 ;
     RECT  13.504 2.832 13.715 7.944 ;
     RECT  13.177 0.144 13.733 0.552 ;
     RECT  13.504 31.44 13.811 34.2 ;
     RECT  13.733 0.096 13.817 0.552 ;
     RECT  13.817 0.144 13.907 0.552 ;
     RECT  13.504 9.12 13.925 28.392 ;
     RECT  13.925 20.064 13.955 28.392 ;
     RECT  13.955 24.24 13.997 28.392 ;
     RECT  13.955 20.064 14.105 23.064 ;
     RECT  13.504 52.224 14.105 59.256 ;
     RECT  13.925 9.12 14.141 18.84 ;
     RECT  14.105 20.208 14.177 23.064 ;
     RECT  13.997 25.104 14.285 28.392 ;
     RECT  13.907 0.144 14.291 0.168 ;
     RECT  14.105 54.144 14.291 59.256 ;
     RECT  13.504 39.744 14.321 51.24 ;
     RECT  13.504 35.184 14.429 38.76 ;
     RECT  14.321 41.52 14.429 51.24 ;
     RECT  13.504 30 14.533 30.216 ;
     RECT  13.811 33.504 14.533 34.2 ;
     RECT  14.429 35.184 14.533 38.52 ;
     RECT  13.715 3.072 14.569 7.944 ;
     RECT  14.141 9.12 14.569 18.216 ;
     RECT  14.533 33.504 14.573 38.52 ;
     RECT  14.321 39.744 14.573 40.44 ;
     RECT  14.105 52.224 14.579 53.016 ;
     RECT  14.291 54.144 14.645 56.328 ;
     RECT  13.504 1.728 14.677 1.848 ;
     RECT  14.569 3.072 14.677 18.216 ;
     RECT  14.533 28.944 14.681 30.216 ;
     RECT  14.429 49.44 14.713 51.24 ;
     RECT  14.579 52.224 14.713 52.92 ;
     RECT  14.681 28.944 14.753 30.072 ;
     RECT  14.645 54.144 14.789 55.992 ;
     RECT  14.429 41.52 14.819 48.456 ;
     RECT  14.677 1.728 14.821 18.216 ;
     RECT  14.573 36 14.861 38.52 ;
     RECT  14.819 45.648 14.897 48.456 ;
     RECT  14.291 57.648 14.929 59.256 ;
     RECT  13.504 60.336 14.929 62.04 ;
     RECT  14.819 41.52 14.933 44.472 ;
     RECT  14.713 49.44 14.969 52.92 ;
     RECT  14.285 25.104 15.001 27.672 ;
     RECT  13.811 31.44 15.073 32.52 ;
     RECT  14.573 33.504 15.073 34.68 ;
     RECT  15.001 24.432 15.145 27.672 ;
     RECT  14.821 1.152 15.185 18.216 ;
     RECT  14.789 55.968 15.185 55.992 ;
     RECT  15.185 1.152 15.203 13.032 ;
     RECT  15.203 1.152 15.251 3.192 ;
     RECT  15.203 4.272 15.257 13.032 ;
     RECT  15.253 0.528 15.289 0.6 ;
     RECT  15.185 14.016 15.437 18.216 ;
     RECT  14.933 41.904 15.437 44.472 ;
     RECT  14.929 57.648 15.473 62.04 ;
     RECT  14.897 46.224 15.505 48.456 ;
     RECT  14.969 49.44 15.505 51.24 ;
     RECT  15.473 57.648 15.617 58.632 ;
     RECT  15.473 59.616 15.617 62.04 ;
     RECT  15.251 1.728 15.689 3.192 ;
     RECT  15.289 0.432 15.731 0.6 ;
     RECT  15.073 31.44 15.757 34.68 ;
     RECT  15.437 17.568 15.793 18.216 ;
     RECT  14.753 28.944 15.793 30.024 ;
     RECT  15.757 31.152 15.793 34.68 ;
     RECT  14.861 36 15.925 37.608 ;
     RECT  14.573 39.744 15.925 39.912 ;
     RECT  14.789 54.144 15.941 54.888 ;
     RECT  15.793 28.944 15.977 34.68 ;
     RECT  15.977 30.384 15.985 34.68 ;
     RECT  15.925 35.712 16.009 37.608 ;
     RECT  15.145 24.144 16.085 27.672 ;
     RECT  16.009 34.752 16.121 37.608 ;
     RECT  15.977 28.944 16.157 29.256 ;
     RECT  15.925 39.12 16.157 39.912 ;
     RECT  15.617 59.616 16.157 61.08 ;
     RECT  16.157 39.12 16.189 39.528 ;
     RECT  16.117 55.872 16.201 55.896 ;
     RECT  15.505 46.224 16.229 51.24 ;
     RECT  15.793 17.568 16.261 18.792 ;
     RECT  14.177 20.304 16.261 23.064 ;
     RECT  14.969 52.224 16.265 52.92 ;
     RECT  16.189 38.64 16.297 39.528 ;
     RECT  16.121 34.752 16.355 37.56 ;
     RECT  15.257 4.272 16.405 12.936 ;
     RECT  16.297 38.592 16.499 39.528 ;
     RECT  15.437 14.016 16.585 16.584 ;
     RECT  16.261 17.568 16.585 23.064 ;
     RECT  16.405 3.84 16.657 12.936 ;
     RECT  16.585 14.016 16.657 23.064 ;
     RECT  16.657 3.84 16.697 23.064 ;
     RECT  16.157 60.24 16.697 61.08 ;
     RECT  15.437 41.952 16.729 44.472 ;
     RECT  16.333 57.024 16.765 57.048 ;
     RECT  15.617 58.56 16.765 58.632 ;
     RECT  16.085 24.144 16.769 26.904 ;
     RECT  16.157 28.944 16.805 28.968 ;
     RECT  16.499 39.12 16.805 39.528 ;
     RECT  16.697 21.504 16.873 23.064 ;
     RECT  16.769 24.144 16.873 26.328 ;
     RECT  15.731 0.576 16.909 0.6 ;
     RECT  15.985 30.384 16.945 33.576 ;
     RECT  16.909 0.528 16.981 0.6 ;
     RECT  15.689 1.728 16.981 2.856 ;
     RECT  16.873 21.504 16.985 26.328 ;
     RECT  16.945 30.24 16.985 33.576 ;
     RECT  16.229 47.376 17.036 51.24 ;
     RECT  16.265 52.224 17.036 52.776 ;
     RECT  15.941 54.288 17.089 54.888 ;
     RECT  16.985 21.504 17.129 25.224 ;
     RECT  16.765 57.024 17.201 58.632 ;
     RECT  16.981 0.528 17.221 2.856 ;
     RECT  17.221 0.096 17.269 2.856 ;
     RECT  16.697 3.84 17.269 20.472 ;
     RECT  17.089 53.904 17.269 55.416 ;
     RECT  16.355 34.752 17.273 37.512 ;
     RECT  16.805 39.312 17.305 39.528 ;
     RECT  17.201 57.36 17.341 58.632 ;
     RECT  16.985 26.304 17.345 26.328 ;
     RECT  16.441 27.888 17.377 27.912 ;
     RECT  16.985 30.24 17.381 32.376 ;
     RECT  17.273 34.752 17.413 35.736 ;
     RECT  17.381 30.24 17.417 30.744 ;
     RECT  17.036 47.376 17.449 52.776 ;
     RECT  17.269 53.808 17.449 55.416 ;
     RECT  17.305 39.312 17.485 40.44 ;
     RECT  16.729 41.952 17.485 45.048 ;
     RECT  17.269 0.096 17.555 20.472 ;
     RECT  16.981 61.536 17.629 61.56 ;
     RECT  16.697 60.24 17.665 60.264 ;
     RECT  17.629 61.536 17.665 61.896 ;
     RECT  17.449 47.376 17.701 55.416 ;
     RECT  17.555 0.096 17.777 0.696 ;
     RECT  17.273 36.768 17.881 37.512 ;
     RECT  17.381 31.872 17.953 32.376 ;
     RECT  16.985 33.504 17.953 33.576 ;
     RECT  16.229 46.224 18.133 46.248 ;
     RECT  17.701 47.376 18.133 55.992 ;
     RECT  17.377 27.696 18.169 27.912 ;
     RECT  17.341 57.36 18.169 59.016 ;
     RECT  17.485 39.312 18.205 40.872 ;
     RECT  17.413 34.656 18.241 35.736 ;
     RECT  17.881 36.768 18.241 37.704 ;
     RECT  18.205 39.216 18.313 40.872 ;
     RECT  17.485 41.952 18.385 45.24 ;
     RECT  18.133 46.224 18.385 55.992 ;
     RECT  17.665 60.24 18.385 61.896 ;
     RECT  18.385 41.952 18.457 55.992 ;
     RECT  17.129 21.504 18.529 24.6 ;
     RECT  17.417 30.24 18.529 30.264 ;
     RECT  17.555 1.728 18.608 20.472 ;
     RECT  18.529 21.504 18.608 25.272 ;
     RECT  18.169 26.784 18.608 27.912 ;
     RECT  17.197 29.04 18.608 29.064 ;
     RECT  18.529 30.24 18.608 30.696 ;
     RECT  17.953 31.872 18.608 33.576 ;
     RECT  18.241 34.656 18.608 37.704 ;
     RECT  18.313 38.736 18.608 40.872 ;
     RECT  18.457 41.904 18.608 55.992 ;
     RECT  18.169 57.072 18.608 59.016 ;
     RECT  18.385 60.24 18.608 61.992 ;
     RECT  17.777 0.096 18.707 0.312 ;
     RECT  18.608 1.728 18.712 62.652 ;
     RECT  18.712 1.728 18.904 62.382 ;
     RECT  18.904 40.416 18.965 58.152 ;
     RECT  18.904 17.472 19.043 18.216 ;
     RECT  18.904 1.728 19.073 1.8 ;
     RECT  18.904 26.448 19.073 33.096 ;
     RECT  18.965 55.824 19.109 58.152 ;
     RECT  19.073 1.776 19.145 1.8 ;
     RECT  18.904 3.168 19.181 16.344 ;
     RECT  19.073 26.448 19.181 30.264 ;
     RECT  18.965 40.416 19.253 54.6 ;
     RECT  18.904 34.656 19.325 39.24 ;
     RECT  19.043 17.616 19.361 18.216 ;
     RECT  19.181 26.448 19.397 27.432 ;
     RECT  19.073 31.296 19.397 33.096 ;
     RECT  18.904 20.064 19.433 20.328 ;
     RECT  19.109 57.696 19.505 58.152 ;
     RECT  19.253 41.184 19.541 45.576 ;
     RECT  19.181 3.168 19.571 16.008 ;
     RECT  18.904 21.504 19.613 21.72 ;
     RECT  19.541 41.184 19.613 45.48 ;
     RECT  18.904 22.752 19.685 25.08 ;
     RECT  19.571 3.888 19.693 16.008 ;
     RECT  19.325 34.656 19.829 36.792 ;
     RECT  19.685 22.752 19.859 23.064 ;
     RECT  19.181 28.512 19.859 30.264 ;
     RECT  19.685 24.096 19.865 25.08 ;
     RECT  18.904 60.816 19.897 61.992 ;
     RECT  19.397 26.448 19.9 27.336 ;
     RECT  19.613 21.696 19.933 21.72 ;
     RECT  19.897 60.48 19.937 61.992 ;
     RECT  19.505 57.84 19.969 58.152 ;
     RECT  19.613 42.72 20.009 45.48 ;
     RECT  19.325 37.92 20.041 39.24 ;
     RECT  19.693 3.888 20.045 14.808 ;
     RECT  19.969 57.84 20.081 58.488 ;
     RECT  19.361 18.192 20.153 18.216 ;
     RECT  19.865 24.096 20.189 24.696 ;
     RECT  19.253 46.848 20.293 54.6 ;
     RECT  19.109 55.824 20.293 56.088 ;
     RECT  19.829 35.472 20.329 36.792 ;
     RECT  20.041 37.92 20.329 39.336 ;
     RECT  20.293 46.848 20.401 56.088 ;
     RECT  19.693 15.984 20.434 16.008 ;
     RECT  20.045 3.888 20.441 11.736 ;
     RECT  20.045 12.768 20.441 14.808 ;
     RECT  20.441 3.888 20.476 11.64 ;
     RECT  20.441 12.768 20.477 12.84 ;
     RECT  19.613 41.184 20.477 41.448 ;
     RECT  19.397 31.296 20.545 32.808 ;
     RECT  20.509 33.84 20.545 33.864 ;
     RECT  20.477 12.768 20.585 12.792 ;
     RECT  20.009 42.72 20.617 45.048 ;
     RECT  18.707 0.096 20.621 0.12 ;
     RECT  20.617 42.528 20.629 45.048 ;
     RECT  20.081 58.128 20.653 58.488 ;
     RECT  20.653 2.736 20.689 2.76 ;
     RECT  20.476 3.888 20.689 10.728 ;
     RECT  20.189 24.096 20.693 24.6 ;
     RECT  20.629 40.416 20.716 40.584 ;
     RECT  19.933 21.696 20.725 22.2 ;
     RECT  19.9 26.784 20.761 27.336 ;
     RECT  19.859 28.512 20.761 30.216 ;
     RECT  20.329 35.472 20.765 39.336 ;
     RECT  20.629 41.856 20.765 45.048 ;
     RECT  19.937 61.584 20.765 61.992 ;
     RECT  20.441 13.968 20.833 14.808 ;
     RECT  20.434 15.984 20.833 16.056 ;
     RECT  20.833 13.968 20.941 16.44 ;
     RECT  20.653 58.128 20.941 59.112 ;
     RECT  19.937 60.48 20.941 60.504 ;
     RECT  20.401 46.848 20.945 56.424 ;
     RECT  20.765 35.712 20.977 39.336 ;
     RECT  20.716 40.416 20.977 40.44 ;
     RECT  20.725 21.552 21.013 22.2 ;
     RECT  20.689 2.736 21.017 10.728 ;
     RECT  20.761 26.784 21.049 30.216 ;
     RECT  20.545 31.296 21.049 33.864 ;
     RECT  20.945 54.048 21.085 56.424 ;
     RECT  21.049 26.784 21.089 33.864 ;
     RECT  20.945 46.848 21.125 52.824 ;
     RECT  19.433 20.304 21.193 20.328 ;
     RECT  21.089 29.28 21.305 33.864 ;
     RECT  21.085 54.048 21.347 56.664 ;
     RECT  21.017 2.736 21.409 10.344 ;
     RECT  21.347 54.096 21.445 56.664 ;
     RECT  20.941 58.128 21.445 60.504 ;
     RECT  21.445 54.096 21.449 60.504 ;
     RECT  21.449 54.096 21.485 56.088 ;
     RECT  21.409 2.64 21.539 10.344 ;
     RECT  21.089 26.784 21.557 28.056 ;
     RECT  21.539 6.72 21.587 10.344 ;
     RECT  21.049 25.776 21.589 25.8 ;
     RECT  21.557 26.784 21.589 27.912 ;
     RECT  21.589 25.776 21.593 27.912 ;
     RECT  20.765 41.856 21.593 44.856 ;
     RECT  21.125 46.848 21.625 52.584 ;
     RECT  21.305 29.616 21.629 33.864 ;
     RECT  21.593 42.528 21.629 44.856 ;
     RECT  21.449 57.6 21.629 60.504 ;
     RECT  21.193 19.92 21.637 20.328 ;
     RECT  21.013 21.552 21.637 22.248 ;
     RECT  21.539 2.64 21.665 5.736 ;
     RECT  21.637 19.92 21.683 22.248 ;
     RECT  21.625 46.272 21.683 52.584 ;
     RECT  21.629 57.648 21.697 60.504 ;
     RECT  20.765 61.584 21.697 61.704 ;
     RECT  20.941 13.968 21.733 16.584 ;
     RECT  21.013 17.712 21.733 17.736 ;
     RECT  21.683 46.272 21.769 52.296 ;
     RECT  21.587 6.72 21.773 9.336 ;
     RECT  21.769 46.224 21.829 52.296 ;
     RECT  21.773 6.816 21.845 9.336 ;
     RECT  21.697 57.648 21.881 61.704 ;
     RECT  21.845 6.816 21.916 9.288 ;
     RECT  21.881 59.088 21.917 61.704 ;
     RECT  21.629 31.92 21.925 33.864 ;
     RECT  20.977 35.712 21.925 40.44 ;
     RECT  21.925 31.92 22.012 40.44 ;
     RECT  21.733 13.968 22.057 17.736 ;
     RECT  21.589 18.816 22.057 18.84 ;
     RECT  22.057 13.968 22.097 18.84 ;
     RECT  21.593 25.776 22.133 26.568 ;
     RECT  21.665 2.64 22.165 5.64 ;
     RECT  20.693 24.528 22.165 24.6 ;
     RECT  22.012 35.424 22.205 40.44 ;
     RECT  21.629 42.72 22.261 44.856 ;
     RECT  21.829 46.128 22.261 52.296 ;
     RECT  21.629 29.616 22.277 30.888 ;
     RECT  21.517 11.376 22.313 11.4 ;
     RECT  21.917 59.088 22.313 60.936 ;
     RECT  22.261 42.72 22.348 52.296 ;
     RECT  21.881 57.648 22.385 57.672 ;
     RECT  21.485 54.096 22.453 56.04 ;
     RECT  22.313 59.568 22.457 60.936 ;
     RECT  22.348 46.128 22.493 52.296 ;
     RECT  22.012 31.92 22.529 34.392 ;
     RECT  21.683 20.304 22.597 22.248 ;
     RECT  22.165 23.952 22.597 24.6 ;
     RECT  22.453 53.712 22.597 56.04 ;
     RECT  22.529 32.112 22.637 34.392 ;
     RECT  22.597 20.304 22.669 24.6 ;
     RECT  22.489 29.088 22.691 29.112 ;
     RECT  22.133 26.4 22.705 26.568 ;
     RECT  22.669 19.584 22.709 24.6 ;
     RECT  22.165 2.592 22.741 5.64 ;
     RECT  22.705 26.4 22.741 26.856 ;
     RECT  21.593 27.888 22.741 27.912 ;
     RECT  22.493 46.224 22.741 52.296 ;
     RECT  22.741 26.4 22.781 27.912 ;
     RECT  21.916 7.2 22.853 9.288 ;
     RECT  22.781 26.4 22.853 27.432 ;
     RECT  22.205 35.424 22.853 35.736 ;
     RECT  22.597 53.664 22.853 56.04 ;
     RECT  22.741 2.592 22.889 6.072 ;
     RECT  22.097 13.968 22.889 18.216 ;
     RECT  22.853 54.096 22.889 56.04 ;
     RECT  22.348 42.72 22.921 44.856 ;
     RECT  22.709 23.136 22.925 23.976 ;
     RECT  22.457 60.144 22.925 60.936 ;
     RECT  22.889 54.336 22.933 56.04 ;
     RECT  22.889 2.64 22.957 6.072 ;
     RECT  22.853 7.2 22.957 8.184 ;
     RECT  22.741 12.528 22.957 12.552 ;
     RECT  22.853 9.216 22.961 9.288 ;
     RECT  22.925 23.136 22.961 23.544 ;
     RECT  22.921 41.952 22.993 44.856 ;
     RECT  22.925 60.144 22.997 60.168 ;
     RECT  22.961 9.264 23.029 9.288 ;
     RECT  21.587 10.32 23.029 10.344 ;
     RECT  22.957 12.48 23.029 12.696 ;
     RECT  23.029 12.432 23.137 12.696 ;
     RECT  22.889 13.968 23.137 17.64 ;
     RECT  22.709 19.584 23.137 21.576 ;
     RECT  22.741 46.224 23.137 52.68 ;
     RECT  22.933 54.336 23.209 56.376 ;
     RECT  22.277 30.24 23.281 30.888 ;
     RECT  22.205 36.96 23.281 40.152 ;
     RECT  23.029 9.264 23.365 10.344 ;
     RECT  23.101 58.128 23.365 58.152 ;
     RECT  23.281 30.144 23.533 30.888 ;
     RECT  22.637 32.112 23.533 33.336 ;
     RECT  22.637 34.368 23.533 34.392 ;
     RECT  23.281 36.96 23.533 40.536 ;
     RECT  22.993 41.904 23.569 44.856 ;
     RECT  23.365 58.128 23.569 58.92 ;
     RECT  23.533 30.144 23.677 33.336 ;
     RECT  23.533 34.368 23.677 34.968 ;
     RECT  23.677 30.144 23.893 34.968 ;
     RECT  22.853 26.832 23.965 27.432 ;
     RECT  23.365 9.264 24.001 10.872 ;
     RECT  23.137 12.192 24.001 17.64 ;
     RECT  22.957 2.64 24.008 8.184 ;
     RECT  24.001 9.264 24.008 17.64 ;
     RECT  23.137 18.672 24.008 21.576 ;
     RECT  22.961 23.52 24.008 23.544 ;
     RECT  23.965 26.832 24.008 27.96 ;
     RECT  23.893 29.28 24.008 34.968 ;
     RECT  23.533 36.864 24.008 40.536 ;
     RECT  23.569 41.904 24.008 45.192 ;
     RECT  23.137 46.224 24.008 53.016 ;
     RECT  23.209 54.336 24.008 56.76 ;
     RECT  23.569 58.128 24.008 59.304 ;
     RECT  22.777 62.016 24.008 62.04 ;
     RECT  24.008 2.148 24.112 62.652 ;
     RECT  24.112 2.418 24.304 62.382 ;
     RECT  24.304 15.12 24.467 16.584 ;
     RECT  24.304 3.744 24.545 14.136 ;
     RECT  24.304 29.28 24.545 35.496 ;
     RECT  24.304 36.48 24.581 53.016 ;
     RECT  24.581 36.48 24.625 39.384 ;
     RECT  24.545 3.744 24.941 13.704 ;
     RECT  24.304 25.152 25.013 27.96 ;
     RECT  24.545 29.376 25.121 35.496 ;
     RECT  25.121 34.08 25.187 35.496 ;
     RECT  24.625 36.48 25.187 39.336 ;
     RECT  24.581 40.416 25.229 53.016 ;
     RECT  24.304 60.864 25.229 62.28 ;
     RECT  24.467 15.12 25.301 15.24 ;
     RECT  25.013 25.152 25.301 27.864 ;
     RECT  25.301 25.68 25.373 27.864 ;
     RECT  25.229 60.864 25.445 61.944 ;
     RECT  24.941 3.744 25.481 12.024 ;
     RECT  24.304 54.048 25.553 59.736 ;
     RECT  24.467 16.512 25.585 16.584 ;
     RECT  25.187 37.056 25.612 39.336 ;
     RECT  25.121 29.376 25.625 32.616 ;
     RECT  25.481 8.736 25.661 12.024 ;
     RECT  24.304 23.712 25.661 23.736 ;
     RECT  25.229 40.464 25.693 53.016 ;
     RECT  25.553 54.048 25.693 57.624 ;
     RECT  25.661 8.784 25.697 12.024 ;
     RECT  24.304 18.816 25.697 22.248 ;
     RECT  25.697 11.232 25.805 12.024 ;
     RECT  24.941 13.056 25.805 13.704 ;
     RECT  25.481 3.744 25.837 7.752 ;
     RECT  25.837 3.696 25.877 7.752 ;
     RECT  25.625 31.44 25.877 32.616 ;
     RECT  25.553 58.656 25.913 59.736 ;
     RECT  25.805 11.376 25.949 12.024 ;
     RECT  25.301 15.12 25.985 15.144 ;
     RECT  25.697 18.816 26.017 21.144 ;
     RECT  25.877 3.696 26.021 5.928 ;
     RECT  25.693 40.464 26.021 57.624 ;
     RECT  25.445 60.96 26.093 61.944 ;
     RECT  25.949 11.424 26.125 12.024 ;
     RECT  25.585 16.512 26.125 17.448 ;
     RECT  26.021 40.464 26.195 57.048 ;
     RECT  26.125 16.272 26.233 17.448 ;
     RECT  26.021 3.696 26.273 5.88 ;
     RECT  25.625 29.376 26.273 30.168 ;
     RECT  26.195 40.464 26.273 41.208 ;
     RECT  26.125 11.424 26.309 12.264 ;
     RECT  25.187 34.752 26.309 35.496 ;
     RECT  26.093 60.96 26.309 61.8 ;
     RECT  26.273 29.376 26.345 29.496 ;
     RECT  25.612 37.056 26.417 38.856 ;
     RECT  26.233 16.272 26.525 17.544 ;
     RECT  26.017 18.528 26.561 21.144 ;
     RECT  26.417 37.056 26.593 38.52 ;
     RECT  25.697 22.224 26.669 22.248 ;
     RECT  25.877 31.44 26.693 32.568 ;
     RECT  25.877 6.96 26.701 7.752 ;
     RECT  25.373 25.68 26.737 27.672 ;
     RECT  26.195 42.768 26.777 57.048 ;
     RECT  26.561 18.528 26.809 20.856 ;
     RECT  25.805 13.68 26.885 13.704 ;
     RECT  26.809 18.048 26.885 20.856 ;
     RECT  26.273 3.696 26.921 3.72 ;
     RECT  26.737 25.2 26.924 27.672 ;
     RECT  26.273 40.464 26.953 41.016 ;
     RECT  26.924 25.2 26.965 27.912 ;
     RECT  26.309 11.424 26.989 11.688 ;
     RECT  26.693 30.72 27.025 32.568 ;
     RECT  26.945 13.104 27.029 13.128 ;
     RECT  26.273 4.704 27.137 5.88 ;
     RECT  26.777 42.816 27.173 57.048 ;
     RECT  27.025 30.72 27.205 32.808 ;
     RECT  25.913 58.656 27.205 58.776 ;
     RECT  26.953 59.856 27.205 60.456 ;
     RECT  26.701 6.96 27.241 7.8 ;
     RECT  26.989 11.376 27.277 11.688 ;
     RECT  26.525 16.272 27.281 16.584 ;
     RECT  27.169 2.304 27.313 2.328 ;
     RECT  25.697 8.784 27.313 10.248 ;
     RECT  27.205 30.72 27.313 33.384 ;
     RECT  26.309 34.752 27.313 35.064 ;
     RECT  26.345 29.472 27.349 29.496 ;
     RECT  27.173 54.576 27.349 57.048 ;
     RECT  26.885 18.048 27.353 18.888 ;
     RECT  26.125 23.568 27.356 23.592 ;
     RECT  26.965 25.2 27.356 28.296 ;
     RECT  27.241 6.816 27.389 7.8 ;
     RECT  27.389 6.96 27.421 7.8 ;
     RECT  27.313 8.784 27.421 10.392 ;
     RECT  27.313 2.304 27.425 3.144 ;
     RECT  27.356 23.568 27.443 28.296 ;
     RECT  27.421 6.96 27.529 10.392 ;
     RECT  27.277 11.376 27.529 11.784 ;
     RECT  26.953 40.32 27.529 41.016 ;
     RECT  27.443 25.2 27.533 28.296 ;
     RECT  27.349 54.576 27.533 57.144 ;
     RECT  26.885 20.304 27.601 20.856 ;
     RECT  27.533 25.44 27.601 28.296 ;
     RECT  27.349 29.472 27.601 29.64 ;
     RECT  27.313 30.72 27.601 35.064 ;
     RECT  26.593 36.048 27.601 38.52 ;
     RECT  26.309 61.44 27.605 61.8 ;
     RECT  27.533 55.152 27.637 57.144 ;
     RECT  27.205 58.656 27.637 60.456 ;
     RECT  27.443 23.568 27.673 23.592 ;
     RECT  27.605 61.632 27.74 61.8 ;
     RECT  27.601 25.44 27.821 29.64 ;
     RECT  27.74 61.632 27.827 62.424 ;
     RECT  27.529 40.32 27.853 41.784 ;
     RECT  27.173 42.816 27.853 53.592 ;
     RECT  27.601 30.72 27.877 38.52 ;
     RECT  27.853 40.32 27.877 53.592 ;
     RECT  27.601 20.304 27.925 21.096 ;
     RECT  27.353 18.048 27.961 18.072 ;
     RECT  27.877 30.72 27.964 38.664 ;
     RECT  27.877 39.792 27.964 53.592 ;
     RECT  27.637 55.152 27.965 60.456 ;
     RECT  27.964 39.84 28.001 53.592 ;
     RECT  27.925 19.344 28.033 21.096 ;
     RECT  27.821 25.44 28.037 29.064 ;
     RECT  27.529 6.96 28.069 11.784 ;
     RECT  27.965 55.152 28.073 59.88 ;
     RECT  27.964 30.72 28.145 38.52 ;
     RECT  27.425 3.12 28.213 3.144 ;
     RECT  28.213 3.12 28.249 3.624 ;
     RECT  27.137 4.704 28.249 5.544 ;
     RECT  28.145 30.72 28.429 36.264 ;
     RECT  28.249 3.12 28.453 5.544 ;
     RECT  28.033 19.344 28.465 21.432 ;
     RECT  27.529 15.984 28.609 16.008 ;
     RECT  27.827 61.632 28.645 61.944 ;
     RECT  28.037 25.44 28.681 25.848 ;
     RECT  27.961 17.904 28.933 18.072 ;
     RECT  28.465 19.344 28.933 21.816 ;
     RECT  28.609 15.984 28.969 16.296 ;
     RECT  28.453 3.12 29.005 5.928 ;
     RECT  28.069 6.96 29.005 12.504 ;
     RECT  28.073 55.824 29.005 59.88 ;
     RECT  28.645 60.912 29.005 61.944 ;
     RECT  28.969 15.936 29.041 16.296 ;
     RECT  28.037 27.6 29.041 29.064 ;
     RECT  28.429 30.672 29.041 36.264 ;
     RECT  29.005 55.824 29.077 61.944 ;
     RECT  29.005 3.12 29.185 12.504 ;
     RECT  28.933 17.904 29.221 21.816 ;
     RECT  27.673 22.8 29.221 23.592 ;
     RECT  28.145 37.584 29.221 38.52 ;
     RECT  28.001 39.84 29.221 46.152 ;
     RECT  28.681 25.2 29.257 25.848 ;
     RECT  29.041 27.6 29.257 36.264 ;
     RECT  29.221 17.904 29.269 23.592 ;
     RECT  29.257 25.2 29.269 36.264 ;
     RECT  29.077 55.152 29.329 61.944 ;
     RECT  29.185 3.12 29.408 13.128 ;
     RECT  29.041 14.736 29.408 16.296 ;
     RECT  29.269 17.904 29.408 36.264 ;
     RECT  29.221 37.584 29.408 46.152 ;
     RECT  28.001 47.136 29.408 53.592 ;
     RECT  29.329 54.672 29.408 61.944 ;
     RECT  29.408 2.148 29.512 62.652 ;
     RECT  29.512 2.418 29.704 62.382 ;
     RECT  29.704 5.136 29.765 11.16 ;
     RECT  29.704 19.584 30.233 23.688 ;
     RECT  29.765 5.136 30.341 10.92 ;
     RECT  29.704 25.008 30.341 45.576 ;
     RECT  29.704 16.608 30.413 18.456 ;
     RECT  30.341 25.056 30.557 45.576 ;
     RECT  29.704 3.36 30.709 4.104 ;
     RECT  29.704 14.736 30.733 15.288 ;
     RECT  30.709 2.832 30.755 4.104 ;
     RECT  30.733 14.304 30.769 15.288 ;
     RECT  30.413 16.608 30.809 18.264 ;
     RECT  30.755 2.832 30.845 3.528 ;
     RECT  29.704 12.48 30.877 13.128 ;
     RECT  30.557 25.104 30.877 45.576 ;
     RECT  29.704 46.8 30.877 61.944 ;
     RECT  30.233 19.584 30.881 23.16 ;
     RECT  30.341 9.792 30.953 10.92 ;
     RECT  30.877 25.104 31.025 62.184 ;
     RECT  31.025 39.84 31.061 62.184 ;
     RECT  31.025 25.104 31.205 38.808 ;
     RECT  30.809 16.752 31.241 18.264 ;
     RECT  30.769 14.304 31.309 15.48 ;
     RECT  31.309 14.208 31.457 15.48 ;
     RECT  30.845 2.832 31.493 2.856 ;
     RECT  31.061 39.936 31.493 62.184 ;
     RECT  31.205 25.104 31.529 30.456 ;
     RECT  30.881 19.968 31.601 23.16 ;
     RECT  31.601 19.968 31.637 22.296 ;
     RECT  31.529 25.104 31.709 30.36 ;
     RECT  31.237 11.328 31.741 11.352 ;
     RECT  30.877 12.48 31.741 13.224 ;
     RECT  31.457 14.208 31.745 14.472 ;
     RECT  31.457 15.456 31.813 15.48 ;
     RECT  31.745 14.352 31.853 14.472 ;
     RECT  31.813 15.456 31.885 15.576 ;
     RECT  31.493 58.608 31.907 62.184 ;
     RECT  31.741 11.328 31.909 13.224 ;
     RECT  31.637 19.968 31.925 21.816 ;
     RECT  31.205 31.68 31.925 38.808 ;
     RECT  31.909 11.328 31.955 13.272 ;
     RECT  31.925 34.944 31.961 38.808 ;
     RECT  31.493 39.936 31.961 57.624 ;
     RECT  31.241 16.896 32.033 18.264 ;
     RECT  31.907 60.816 32.069 62.184 ;
     RECT  31.925 31.68 32.177 33.624 ;
     RECT  30.341 5.136 32.195 8.808 ;
     RECT  32.195 5.136 32.281 8.184 ;
     RECT  32.033 16.896 32.284 18.024 ;
     RECT  31.955 11.808 32.285 13.272 ;
     RECT  31.907 58.608 32.285 59.832 ;
     RECT  31.925 20.016 32.321 21.72 ;
     RECT  31.709 25.104 32.357 28.824 ;
     RECT  30.953 9.792 32.425 10.248 ;
     RECT  31.885 15.456 32.461 15.624 ;
     RECT  32.177 31.68 32.461 33.384 ;
     RECT  31.961 36.912 32.465 38.808 ;
     RECT  31.961 39.936 32.465 40.584 ;
     RECT  31.709 30.336 32.497 30.36 ;
     RECT  32.461 31.392 32.497 33.384 ;
     RECT  32.465 39.936 32.497 39.96 ;
     RECT  31.961 42.096 32.497 57.624 ;
     RECT  32.321 20.16 32.524 21.72 ;
     RECT  32.461 15.408 32.569 15.624 ;
     RECT  32.285 11.952 32.609 13.272 ;
     RECT  32.497 30.336 32.645 33.384 ;
     RECT  32.425 9.648 32.725 10.248 ;
     RECT  32.524 20.4 32.789 21.72 ;
     RECT  32.725 9.648 32.812 10.488 ;
     RECT  32.785 3.312 32.821 3.336 ;
     RECT  32.281 4.752 32.821 8.184 ;
     RECT  31.853 14.352 32.857 14.376 ;
     RECT  32.569 15.408 32.857 15.72 ;
     RECT  32.497 42.096 32.861 58.536 ;
     RECT  31.961 34.944 32.929 35.736 ;
     RECT  32.581 23.232 33.001 23.256 ;
     RECT  32.069 61.44 33.005 62.184 ;
     RECT  32.929 34.944 33.013 35.784 ;
     RECT  32.465 36.912 33.013 38.76 ;
     RECT  32.857 14.352 33.073 15.72 ;
     RECT  33.005 61.44 33.145 61.896 ;
     RECT  32.821 3.312 33.149 8.184 ;
     RECT  32.861 42.096 33.149 56.28 ;
     RECT  32.285 59.568 33.185 59.832 ;
     RECT  33.001 22.752 33.244 23.784 ;
     RECT  32.357 25.104 33.289 25.176 ;
     RECT  33.073 30.096 33.329 30.12 ;
     RECT  33.145 60.816 33.329 61.896 ;
     RECT  32.609 12.48 33.349 13.272 ;
     RECT  33.073 14.352 33.349 15.864 ;
     RECT  32.357 26.208 33.398 28.824 ;
     RECT  33.349 12.48 33.433 15.864 ;
     RECT  32.284 16.896 33.433 16.92 ;
     RECT  33.398 26.256 33.433 28.824 ;
     RECT  32.645 31.2 33.433 33.384 ;
     RECT  33.013 34.944 33.433 38.76 ;
     RECT  32.497 39.84 33.433 39.96 ;
     RECT  33.433 12.48 33.437 16.92 ;
     RECT  33.289 25.056 33.473 25.176 ;
     RECT  32.284 18 33.505 18.024 ;
     RECT  32.789 21.648 33.541 21.72 ;
     RECT  33.244 22.752 33.541 22.776 ;
     RECT  33.149 3.744 33.545 8.184 ;
     RECT  33.433 31.2 33.545 33.48 ;
     RECT  33.433 34.944 33.545 39.96 ;
     RECT  33.545 38.16 33.577 39.96 ;
     RECT  32.861 57.552 33.577 58.536 ;
     RECT  33.185 59.568 33.577 59.592 ;
     RECT  33.505 18 33.613 19.368 ;
     RECT  33.545 31.2 33.613 33.048 ;
     RECT  33.545 34.944 33.613 36.936 ;
     RECT  33.577 38.16 33.644 40.584 ;
     RECT  33.361 2.544 33.653 2.568 ;
     RECT  32.812 9.648 33.653 9.864 ;
     RECT  33.437 12.48 33.653 13.176 ;
     RECT  33.329 61.44 33.653 61.896 ;
     RECT  33.613 34.368 33.689 36.936 ;
     RECT  33.613 18 33.761 19.8 ;
     RECT  33.653 12.48 33.793 13.128 ;
     RECT  33.437 14.64 33.829 16.92 ;
     RECT  33.761 18 33.829 18.312 ;
     RECT  33.829 14.64 33.833 18.312 ;
     RECT  33.644 38.16 33.937 40.968 ;
     RECT  33.545 3.744 34.117 6.84 ;
     RECT  33.577 57.552 34.117 59.592 ;
     RECT  33.613 31.104 34.153 33.048 ;
     RECT  33.149 42.576 34.189 56.28 ;
     RECT  34.117 57.36 34.189 59.592 ;
     RECT  33.433 26.256 34.261 28.968 ;
     RECT  34.22 10.896 34.297 10.92 ;
     RECT  33.244 23.76 34.333 23.784 ;
     RECT  33.653 61.44 34.333 61.656 ;
     RECT  34.297 10.896 34.405 11.256 ;
     RECT  33.793 12.336 34.405 13.128 ;
     RECT  34.261 26.256 34.405 29.784 ;
     RECT  34.153 30.912 34.405 33.048 ;
     RECT  34.189 42.576 34.405 59.592 ;
     RECT  34.333 60.576 34.405 61.656 ;
     RECT  34.333 23.76 34.453 24.504 ;
     RECT  33.653 9.84 34.549 9.864 ;
     RECT  34.405 10.896 34.549 13.128 ;
     RECT  34.549 9.84 34.657 13.128 ;
     RECT  33.689 34.368 34.693 35.784 ;
     RECT  33.689 36.912 34.693 36.936 ;
     RECT  34.453 23.76 34.729 25.128 ;
     RECT  34.405 26.256 34.729 33.048 ;
     RECT  34.693 34.368 34.729 37.176 ;
     RECT  33.541 21.648 34.801 22.776 ;
     RECT  34.729 23.76 34.801 37.176 ;
     RECT  34.117 2.784 34.808 6.84 ;
     RECT  33.545 8.16 34.808 8.184 ;
     RECT  34.657 9.84 34.808 13.224 ;
     RECT  33.833 15.312 34.808 18.312 ;
     RECT  33.761 19.344 34.808 19.8 ;
     RECT  34.801 21.648 34.808 37.176 ;
     RECT  33.937 38.16 34.808 41.4 ;
     RECT  34.405 42.576 34.808 61.656 ;
     RECT  34.808 2.148 34.912 62.652 ;
     RECT  34.912 2.418 35.104 62.382 ;
     RECT  35.104 15.312 35.129 16.92 ;
     RECT  35.104 9.792 35.201 13.368 ;
     RECT  35.104 22.272 35.237 32.472 ;
     RECT  35.104 5.04 35.267 6.84 ;
     RECT  35.201 9.792 35.345 9.864 ;
     RECT  35.267 6.288 35.381 6.84 ;
     RECT  35.129 16.56 35.381 16.92 ;
     RECT  35.104 18.384 35.381 20.712 ;
     RECT  35.237 24.192 35.381 32.472 ;
     RECT  35.381 16.896 35.453 16.92 ;
     RECT  35.104 46.848 35.489 61.656 ;
     RECT  35.489 46.848 35.597 55.8 ;
     RECT  35.381 24.192 35.669 28.536 ;
     RECT  35.237 22.272 35.705 23.064 ;
     RECT  35.267 5.04 35.891 5.208 ;
     RECT  35.104 2.784 35.957 2.808 ;
     RECT  35.201 10.896 35.957 13.368 ;
     RECT  35.705 22.56 35.957 23.064 ;
     RECT  35.104 38.16 35.993 45.288 ;
     RECT  35.993 38.256 36.029 45.288 ;
     RECT  35.489 56.976 36.097 61.656 ;
     RECT  35.381 18.384 36.133 19.848 ;
     RECT  35.669 24.336 36.137 28.536 ;
     RECT  35.381 29.664 36.137 32.472 ;
     RECT  36.097 56.976 36.137 61.944 ;
     RECT  35.104 36.816 36.169 36.936 ;
     RECT  36.133 18.24 36.205 19.848 ;
     RECT  35.957 10.944 36.209 13.368 ;
     RECT  36.209 11.424 36.277 13.368 ;
     RECT  35.129 15.312 36.277 15.336 ;
     RECT  36.137 56.976 36.281 59.736 ;
     RECT  35.104 33.552 36.284 35.784 ;
     RECT  36.169 36.816 36.284 36.984 ;
     RECT  35.381 6.816 36.313 6.84 ;
     RECT  36.137 32.256 36.313 32.472 ;
     RECT  36.284 33.552 36.313 36.984 ;
     RECT  36.277 11.424 36.364 13.896 ;
     RECT  36.137 60.864 36.373 61.944 ;
     RECT  36.277 15.312 36.421 15.72 ;
     RECT  36.313 32.256 36.421 36.984 ;
     RECT  36.029 39.744 36.421 45.288 ;
     RECT  36.364 11.424 36.425 13.368 ;
     RECT  36.137 29.664 36.425 31.176 ;
     RECT  36.373 60.864 36.46 62.424 ;
     RECT  36.137 26.112 36.467 28.536 ;
     RECT  35.597 46.848 36.533 55.032 ;
     RECT  35.957 22.56 36.569 22.776 ;
     RECT  36.467 26.112 36.569 28.008 ;
     RECT  36.425 11.568 36.641 13.368 ;
     RECT  36.641 11.568 36.677 12.504 ;
     RECT  36.569 22.752 36.721 22.776 ;
     RECT  35.345 9.84 36.745 9.864 ;
     RECT  36.241 21.408 36.781 21.432 ;
     RECT  36.137 24.336 36.817 25.128 ;
     RECT  36.205 17.616 36.821 19.848 ;
     RECT  36.677 11.76 36.857 12.504 ;
     RECT  36.857 12.48 36.893 12.504 ;
     RECT  36.781 21.072 36.893 21.432 ;
     RECT  36.425 30.672 36.929 31.176 ;
     RECT  36.817 7.92 36.997 7.944 ;
     RECT  36.421 15.12 37.001 15.72 ;
     RECT  36.029 38.256 37.033 38.52 ;
     RECT  36.421 39.744 37.033 45.336 ;
     RECT  36.313 6.816 37.045 6.888 ;
     RECT  36.821 17.616 37.073 18.408 ;
     RECT  36.997 7.92 37.105 7.992 ;
     RECT  36.745 9.12 37.105 9.864 ;
     RECT  36.929 30.72 37.105 31.176 ;
     RECT  36.421 32.256 37.105 37.032 ;
     RECT  37.033 38.256 37.141 45.336 ;
     RECT  37.105 30.72 37.177 37.032 ;
     RECT  37.141 38.256 37.177 45.864 ;
     RECT  36.893 21.408 37.217 21.432 ;
     RECT  36.533 47.136 37.253 55.032 ;
     RECT  37.045 6.528 37.285 6.888 ;
     RECT  37.105 7.92 37.285 9.864 ;
     RECT  36.281 57.072 37.285 59.736 ;
     RECT  36.425 29.664 37.321 29.688 ;
     RECT  37.073 17.616 37.325 18.264 ;
     RECT  37.177 30.72 37.325 45.864 ;
     RECT  35.891 5.04 37.381 5.064 ;
     RECT  37.285 6.528 37.381 10.2 ;
     RECT  37.285 56.88 37.393 59.736 ;
     RECT  36.46 60.864 37.393 61.944 ;
     RECT  37.325 17.712 37.397 18.264 ;
     RECT  37.381 5.04 37.501 10.2 ;
     RECT  36.817 24.096 37.501 25.128 ;
     RECT  36.569 26.112 37.501 27.912 ;
     RECT  37.501 24.096 37.541 27.912 ;
     RECT  37.253 47.136 37.649 52.92 ;
     RECT  37.501 4.512 37.667 10.2 ;
     RECT  37.321 2.832 37.724 2.856 ;
     RECT  37.001 15.12 37.763 15.336 ;
     RECT  37.724 2.832 37.793 3.384 ;
     RECT  37.793 3.36 37.811 3.384 ;
     RECT  37.393 56.88 37.82 61.944 ;
     RECT  37.325 32.256 37.825 45.864 ;
     RECT  37.253 54 37.861 55.032 ;
     RECT  37.825 32.256 37.865 45.912 ;
     RECT  37.82 56.688 37.9 61.944 ;
     RECT  37.9 58.8 37.969 61.944 ;
     RECT  37.541 24.096 37.973 24.504 ;
     RECT  37.973 24.096 38.081 24.12 ;
     RECT  37.573 21.648 38.113 21.96 ;
     RECT  37.321 29.568 38.113 29.688 ;
     RECT  37.621 12.528 38.149 12.552 ;
     RECT  37.681 16.56 38.149 16.584 ;
     RECT  37.667 4.512 38.153 9.672 ;
     RECT  38.153 8.16 38.189 9.672 ;
     RECT  37.865 32.256 38.189 42.744 ;
     RECT  38.189 8.256 38.225 9.672 ;
     RECT  37.541 25.632 38.257 27.912 ;
     RECT  38.113 29.088 38.257 29.688 ;
     RECT  37.861 54 38.257 55.512 ;
     RECT  37.9 56.688 38.257 57.768 ;
     RECT  38.257 25.632 38.293 29.688 ;
     RECT  37.325 30.72 38.293 31.176 ;
     RECT  37.609 13.536 38.297 13.56 ;
     RECT  38.153 4.512 38.332 7.032 ;
     RECT  37.397 17.712 38.401 17.736 ;
     RECT  38.113 21.648 38.405 22.104 ;
     RECT  38.149 16.416 38.437 16.584 ;
     RECT  37.649 47.568 38.437 52.92 ;
     RECT  38.257 54 38.437 57.768 ;
     RECT  38.405 21.936 38.441 22.104 ;
     RECT  38.293 25.632 38.441 31.176 ;
     RECT  38.441 25.632 38.545 29.016 ;
     RECT  37.969 58.8 38.579 61.992 ;
     RECT  38.149 12.24 38.581 12.552 ;
     RECT  38.437 16.416 38.581 16.68 ;
     RECT  38.401 17.712 38.581 18.216 ;
     RECT  38.581 16.416 38.585 18.216 ;
     RECT  38.581 12.24 38.617 12.792 ;
     RECT  38.332 5.664 38.621 7.032 ;
     RECT  37.865 43.968 38.653 45.912 ;
     RECT  38.225 8.448 38.657 9.672 ;
     RECT  38.653 43.968 38.689 46.104 ;
     RECT  38.437 47.568 38.689 57.768 ;
     RECT  38.585 16.416 38.725 17.16 ;
     RECT  38.725 16.32 38.729 17.16 ;
     RECT  36.821 19.584 38.729 19.848 ;
     RECT  38.189 32.256 38.801 42.648 ;
     RECT  38.689 43.968 38.801 57.768 ;
     RECT  38.579 59.808 38.801 61.992 ;
     RECT  38.801 61.968 38.837 61.992 ;
     RECT  38.621 5.664 38.873 6.84 ;
     RECT  38.801 56.448 38.905 57.768 ;
     RECT  38.579 58.8 38.905 58.824 ;
     RECT  38.801 43.968 38.909 53.016 ;
     RECT  38.617 11.952 38.941 12.792 ;
     RECT  38.657 8.736 38.945 9.672 ;
     RECT  38.801 32.256 38.945 35.352 ;
     RECT  38.873 5.664 38.981 6.792 ;
     RECT  38.909 43.968 38.981 52.776 ;
     RECT  38.945 8.928 39.013 9.672 ;
     RECT  38.545 25.248 39.053 29.016 ;
     RECT  38.801 54 39.053 55.272 ;
     RECT  38.729 16.32 39.089 17.064 ;
     RECT  38.981 43.968 39.121 45.912 ;
     RECT  37.763 15.12 39.157 15.144 ;
     RECT  39.089 16.32 39.157 16.872 ;
     RECT  38.801 36.384 39.193 42.648 ;
     RECT  39.121 43.824 39.193 45.912 ;
     RECT  39.157 15.12 39.301 16.872 ;
     RECT  39.157 2.784 39.337 2.808 ;
     RECT  38.332 4.512 39.337 4.584 ;
     RECT  38.441 30.048 39.481 31.176 ;
     RECT  38.945 32.256 39.481 34.2 ;
     RECT  39.337 2.784 39.517 4.584 ;
     RECT  38.441 21.936 39.769 21.96 ;
     RECT  38.981 5.664 39.788 6.552 ;
     RECT  38.729 19.632 39.805 19.656 ;
     RECT  38.905 56.448 39.841 58.824 ;
     RECT  39.517 2.688 39.913 4.584 ;
     RECT  39.913 2.64 39.949 4.584 ;
     RECT  39.788 5.616 39.949 6.552 ;
     RECT  39.769 21.936 39.949 22.296 ;
     RECT  39.949 2.64 39.985 6.552 ;
     RECT  38.981 47.04 39.985 52.776 ;
     RECT  39.733 24.48 40.021 24.504 ;
     RECT  39.985 2.544 40.057 6.552 ;
     RECT  39.949 21.936 40.069 22.776 ;
     RECT  39.985 47.04 40.093 53.064 ;
     RECT  40.093 47.04 40.129 53.208 ;
     RECT  40.057 2.544 40.208 6.888 ;
     RECT  39.013 8.928 40.208 10.104 ;
     RECT  38.941 11.136 40.208 12.792 ;
     RECT  39.301 14.496 40.208 16.872 ;
     RECT  38.585 18.144 40.208 18.216 ;
     RECT  39.805 19.632 40.208 19.896 ;
     RECT  40.069 21.936 40.208 22.968 ;
     RECT  40.021 23.952 40.208 24.504 ;
     RECT  39.053 25.536 40.208 29.016 ;
     RECT  39.481 30.048 40.208 34.2 ;
     RECT  38.945 35.184 40.208 35.352 ;
     RECT  39.193 36.384 40.208 45.912 ;
     RECT  40.129 47.04 40.208 53.304 ;
     RECT  39.053 54.432 40.208 55.272 ;
     RECT  39.841 56.256 40.208 58.824 ;
     RECT  38.801 59.808 40.208 60.888 ;
     RECT  40.208 2.148 40.312 62.652 ;
     RECT  40.312 2.418 40.504 62.382 ;
     RECT  40.504 19.632 40.529 20.904 ;
     RECT  40.504 22.176 40.643 24.168 ;
     RECT  40.504 25.536 40.643 29.016 ;
     RECT  40.504 33.648 40.709 33.672 ;
     RECT  40.504 10.08 40.781 10.68 ;
     RECT  40.504 58.128 40.781 60.744 ;
     RECT  40.643 25.536 40.817 28.824 ;
     RECT  40.504 35.04 40.853 54.504 ;
     RECT  40.853 38.496 40.925 54.504 ;
     RECT  40.504 2.544 40.961 7.224 ;
     RECT  40.781 58.944 40.997 60.744 ;
     RECT  40.997 59.808 41.033 60.744 ;
     RECT  40.643 23.856 41.068 24.168 ;
     RECT  40.853 35.04 41.075 37.464 ;
     RECT  40.781 10.08 41.105 10.44 ;
     RECT  40.504 15.168 41.123 16.008 ;
     RECT  41.123 15.984 41.177 16.008 ;
     RECT  41.075 35.136 41.177 37.464 ;
     RECT  41.177 35.136 41.213 35.256 ;
     RECT  40.961 2.544 41.249 4.152 ;
     RECT  40.925 38.496 41.321 40.728 ;
     RECT  40.504 55.488 41.357 56.28 ;
     RECT  41.177 36.24 41.429 37.464 ;
     RECT  40.529 19.632 41.465 20.616 ;
     RECT  41.429 36.48 41.537 37.464 ;
     RECT  40.961 5.184 41.557 7.224 ;
     RECT  41.357 56.256 41.573 56.28 ;
     RECT  41.557 5.184 41.681 7.944 ;
     RECT  40.504 13.056 41.681 13.08 ;
     RECT  41.465 19.632 41.681 19.896 ;
     RECT  41.105 10.416 41.717 10.44 ;
     RECT  40.504 18.576 41.749 18.6 ;
     RECT  40.817 26.064 41.789 28.824 ;
     RECT  41.749 18.576 41.821 19.128 ;
     RECT  41.321 40.704 41.861 40.728 ;
     RECT  41.068 23.952 41.893 24.168 ;
     RECT  40.504 11.952 41.933 11.976 ;
     RECT  41.789 26.064 41.933 26.76 ;
     RECT  41.893 23.952 41.969 24.648 ;
     RECT  41.969 24.624 42.001 24.648 ;
     RECT  41.321 38.496 42.005 39.336 ;
     RECT  41.033 59.808 42.037 60.312 ;
     RECT  40.643 22.176 42.041 22.776 ;
     RECT  40.504 8.976 42.077 9 ;
     RECT  42.001 24.624 42.149 24.696 ;
     RECT  41.537 36.48 42.149 37.32 ;
     RECT  41.857 10.848 42.179 10.872 ;
     RECT  41.821 18.432 42.217 19.128 ;
     RECT  41.789 27.888 42.217 28.824 ;
     RECT  42.037 59.76 42.253 60.456 ;
     RECT  41.213 35.184 42.293 35.256 ;
     RECT  41.677 16.224 42.361 16.68 ;
     RECT  40.504 30.912 42.397 32.472 ;
     RECT  42.133 9.648 42.401 9.672 ;
     RECT  42.041 22.176 42.401 22.2 ;
     RECT  41.249 2.544 42.437 4.104 ;
     RECT  42.397 30.912 42.469 32.76 ;
     RECT  42.253 58.368 42.505 60.456 ;
     RECT  42.437 2.544 42.509 2.616 ;
     RECT  42.217 23.328 42.617 23.352 ;
     RECT  42.469 30.144 42.617 32.76 ;
     RECT  42.505 63.36 42.649 63.384 ;
     RECT  42.149 36.528 42.725 37.32 ;
     RECT  42.217 27.888 42.755 29.064 ;
     RECT  41.681 5.904 42.757 7.944 ;
     RECT  42.721 12.528 42.757 12.552 ;
     RECT  42.649 63.312 42.757 63.384 ;
     RECT  42.217 17.712 42.793 19.128 ;
     RECT  42.617 30.144 42.797 32.472 ;
     RECT  42.437 3.696 42.829 4.104 ;
     RECT  42.757 5.28 42.829 8.664 ;
     RECT  42.361 15.36 42.829 16.68 ;
     RECT  42.793 17.712 42.829 19.272 ;
     RECT  42.505 58.368 42.829 60.648 ;
     RECT  42.005 39.264 42.833 39.336 ;
     RECT  42.757 63.312 42.898 63.816 ;
     RECT  42.829 57.6 42.905 60.648 ;
     RECT  42.757 12.528 42.937 12.888 ;
     RECT  42.829 15.36 42.941 19.272 ;
     RECT  42.833 39.264 42.977 39.288 ;
     RECT  42.898 63.264 43.004 63.816 ;
     RECT  42.937 12.48 43.009 12.888 ;
     RECT  41.933 26.304 43.013 26.76 ;
     RECT  40.925 41.76 43.081 54.504 ;
     RECT  43.004 62.736 43.109 63.816 ;
     RECT  43.081 40.608 43.117 54.504 ;
     RECT  42.905 60.432 43.121 60.648 ;
     RECT  43.009 12.48 43.153 13.032 ;
     RECT  43.013 26.304 43.153 26.328 ;
     RECT  42.941 15.36 43.157 15.384 ;
     RECT  42.755 28.512 43.157 29.064 ;
     RECT  43.109 62.64 43.192 63.816 ;
     RECT  42.941 16.656 43.225 19.272 ;
     RECT  43.153 12.336 43.229 13.032 ;
     RECT  42.149 24.672 43.265 24.696 ;
     RECT  43.117 40.608 43.301 54.696 ;
     RECT  42.797 30.48 43.337 32.472 ;
     RECT  43.301 40.608 43.337 46.392 ;
     RECT  43.153 26.256 43.373 26.328 ;
     RECT  43.261 14.448 43.405 14.856 ;
     RECT  43.225 16.656 43.441 19.368 ;
     RECT  43.157 28.512 43.445 29.016 ;
     RECT  42.905 57.6 43.513 59.256 ;
     RECT  43.192 62.592 43.517 63.816 ;
     RECT  43.229 12.336 43.589 12.984 ;
     RECT  43.517 62.592 43.589 63.24 ;
     RECT  42.509 2.592 43.621 2.616 ;
     RECT  42.829 3.696 43.621 8.664 ;
     RECT  42.293 35.184 43.657 35.208 ;
     RECT  43.589 12.336 43.661 12.552 ;
     RECT  43.621 2.592 43.697 8.664 ;
     RECT  43.405 14.112 43.697 14.856 ;
     RECT  43.301 47.376 43.697 54.696 ;
     RECT  43.525 64.656 43.697 64.68 ;
     RECT  43.337 40.608 43.733 41.4 ;
     RECT  43.697 47.376 43.733 54.504 ;
     RECT  43.589 62.592 43.769 62.664 ;
     RECT  43.697 3.072 43.837 8.664 ;
     RECT  43.297 38.208 43.837 38.232 ;
     RECT  43.513 57.552 43.837 59.256 ;
     RECT  43.657 35.184 43.945 35.496 ;
     RECT  43.697 14.448 43.985 14.856 ;
     RECT  43.729 25.056 44.021 25.656 ;
     RECT  43.297 60.96 44.021 61.224 ;
     RECT  43.733 40.752 44.093 41.4 ;
     RECT  43.337 42.432 44.093 46.392 ;
     RECT  43.081 9.936 44.161 9.96 ;
     RECT  42.725 36.528 44.161 36.552 ;
     RECT  43.837 37.824 44.161 38.232 ;
     RECT  43.945 34.608 44.269 35.496 ;
     RECT  44.161 36.528 44.269 38.232 ;
     RECT  44.093 42.48 44.269 46.392 ;
     RECT  43.733 47.376 44.269 54.408 ;
     RECT  43.661 12.336 44.305 12.504 ;
     RECT  43.337 32.304 44.413 32.472 ;
     RECT  43.441 16.656 44.417 19.992 ;
     RECT  44.417 16.656 44.453 17.784 ;
     RECT  44.413 32.304 44.485 33.096 ;
     RECT  44.453 17.664 44.489 17.784 ;
     RECT  43.769 62.592 44.489 62.616 ;
     RECT  44.485 32.016 44.497 33.096 ;
     RECT  44.417 19.008 44.521 19.992 ;
     RECT  44.521 19.008 44.561 20.52 ;
     RECT  44.489 17.76 44.633 17.784 ;
     RECT  43.837 57.024 44.633 59.256 ;
     RECT  44.633 58.128 44.665 59.256 ;
     RECT  44.161 9.936 44.701 10.248 ;
     RECT  44.633 57.024 44.701 57.096 ;
     RECT  44.269 42.48 44.737 54.408 ;
     RECT  44.701 9.936 44.773 10.776 ;
     RECT  43.985 14.448 44.773 14.808 ;
     RECT  44.449 22.272 44.773 22.296 ;
     RECT  44.269 34.608 44.773 38.232 ;
     RECT  44.701 39.408 44.773 39.432 ;
     RECT  44.773 9.936 44.809 10.92 ;
     RECT  44.305 11.904 44.809 12.504 ;
     RECT  43.837 3.072 44.845 8.856 ;
     RECT  43.765 27.696 44.845 27.72 ;
     RECT  44.773 34.608 44.845 39.432 ;
     RECT  44.665 58.128 44.845 59.448 ;
     RECT  44.497 32.016 44.881 32.472 ;
     RECT  44.561 20.4 44.917 20.52 ;
     RECT  44.593 23.904 44.917 23.928 ;
     RECT  44.021 25.056 44.917 25.08 ;
     RECT  44.845 33.6 44.917 39.432 ;
     RECT  44.701 56.976 44.953 57.096 ;
     RECT  44.845 2.832 44.989 8.856 ;
     RECT  44.809 9.936 44.989 12.504 ;
     RECT  44.845 27.696 44.989 27.96 ;
     RECT  44.881 31.968 45.013 32.472 ;
     RECT  44.989 2.832 45.025 12.504 ;
     RECT  44.773 13.776 45.025 14.808 ;
     RECT  44.773 22.272 45.025 22.536 ;
     RECT  44.917 23.904 45.025 25.08 ;
     RECT  45.169 55.488 45.205 55.512 ;
     RECT  44.953 56.832 45.205 57.096 ;
     RECT  43.445 28.992 45.241 29.016 ;
     RECT  43.337 30.48 45.241 30.504 ;
     RECT  45.013 31.92 45.241 32.472 ;
     RECT  44.989 26.88 45.349 27.96 ;
     RECT  45.241 28.992 45.349 30.504 ;
     RECT  45.025 2.832 45.421 14.808 ;
     RECT  45.025 22.272 45.445 25.08 ;
     RECT  45.241 31.488 45.493 32.472 ;
     RECT  44.917 33.6 45.493 39.624 ;
     RECT  45.349 26.88 45.565 30.504 ;
     RECT  45.493 31.488 45.565 39.624 ;
     RECT  45.421 2.256 45.608 14.808 ;
     RECT  44.453 16.656 45.608 16.68 ;
     RECT  44.561 19.008 45.608 19.224 ;
     RECT  44.917 20.4 45.608 21.144 ;
     RECT  45.445 22.272 45.608 25.704 ;
     RECT  45.565 26.88 45.608 39.624 ;
     RECT  44.093 40.752 45.608 41.256 ;
     RECT  44.737 42.48 45.608 54.456 ;
     RECT  45.205 55.488 45.608 57.096 ;
     RECT  44.845 58.128 45.608 59.496 ;
     RECT  44.021 61.2 45.608 61.224 ;
     RECT  45.608 2.148 45.712 62.652 ;
     RECT  45.712 2.256 45.904 62.382 ;
     RECT  45.904 22.272 45.965 24.456 ;
     RECT  45.904 17.616 46.109 20.952 ;
     RECT  45.904 2.256 46.145 11.256 ;
     RECT  46.145 2.256 46.173 10.632 ;
     RECT  46.109 20.928 46.325 20.952 ;
     RECT  45.965 22.272 46.325 24.408 ;
     RECT  46.109 17.616 46.333 19.944 ;
     RECT  45.904 26.784 46.361 61.608 ;
     RECT  46.361 26.784 46.397 53.88 ;
     RECT  46.325 23.328 46.541 24.408 ;
     RECT  46.325 22.272 46.577 22.296 ;
     RECT  46.397 28.272 46.613 53.88 ;
     RECT  46.333 17.616 46.739 19.8 ;
     RECT  45.904 12.48 46.897 12.504 ;
     RECT  45.904 14.112 46.897 14.472 ;
     RECT  46.739 18 46.937 19.8 ;
     RECT  46.361 54.912 47.009 61.608 ;
     RECT  46.613 37.344 47.045 53.88 ;
     RECT  46.173 2.64 47.081 10.632 ;
     RECT  46.541 23.664 47.081 24.408 ;
     RECT  46.613 28.272 47.123 36.216 ;
     RECT  46.897 12.48 47.149 14.472 ;
     RECT  47.081 23.712 47.189 24.408 ;
     RECT  46.933 15.6 47.221 15.624 ;
     RECT  46.397 26.784 47.365 26.808 ;
     RECT  47.149 12.432 47.401 14.472 ;
     RECT  47.045 43.056 47.509 53.88 ;
     RECT  47.009 54.912 47.509 60.984 ;
     RECT  47.401 12.336 47.581 14.472 ;
     RECT  47.221 15.6 47.581 16.248 ;
     RECT  47.509 43.056 47.693 60.984 ;
     RECT  47.581 12.336 47.797 16.248 ;
     RECT  47.081 2.688 47.833 10.632 ;
     RECT  47.797 12.336 47.833 16.296 ;
     RECT  47.833 2.688 47.845 10.92 ;
     RECT  47.761 0.432 47.905 0.456 ;
     RECT  46.937 18.24 47.905 19.8 ;
     RECT  47.693 55.248 47.909 60.984 ;
     RECT  47.845 2.688 47.941 10.968 ;
     RECT  47.833 12.192 47.941 16.296 ;
     RECT  47.045 37.344 47.977 42.072 ;
     RECT  47.123 29.424 47.989 36.216 ;
     RECT  47.977 37.248 47.989 42.072 ;
     RECT  47.905 0.144 48.049 0.456 ;
     RECT  47.905 17.664 48.085 19.8 ;
     RECT  47.941 2.688 48.229 16.296 ;
     RECT  48.049 0.096 48.265 0.456 ;
     RECT  48.229 2.64 48.265 16.296 ;
     RECT  48.085 17.616 48.265 19.8 ;
     RECT  48.049 23.136 48.265 23.16 ;
     RECT  47.365 24.48 48.265 24.504 ;
     RECT  48.013 20.832 48.269 20.856 ;
     RECT  48.265 23.136 48.301 24.504 ;
     RECT  47.123 28.272 48.301 28.296 ;
     RECT  48.301 22.224 48.305 24.504 ;
     RECT  48.301 27.888 48.341 28.296 ;
     RECT  48.265 2.64 48.409 19.8 ;
     RECT  47.989 29.424 48.445 42.072 ;
     RECT  47.693 43.056 48.445 54.12 ;
     RECT  48.445 29.424 48.467 54.12 ;
     RECT  48.373 20.976 48.481 21.192 ;
     RECT  48.305 22.224 48.481 23.976 ;
     RECT  48.481 20.976 48.485 23.976 ;
     RECT  48.467 29.424 48.485 33.048 ;
     RECT  48.409 25.2 48.553 25.224 ;
     RECT  47.365 26.736 48.553 26.808 ;
     RECT  48.265 0.096 48.589 0.552 ;
     RECT  48.485 29.424 48.589 32.904 ;
     RECT  48.485 20.976 48.593 23.88 ;
     RECT  48.593 22.224 48.629 23.88 ;
     RECT  48.553 25.2 48.661 26.808 ;
     RECT  48.341 27.888 48.661 27.912 ;
     RECT  48.593 20.976 48.701 21.192 ;
     RECT  48.661 25.2 48.809 27.912 ;
     RECT  48.467 36.672 48.841 54.12 ;
     RECT  47.909 55.248 48.841 60.408 ;
     RECT  48.809 25.92 48.881 27.912 ;
     RECT  48.409 1.728 48.947 19.8 ;
     RECT  48.589 0.096 48.997 0.6 ;
     RECT  48.947 1.728 48.997 17.976 ;
     RECT  48.841 36.672 49.031 60.408 ;
     RECT  48.947 18.96 49.061 19.8 ;
     RECT  48.467 34.08 49.091 35.496 ;
     RECT  48.997 0.096 49.097 17.976 ;
     RECT  49.031 36.672 49.097 60.456 ;
     RECT  49.061 18.96 49.105 19.464 ;
     RECT  48.589 28.944 49.34 32.904 ;
     RECT  48.701 20.976 49.385 21.096 ;
     RECT  49.097 36.672 49.421 49.56 ;
     RECT  49.34 28.848 49.427 32.904 ;
     RECT  49.427 28.944 49.457 32.904 ;
     RECT  49.097 50.64 49.489 60.456 ;
     RECT  48.661 61.584 49.489 61.608 ;
     RECT  49.489 50.64 49.523 61.608 ;
     RECT  49.091 34.272 49.525 35.496 ;
     RECT  49.421 36.672 49.525 45.816 ;
     RECT  49.523 52.416 49.565 61.608 ;
     RECT  49.457 28.944 49.571 30.84 ;
     RECT  48.881 25.92 49.637 27.096 ;
     RECT  49.571 28.944 49.781 30.408 ;
     RECT  49.097 0.096 49.811 0.6 ;
     RECT  49.781 28.944 49.853 28.968 ;
     RECT  49.811 0.192 50.099 0.6 ;
     RECT  49.457 31.872 50.101 32.904 ;
     RECT  50.099 0.384 50.137 0.6 ;
     RECT  49.097 1.728 50.137 17.928 ;
     RECT  48.629 22.272 50.137 23.88 ;
     RECT  49.421 46.848 50.137 49.56 ;
     RECT  49.523 50.64 50.137 51.432 ;
     RECT  49.385 20.976 50.281 21 ;
     RECT  50.137 22.176 50.281 23.88 ;
     RECT  50.101 31.872 50.281 33 ;
     RECT  50.137 0.384 50.353 17.928 ;
     RECT  49.105 18.96 50.353 19.032 ;
     RECT  50.281 20.592 50.353 21 ;
     RECT  50.281 22.176 50.353 24.552 ;
     RECT  49.525 34.272 50.353 45.816 ;
     RECT  50.353 0.384 50.461 19.032 ;
     RECT  50.353 20.592 50.461 24.552 ;
     RECT  50.353 34.224 50.749 45.816 ;
     RECT  50.137 46.848 50.749 51.432 ;
     RECT  50.749 34.224 50.785 51.432 ;
     RECT  49.565 52.416 50.785 61.128 ;
     RECT  49.781 30.096 50.813 30.408 ;
     RECT  49.637 25.92 50.857 25.944 ;
     RECT  49.637 27.072 50.857 27.096 ;
     RECT  50.461 0.384 50.893 24.552 ;
     RECT  50.281 31.872 50.965 33.24 ;
     RECT  50.893 0.384 51.001 24.648 ;
     RECT  51.001 0.384 51.008 24.744 ;
     RECT  50.857 25.92 51.008 27.096 ;
     RECT  50.965 28.512 51.008 28.536 ;
     RECT  50.813 29.664 51.008 30.408 ;
     RECT  50.965 31.68 51.008 33.24 ;
     RECT  50.785 34.224 51.008 61.176 ;
     RECT  51.008 0.384 51.059 62.652 ;
     RECT  51.059 1.632 51.112 62.652 ;
     RECT  51.059 0.384 51.113 0.504 ;
     RECT  51.112 1.632 51.251 62.382 ;
     RECT  51.251 1.728 51.304 62.382 ;
     RECT  51.304 26.64 51.443 27.096 ;
     RECT  51.304 28.512 51.443 30.792 ;
     RECT  51.304 1.728 51.473 21.144 ;
     RECT  51.443 29.04 51.587 30.792 ;
     RECT  51.304 35.472 51.797 59.208 ;
     RECT  51.797 56.976 51.833 59.208 ;
     RECT  51.833 57.024 51.905 59.208 ;
     RECT  51.587 30.384 52.013 30.792 ;
     RECT  51.304 32.016 52.013 33.192 ;
     RECT  51.473 2.256 52.057 21.144 ;
     RECT  51.797 35.472 52.193 55.56 ;
     RECT  51.721 0.048 52.211 0.216 ;
     RECT  51.304 22.224 52.3 25.176 ;
     RECT  51.304 60.672 52.453 61.608 ;
     RECT  51.587 29.04 52.481 29.064 ;
     RECT  52.211 0.048 52.499 0.072 ;
     RECT  52.453 60.672 52.499 62.184 ;
     RECT  52.193 35.472 52.517 55.272 ;
     RECT  52.499 60.672 52.589 61.128 ;
     RECT  52.013 32.448 52.621 33.192 ;
     RECT  52.621 32.448 52.801 33.576 ;
     RECT  52.499 62.16 52.805 62.184 ;
     RECT  52.3 22.224 52.837 25.08 ;
     RECT  52.517 36.288 52.841 55.272 ;
     RECT  51.905 57.024 52.873 58.152 ;
     RECT  51.905 59.184 52.873 59.208 ;
     RECT  52.589 60.912 52.913 61.128 ;
     RECT  52.801 30.192 52.981 30.36 ;
     RECT  52.801 32.448 53.017 34.248 ;
     RECT  52.873 57.024 53.053 59.208 ;
     RECT  52.841 37.584 53.093 55.272 ;
     RECT  53.017 32.304 53.161 34.248 ;
     RECT  52.057 2.256 53.165 21.096 ;
     RECT  52.837 22.176 53.201 25.08 ;
     RECT  52.981 30.192 53.201 30.408 ;
     RECT  51.443 26.736 53.377 27.096 ;
     RECT  53.161 32.304 53.449 34.968 ;
     RECT  53.053 57.024 53.485 59.304 ;
     RECT  53.377 26.496 53.557 27.096 ;
     RECT  53.485 57.024 53.557 59.592 ;
     RECT  53.557 25.632 53.603 27.096 ;
     RECT  53.093 42.576 53.633 55.272 ;
     RECT  53.564 0.048 53.651 0.072 ;
     RECT  53.165 4.704 53.669 21.096 ;
     RECT  53.603 25.632 53.669 25.656 ;
     RECT  53.633 42.576 53.669 48.984 ;
     RECT  53.557 56.736 53.669 59.592 ;
     RECT  53.669 7.392 53.701 21.096 ;
     RECT  53.201 22.176 53.701 24.552 ;
     RECT  53.701 7.392 53.741 24.552 ;
     RECT  53.603 26.736 53.741 27.096 ;
     RECT  52.841 36.384 53.809 36.504 ;
     RECT  53.093 37.584 53.809 41.544 ;
     RECT  53.633 50.112 53.845 55.272 ;
     RECT  53.669 56.736 53.845 57.192 ;
     RECT  53.845 50.112 53.849 57.192 ;
     RECT  53.845 0.48 53.909 0.504 ;
     RECT  53.909 0.48 53.993 0.552 ;
     RECT  53.165 2.256 54.061 3.72 ;
     RECT  53.809 36.384 54.097 41.544 ;
     RECT  54.061 2.208 54.133 3.72 ;
     RECT  53.669 4.704 54.133 6.312 ;
     RECT  53.669 58.896 54.137 59.592 ;
     RECT  53.201 30.336 54.277 30.408 ;
     RECT  53.449 31.632 54.277 34.968 ;
     RECT  53.993 0.48 54.353 0.504 ;
     RECT  54.133 2.208 54.419 6.312 ;
     RECT  53.669 42.576 54.425 45.816 ;
     RECT  54.097 35.952 54.493 41.544 ;
     RECT  52.913 61.104 54.565 61.128 ;
     RECT  53.809 62.16 54.565 62.184 ;
     RECT  54.277 30.336 54.605 34.968 ;
     RECT  54.565 61.104 54.637 62.184 ;
     RECT  53.849 55.248 54.673 57.192 ;
     RECT  54.419 2.784 54.709 6.312 ;
     RECT  53.741 7.392 54.709 22.776 ;
     RECT  53.741 24.336 54.709 24.552 ;
     RECT  54.709 24.336 54.745 24.888 ;
     RECT  53.741 27.072 54.755 27.096 ;
     RECT  54.709 2.784 54.757 22.776 ;
     RECT  54.137 58.896 54.853 59.304 ;
     RECT  54.757 2.784 54.857 23.112 ;
     RECT  53.669 46.848 54.961 48.984 ;
     RECT  53.849 50.112 54.961 54.216 ;
     RECT  54.493 35.952 54.995 41.592 ;
     RECT  54.605 30.336 54.997 32.328 ;
     RECT  54.637 60.384 55.073 62.184 ;
     RECT  54.997 29.664 55.081 32.328 ;
     RECT  54.605 33.312 55.141 34.968 ;
     RECT  54.995 35.952 55.141 39.624 ;
     RECT  54.425 43.104 55.141 45.816 ;
     RECT  54.961 46.848 55.141 54.216 ;
     RECT  54.853 58.608 55.181 59.304 ;
     RECT  55.181 58.896 55.213 59.304 ;
     RECT  55.073 60.384 55.213 61.752 ;
     RECT  55.081 30.048 55.325 32.328 ;
     RECT  54.857 18.672 55.433 23.112 ;
     RECT  55.141 33.312 55.433 39.624 ;
     RECT  54.857 2.784 55.465 17.688 ;
     RECT  55.436 0.048 55.523 0.072 ;
     RECT  54.997 28.464 55.537 28.488 ;
     RECT  54.995 40.608 55.573 41.592 ;
     RECT  55.141 43.104 55.573 54.216 ;
     RECT  55.573 40.608 55.717 54.216 ;
     RECT  54.673 55.248 55.717 57.624 ;
     RECT  55.325 32.304 56.221 32.328 ;
     RECT  55.433 33.312 56.221 34.104 ;
     RECT  55.465 2.688 56.293 17.688 ;
     RECT  54.745 24.336 56.293 24.936 ;
     RECT  55.213 58.896 56.293 61.752 ;
     RECT  56.293 2.592 56.408 17.688 ;
     RECT  55.433 18.816 56.408 23.112 ;
     RECT  56.293 24.192 56.408 24.936 ;
     RECT  55.573 26.256 56.408 26.28 ;
     RECT  55.537 27.696 56.408 28.488 ;
     RECT  55.325 30.048 56.408 31.224 ;
     RECT  56.221 32.304 56.408 34.104 ;
     RECT  55.433 35.28 56.408 39.624 ;
     RECT  55.717 40.608 56.408 57.624 ;
     RECT  56.293 58.752 56.408 61.752 ;
     RECT  56.408 2.148 56.473 62.652 ;
     RECT  56.473 1.728 56.512 62.652 ;
     RECT  56.512 1.728 56.704 62.472 ;
     RECT  56.704 1.728 56.819 19.944 ;
     RECT  56.704 32.448 56.819 55.224 ;
     RECT  56.819 32.448 56.837 55.176 ;
     RECT  56.704 21.024 56.845 27.912 ;
     RECT  56.704 28.992 57.251 31.368 ;
     RECT  56.401 0.576 57.395 0.6 ;
     RECT  56.845 21.504 57.413 27.912 ;
     RECT  57.251 28.992 57.413 29.64 ;
     RECT  56.837 32.448 57.521 54.888 ;
     RECT  57.413 21.504 57.593 27.768 ;
     RECT  57.593 21.648 57.665 23.88 ;
     RECT  56.819 2.208 57.683 19.944 ;
     RECT  56.704 56.256 57.74 57.192 ;
     RECT  56.704 58.656 57.74 61.08 ;
     RECT  57.74 56.256 57.827 61.08 ;
     RECT  57.251 30.816 57.877 31.368 ;
     RECT  57.521 32.448 57.877 33.912 ;
     RECT  57.593 25.056 57.989 27.768 ;
     RECT  56.704 62.448 57.989 62.472 ;
     RECT  57.521 35.136 58.093 54.888 ;
     RECT  57.827 56.256 58.093 57.192 ;
     RECT  57.683 2.256 58.115 19.944 ;
     RECT  57.973 0.096 58.241 0.552 ;
     RECT  58.115 2.784 58.259 19.944 ;
     RECT  57.827 58.656 58.345 61.08 ;
     RECT  58.241 0.096 58.412 0.12 ;
     RECT  57.413 29.568 58.453 29.64 ;
     RECT  58.093 35.136 58.457 57.192 ;
     RECT  58.412 0.048 58.499 0.12 ;
     RECT  58.259 2.928 58.525 19.944 ;
     RECT  57.989 26.64 58.529 27.768 ;
     RECT  57.665 21.648 58.547 22.872 ;
     RECT  57.665 23.856 58.556 23.88 ;
     RECT  57.989 25.056 58.556 25.08 ;
     RECT  57.877 30.816 58.561 33.912 ;
     RECT  58.457 35.136 58.561 41.784 ;
     RECT  58.345 58.656 58.595 61.704 ;
     RECT  58.525 2.928 58.601 19.992 ;
     RECT  58.561 30.816 58.633 41.784 ;
     RECT  58.595 59.424 58.636 61.704 ;
     RECT  58.556 23.856 58.643 25.08 ;
     RECT  58.633 30.768 58.693 41.784 ;
     RECT  58.499 0.096 58.709 0.12 ;
     RECT  58.547 22.032 58.709 22.872 ;
     RECT  58.457 43.104 58.709 57.192 ;
     RECT  58.636 59.472 58.709 61.704 ;
     RECT  58.709 22.56 58.853 22.872 ;
     RECT  58.709 43.2 58.853 57.192 ;
     RECT  58.601 19.344 58.885 19.992 ;
     RECT  58.709 59.472 59.033 60.264 ;
     RECT  58.453 29.088 59.209 29.64 ;
     RECT  58.693 30.672 59.209 41.784 ;
     RECT  58.643 25.056 59.321 25.08 ;
     RECT  59.209 29.088 59.321 41.784 ;
     RECT  58.601 2.928 59.357 18.312 ;
     RECT  58.885 19.344 59.363 20.568 ;
     RECT  59.357 2.928 59.459 17.88 ;
     RECT  58.643 23.856 59.461 23.928 ;
     RECT  59.459 2.928 59.605 17.112 ;
     RECT  58.853 55.488 59.605 57.192 ;
     RECT  59.363 19.488 59.645 20.568 ;
     RECT  59.321 29.568 59.645 41.784 ;
     RECT  59.605 2.256 59.689 17.112 ;
     RECT  58.529 26.64 59.713 27.72 ;
     RECT  59.689 2.832 59.747 17.112 ;
     RECT  58.853 43.2 59.749 54.312 ;
     RECT  59.749 43.008 59.893 54.312 ;
     RECT  59.281 61.872 59.893 62.184 ;
     RECT  59.893 43.008 59.929 54.36 ;
     RECT  59.929 42.864 60.037 54.36 ;
     RECT  59.605 55.488 60.037 57.24 ;
     RECT  59.645 36.96 60.041 41.784 ;
     RECT  59.747 2.832 60.077 8.184 ;
     RECT  60.037 42.864 60.113 57.24 ;
     RECT  59.033 59.472 60.145 60.024 ;
     RECT  59.461 23.664 60.149 23.928 ;
     RECT  60.077 2.832 60.221 2.856 ;
     RECT  60.113 43.248 60.253 57.24 ;
     RECT  60.041 37.104 60.277 41.784 ;
     RECT  60.217 24.864 60.289 24.888 ;
     RECT  60.253 43.248 60.289 57.624 ;
     RECT  60.145 59.472 60.361 60.456 ;
     RECT  59.645 19.488 60.397 20.328 ;
     RECT  58.853 22.56 60.469 22.632 ;
     RECT  60.149 23.664 60.469 23.688 ;
     RECT  60.289 24.864 60.473 24.936 ;
     RECT  59.645 29.568 60.509 35.928 ;
     RECT  59.893 61.584 60.509 62.184 ;
     RECT  60.509 34.752 60.515 35.928 ;
     RECT  60.509 29.568 60.653 33.624 ;
     RECT  59.747 9.408 60.689 16.584 ;
     RECT  60.509 61.584 60.689 61.8 ;
     RECT  60.689 9.408 60.761 14.904 ;
     RECT  60.277 37.104 60.761 42.072 ;
     RECT  60.289 43.248 60.761 57.768 ;
     RECT  60.361 59.328 60.865 60.456 ;
     RECT  59.713 26.64 60.997 28.584 ;
     RECT  60.653 29.568 60.997 30.408 ;
     RECT  60.397 18.96 61.009 20.328 ;
     RECT  60.469 21.6 61.009 23.688 ;
     RECT  60.761 37.296 61.153 42.072 ;
     RECT  60.077 4.464 61.189 8.184 ;
     RECT  60.689 15.936 61.189 16.584 ;
     RECT  60.901 2.496 61.261 2.52 ;
     RECT  61.189 4.416 61.297 8.376 ;
     RECT  60.761 9.408 61.297 14.808 ;
     RECT  61.189 15.936 61.333 17.544 ;
     RECT  61.009 18.96 61.333 23.688 ;
     RECT  60.761 43.824 61.369 57.768 ;
     RECT  60.473 24.912 61.513 24.936 ;
     RECT  60.997 26.64 61.513 30.408 ;
     RECT  61.261 2.256 61.621 3.144 ;
     RECT  61.297 4.416 61.621 14.808 ;
     RECT  61.333 15.936 61.621 23.688 ;
     RECT  61.513 24.912 61.621 30.408 ;
     RECT  60.865 58.944 61.621 60.456 ;
     RECT  60.689 61.584 61.621 61.608 ;
     RECT  60.515 34.752 61.693 35.448 ;
     RECT  61.693 34.752 61.765 35.496 ;
     RECT  61.621 2.256 61.808 14.808 ;
     RECT  61.621 15.936 61.808 30.408 ;
     RECT  60.653 31.392 61.808 33.336 ;
     RECT  61.765 34.752 61.808 35.544 ;
     RECT  61.153 37.296 61.808 42.744 ;
     RECT  61.369 43.824 61.808 57.864 ;
     RECT  61.621 58.944 61.808 61.608 ;
     RECT  61.808 2.148 61.912 62.652 ;
     RECT  61.912 2.418 62.104 62.382 ;
     RECT  62.104 7.392 62.129 13.08 ;
     RECT  62.104 55.296 62.129 58.728 ;
     RECT  62.104 2.496 62.165 5.592 ;
     RECT  62.129 11.424 62.165 13.08 ;
     RECT  62.104 21.072 62.237 27.912 ;
     RECT  62.237 21.072 62.309 26.136 ;
     RECT  62.104 18.72 62.345 19.944 ;
     RECT  62.309 21.072 62.387 24.648 ;
     RECT  62.165 12 62.417 13.08 ;
     RECT  62.129 55.296 62.489 55.704 ;
     RECT  62.104 60 62.597 60.984 ;
     RECT  62.237 27.888 62.771 27.912 ;
     RECT  62.104 28.992 62.771 52.344 ;
     RECT  62.165 2.592 62.777 5.592 ;
     RECT  62.597 60.624 62.777 60.984 ;
     RECT  62.129 57.12 62.813 58.728 ;
     RECT  62.771 28.992 62.957 34.152 ;
     RECT  62.771 35.136 62.957 52.344 ;
     RECT  62.957 29.232 63.052 34.152 ;
     RECT  62.345 18.768 63.097 19.944 ;
     RECT  62.387 21.072 63.097 22.824 ;
     RECT  62.813 57.12 63.097 57.864 ;
     RECT  62.777 60.624 63.173 60.888 ;
     RECT  62.129 7.392 63.205 10.44 ;
     RECT  62.104 14.4 63.205 14.808 ;
     RECT  62.104 16.032 63.205 17.688 ;
     RECT  62.104 53.376 63.241 53.88 ;
     RECT  62.957 42.24 63.281 52.344 ;
     RECT  63.205 13.68 63.317 17.688 ;
     RECT  63.052 31.68 63.389 34.152 ;
     RECT  63.317 13.68 63.497 17.592 ;
     RECT  62.489 55.68 63.497 55.704 ;
     RECT  62.777 2.592 63.533 5.4 ;
     RECT  62.957 35.136 63.569 41.208 ;
     RECT  63.533 2.688 63.605 5.4 ;
     RECT  63.205 7.392 63.605 10.968 ;
     RECT  63.097 56.736 63.709 57.864 ;
     RECT  63.097 18.768 63.745 22.824 ;
     RECT  63.605 8.16 63.749 10.968 ;
     RECT  63.421 58.992 63.749 59.016 ;
     RECT  63.389 31.92 63.817 34.152 ;
     RECT  63.569 35.136 63.817 39.96 ;
     RECT  63.749 9.024 63.829 10.968 ;
     RECT  62.417 12 63.829 12.552 ;
     RECT  63.497 14.352 63.857 17.592 ;
     RECT  63.745 18.576 63.857 22.824 ;
     RECT  62.309 25.632 63.877 26.136 ;
     RECT  63.277 28.08 63.877 28.104 ;
     RECT  63.877 25.632 63.889 26.52 ;
     RECT  63.857 18.576 63.893 21.096 ;
     RECT  63.893 19.632 63.901 21.096 ;
     RECT  63.829 9.024 63.916 12.552 ;
     RECT  63.857 22.176 63.916 22.824 ;
     RECT  63.889 25.056 63.925 26.52 ;
     RECT  63.916 9.024 63.929 11.016 ;
     RECT  62.387 23.808 63.961 23.832 ;
     RECT  63.925 24.96 63.961 26.52 ;
     RECT  63.877 27.84 63.961 28.104 ;
     RECT  63.857 14.352 64.001 17.544 ;
     RECT  63.173 60.624 64.033 60.648 ;
     RECT  63.961 23.808 64.069 26.52 ;
     RECT  63.961 27.648 64.069 28.104 ;
     RECT  63.241 53.376 64.073 54.6 ;
     RECT  64.069 23.808 64.145 28.104 ;
     RECT  63.052 29.232 64.145 30.072 ;
     RECT  63.709 55.92 64.177 57.864 ;
     RECT  63.916 12.528 64.253 12.552 ;
     RECT  64.145 24.624 64.321 28.104 ;
     RECT  63.929 9.072 64.325 11.016 ;
     RECT  63.817 31.92 64.325 39.96 ;
     RECT  63.605 2.976 64.357 5.4 ;
     RECT  64.325 9.168 64.396 11.016 ;
     RECT  64.357 2.976 64.397 5.64 ;
     RECT  64.325 32.976 64.433 39.96 ;
     RECT  64.397 2.976 64.469 4.488 ;
     RECT  64.393 30.768 64.505 30.792 ;
     RECT  64.433 36.048 64.537 39.96 ;
     RECT  64.396 9.408 64.541 11.016 ;
     RECT  64.469 4.224 64.577 4.488 ;
     RECT  64.001 14.352 64.609 16.584 ;
     RECT  64.177 55.92 64.609 58.008 ;
     RECT  64.469 2.976 64.649 3 ;
     RECT  64.433 32.976 64.649 33.528 ;
     RECT  64.577 4.224 64.685 4.44 ;
     RECT  64.649 33.072 64.685 33.528 ;
     RECT  64.541 10.128 64.721 11.016 ;
     RECT  63.569 41.088 64.741 41.112 ;
     RECT  63.853 59.232 64.753 59.352 ;
     RECT  64.033 60.384 64.753 60.648 ;
     RECT  64.537 36.048 64.789 40.104 ;
     RECT  64.741 41.088 64.789 41.208 ;
     RECT  63.281 42.24 64.861 52.056 ;
     RECT  64.685 4.416 64.865 4.44 ;
     RECT  63.901 19.632 64.897 20.328 ;
     RECT  64.753 59.232 64.897 60.648 ;
     RECT  64.321 24.624 64.901 28.152 ;
     RECT  64.861 42.24 64.933 52.344 ;
     RECT  64.073 53.376 64.933 54.36 ;
     RECT  64.681 2.88 64.969 2.904 ;
     RECT  64.897 19.584 64.969 20.328 ;
     RECT  64.901 24.624 65.009 25.56 ;
     RECT  64.609 55.68 65.041 58.008 ;
     RECT  64.609 14.256 65.045 16.584 ;
     RECT  64.933 6.672 65.077 6.696 ;
     RECT  64.789 36.048 65.077 41.208 ;
     RECT  64.933 42.24 65.077 54.36 ;
     RECT  63.916 22.608 65.153 22.824 ;
     RECT  65.045 14.448 65.261 16.584 ;
     RECT  64.721 10.704 65.293 11.016 ;
     RECT  65.153 22.608 65.329 22.632 ;
     RECT  64.429 13.056 65.365 13.08 ;
     RECT  63.893 18.576 65.405 18.6 ;
     RECT  64.433 34.56 65.437 34.824 ;
     RECT  65.041 55.68 65.461 58.152 ;
     RECT  64.897 59.232 65.461 61.176 ;
     RECT  64.145 29.232 65.509 29.784 ;
     RECT  65.437 34.56 65.509 34.872 ;
     RECT  65.077 36.048 65.513 54.36 ;
     RECT  65.461 55.68 65.549 61.176 ;
     RECT  64.397 5.616 65.605 5.64 ;
     RECT  65.077 6.672 65.605 7.224 ;
     RECT  64.901 26.784 65.617 28.152 ;
     RECT  65.509 29.232 65.617 30.6 ;
     RECT  65.617 26.784 65.621 30.6 ;
     RECT  65.513 36.048 65.621 54.312 ;
     RECT  65.605 5.616 65.651 7.224 ;
     RECT  65.651 5.664 65.725 7.224 ;
     RECT  65.329 22.224 65.725 22.632 ;
     RECT  65.621 36.048 65.729 41.112 ;
     RECT  64.969 2.304 65.765 2.904 ;
     RECT  65.725 22.08 65.797 22.632 ;
     RECT  65.009 24.624 65.873 24.792 ;
     RECT  65.756 4.512 65.948 4.536 ;
     RECT  65.293 10.704 65.977 11.688 ;
     RECT  65.365 12.96 65.977 13.08 ;
     RECT  65.765 2.832 66.049 2.904 ;
     RECT  65.948 4.368 66.049 4.536 ;
     RECT  64.969 19.584 66.049 20.424 ;
     RECT  65.797 21.744 66.049 22.632 ;
     RECT  64.685 33.072 66.049 33.384 ;
     RECT  65.509 34.56 66.049 34.92 ;
     RECT  65.549 55.68 66.053 58.728 ;
     RECT  65.725 5.664 66.085 7.464 ;
     RECT  65.977 10.704 66.085 13.08 ;
     RECT  66.085 10.128 66.095 13.08 ;
     RECT  65.261 14.448 66.095 16.056 ;
     RECT  65.549 60.288 66.121 61.176 ;
     RECT  65.621 30.048 66.125 30.6 ;
     RECT  66.049 2.832 66.131 4.536 ;
     RECT  64.325 31.92 66.373 31.944 ;
     RECT  66.265 9.024 66.445 9.048 ;
     RECT  66.095 10.128 66.445 16.056 ;
     RECT  66.049 19.584 66.469 22.632 ;
     RECT  66.085 5.664 66.476 7.656 ;
     RECT  66.131 2.88 66.517 4.536 ;
     RECT  66.469 19.584 66.517 22.728 ;
     RECT  66.517 2.88 66.625 4.584 ;
     RECT  65.329 17.472 66.625 17.496 ;
     RECT  66.373 31.776 66.625 31.944 ;
     RECT  66.476 5.664 66.661 7.8 ;
     RECT  66.517 19.584 66.661 22.872 ;
     RECT  66.661 5.664 66.733 7.992 ;
     RECT  66.445 9.024 66.733 16.056 ;
     RECT  66.625 17.472 66.733 17.64 ;
     RECT  66.661 19.584 66.733 23.592 ;
     RECT  65.621 42.24 66.733 54.312 ;
     RECT  65.729 36.096 66.841 41.112 ;
     RECT  66.733 42.24 66.841 54.36 ;
     RECT  66.049 33.072 66.877 34.92 ;
     RECT  66.625 2.88 66.985 4.68 ;
     RECT  66.733 5.664 66.985 16.056 ;
     RECT  66.625 31.776 66.985 31.992 ;
     RECT  66.985 2.88 67.093 16.056 ;
     RECT  66.733 17.088 67.093 17.64 ;
     RECT  66.125 30.576 67.129 30.6 ;
     RECT  66.053 55.68 67.201 57.192 ;
     RECT  67.093 2.88 67.208 17.64 ;
     RECT  66.733 19.056 67.208 23.592 ;
     RECT  65.873 24.768 67.208 24.792 ;
     RECT  65.621 26.784 67.208 28.968 ;
     RECT  67.129 30.576 67.208 30.648 ;
     RECT  66.985 31.776 67.208 32.04 ;
     RECT  66.877 33.024 67.208 34.92 ;
     RECT  66.841 36.096 67.208 54.36 ;
     RECT  67.201 55.68 67.208 57.432 ;
     RECT  66.053 58.512 67.208 58.728 ;
     RECT  66.121 60.288 67.208 62.04 ;
     RECT  67.208 2.148 67.312 62.652 ;
     RECT  67.312 2.148 67.345 62.382 ;
     RECT  67.345 1.728 67.504 62.382 ;
     RECT  66.697 0.624 67.525 0.648 ;
     RECT  67.525 0.576 67.597 0.648 ;
     RECT  67.504 1.728 67.597 1.8 ;
     RECT  67.504 38.112 67.601 57.432 ;
     RECT  67.504 2.832 67.619 22.536 ;
     RECT  67.619 4.176 67.673 22.536 ;
     RECT  67.673 5.904 67.715 22.536 ;
     RECT  67.715 5.952 67.745 22.536 ;
     RECT  67.745 12.768 67.781 22.536 ;
     RECT  67.504 60.288 67.811 62.184 ;
     RECT  67.597 0.576 67.849 1.8 ;
     RECT  67.781 12.768 67.853 21.144 ;
     RECT  67.504 28.992 67.853 37.032 ;
     RECT  67.601 38.112 67.853 53.88 ;
     RECT  67.504 58.512 67.859 59.256 ;
     RECT  67.853 38.112 67.889 49.176 ;
     RECT  67.853 18.192 67.897 21.144 ;
     RECT  67.811 60.288 67.961 61.416 ;
     RECT  67.897 18.72 68.033 21.144 ;
     RECT  67.781 22.176 68.141 22.536 ;
     RECT  67.849 0.528 68.147 1.8 ;
     RECT  67.853 12.768 68.249 17.16 ;
     RECT  68.033 18.72 68.321 20.472 ;
     RECT  67.859 58.704 68.321 59.256 ;
     RECT  67.601 55.296 68.357 57.432 ;
     RECT  68.147 1.104 68.533 1.8 ;
     RECT  68.249 12.768 68.537 17.064 ;
     RECT  67.504 26.784 68.537 26.808 ;
     RECT  67.853 50.4 68.573 53.88 ;
     RECT  67.504 23.568 68.629 23.592 ;
     RECT  67.853 28.992 68.629 32.232 ;
     RECT  67.673 4.176 68.677 4.92 ;
     RECT  67.745 5.952 68.677 11.496 ;
     RECT  68.537 12.768 68.723 13.224 ;
     RECT  68.537 14.352 68.789 17.064 ;
     RECT  68.629 28.944 68.789 32.232 ;
     RECT  67.961 60.384 68.821 61.416 ;
     RECT  68.677 4.176 68.857 11.496 ;
     RECT  68.723 12.768 68.857 13.176 ;
     RECT  67.504 27.888 68.893 27.912 ;
     RECT  68.789 28.944 68.893 28.968 ;
     RECT  67.889 38.112 68.897 48.984 ;
     RECT  68.141 22.512 68.929 22.536 ;
     RECT  68.629 23.568 68.929 24.12 ;
     RECT  68.893 27.888 68.929 28.968 ;
     RECT  68.897 40.848 68.929 48.984 ;
     RECT  68.321 18.72 68.969 20.328 ;
     RECT  68.969 18.816 69.005 20.328 ;
     RECT  68.929 40.848 69.005 49.368 ;
     RECT  68.317 0.096 69.011 0.12 ;
     RECT  68.533 1.104 69.107 2.28 ;
     RECT  67.853 33.312 69.113 37.032 ;
     RECT  68.357 55.296 69.113 57.192 ;
     RECT  68.321 58.704 69.145 58.824 ;
     RECT  69.113 33.552 69.149 37.032 ;
     RECT  68.929 22.512 69.217 24.888 ;
     RECT  69.217 21.792 69.289 24.888 ;
     RECT  69.217 25.872 69.289 25.896 ;
     RECT  68.789 30.048 69.469 32.232 ;
     RECT  69.469 30.048 69.509 32.472 ;
     RECT  68.821 60.384 69.587 61.896 ;
     RECT  69.509 30.192 69.625 32.472 ;
     RECT  69.587 60.384 69.628 61.656 ;
     RECT  69.289 21.792 69.649 25.896 ;
     RECT  68.929 27.504 69.649 28.968 ;
     RECT  69.005 41.088 69.733 49.368 ;
     RECT  68.573 50.4 69.733 53.4 ;
     RECT  69.733 41.088 69.779 53.4 ;
     RECT  68.857 4.176 69.781 13.176 ;
     RECT  68.789 14.352 69.781 16.92 ;
     RECT  69.781 4.176 69.793 16.92 ;
     RECT  69.628 61.2 69.833 61.656 ;
     RECT  69.145 58.608 69.865 58.824 ;
     RECT  69.793 4.176 69.868 17.64 ;
     RECT  69.113 55.68 69.877 57.192 ;
     RECT  69.865 58.608 69.877 60.072 ;
     RECT  69.877 55.68 69.905 60.072 ;
     RECT  69.149 36.96 70.045 37.032 ;
     RECT  68.897 38.112 70.045 39.624 ;
     RECT  69.868 4.176 70.115 13.176 ;
     RECT  69.107 1.728 70.157 2.28 ;
     RECT  70.117 0.576 70.201 0.6 ;
     RECT  70.045 36.96 70.261 39.624 ;
     RECT  70.261 36.864 70.297 39.624 ;
     RECT  70.115 4.176 70.3 13.08 ;
     RECT  69.005 18.864 70.333 20.328 ;
     RECT  69.649 21.792 70.333 28.968 ;
     RECT  69.625 30.336 70.369 32.472 ;
     RECT  70.157 1.728 70.373 1.8 ;
     RECT  69.868 14.448 70.373 17.64 ;
     RECT  70.333 18.768 70.403 28.968 ;
     RECT  70.297 36.864 70.405 39.768 ;
     RECT  69.779 41.088 70.405 49.08 ;
     RECT  69.779 50.16 70.405 53.4 ;
     RECT  69.829 54.672 70.405 54.696 ;
     RECT  70.3 4.176 70.409 11.976 ;
     RECT  70.403 18.768 70.417 19.512 ;
     RECT  70.369 30.336 70.445 32.568 ;
     RECT  70.403 21.072 70.481 28.968 ;
     RECT  70.373 1.728 70.588 1.752 ;
     RECT  70.405 36.864 70.697 49.08 ;
     RECT  70.445 30.336 70.729 30.696 ;
     RECT  70.405 50.16 70.801 54.696 ;
     RECT  70.409 4.176 70.805 9.672 ;
     RECT  70.801 50.112 70.945 54.696 ;
     RECT  69.905 55.728 70.945 60.072 ;
     RECT  70.373 17.616 70.949 17.64 ;
     RECT  70.481 21.648 71.021 28.968 ;
     RECT  69.833 61.248 71.021 61.656 ;
     RECT  70.729 30.144 71.053 30.696 ;
     RECT  69.149 33.552 71.089 35.784 ;
     RECT  70.697 36.864 71.089 48.792 ;
     RECT  70.373 14.448 71.093 16.056 ;
     RECT  70.945 50.112 71.129 60.072 ;
     RECT  71.089 33.552 71.165 48.792 ;
     RECT  70.3 13.056 71.197 13.08 ;
     RECT  71.093 14.448 71.197 14.472 ;
     RECT  71.129 53.04 71.197 60.072 ;
     RECT  71.021 61.248 71.197 61.56 ;
     RECT  70.805 4.512 71.237 9.672 ;
     RECT  71.021 24.288 71.273 28.968 ;
     RECT  71.165 35.184 71.273 46.008 ;
     RECT  71.197 13.056 71.281 14.472 ;
     RECT  71.021 21.648 71.309 23.304 ;
     RECT  70.445 31.92 71.341 32.568 ;
     RECT  71.165 33.552 71.341 34.104 ;
     RECT  71.053 30.048 71.381 30.696 ;
     RECT  71.281 13.056 71.597 13.08 ;
     RECT  71.485 2.832 71.605 2.856 ;
     RECT  70.409 10.992 71.665 11.976 ;
     RECT  71.273 27.072 71.701 28.968 ;
     RECT  71.381 30.048 71.701 30.36 ;
     RECT  71.809 3.888 71.917 3.912 ;
     RECT  71.165 47.136 72.037 48.792 ;
     RECT  71.129 50.112 72.037 51.912 ;
     RECT  70.417 19.344 72.097 19.512 ;
     RECT  72.037 47.136 72.133 51.912 ;
     RECT  72.133 47.136 72.169 52.008 ;
     RECT  71.197 53.04 72.169 61.56 ;
     RECT  72.097 18.768 72.264 19.512 ;
     RECT  71.953 20.688 72.264 20.712 ;
     RECT  71.237 5.04 72.277 9.672 ;
     RECT  72.264 18.768 72.277 20.712 ;
     RECT  71.309 22.608 72.277 23.304 ;
     RECT  71.917 3.84 72.313 3.912 ;
     RECT  72.277 5.04 72.313 9.864 ;
     RECT  71.605 2.256 72.349 2.856 ;
     RECT  72.313 3.84 72.349 9.864 ;
     RECT  71.093 15.936 72.349 16.056 ;
     RECT  71.989 17.376 72.349 17.4 ;
     RECT  72.277 22.608 72.349 23.4 ;
     RECT  72.349 15.936 72.373 17.4 ;
     RECT  72.349 2.256 72.421 9.864 ;
     RECT  71.665 10.848 72.421 11.976 ;
     RECT  72.373 15.936 72.421 17.544 ;
     RECT  71.273 35.184 72.421 35.304 ;
     RECT  71.273 36.384 72.421 46.008 ;
     RECT  71.341 31.92 72.428 34.104 ;
     RECT  72.421 35.184 72.428 46.008 ;
     RECT  72.277 18.768 72.469 21.528 ;
     RECT  72.349 22.608 72.469 23.88 ;
     RECT  71.701 27.072 72.565 30.36 ;
     RECT  72.428 31.92 72.565 46.008 ;
     RECT  72.421 2.256 72.608 11.976 ;
     RECT  71.281 14.448 72.608 14.472 ;
     RECT  72.421 15.936 72.608 17.688 ;
     RECT  72.469 18.768 72.608 23.88 ;
     RECT  71.273 24.912 72.608 26.04 ;
     RECT  72.565 27.072 72.608 46.008 ;
     RECT  72.169 47.136 72.608 61.56 ;
     RECT  72.608 2.148 72.712 62.652 ;
     RECT  72.712 2.418 72.904 62.382 ;
     RECT  72.904 33.36 73.037 35.544 ;
     RECT  72.904 27.072 73.109 32.328 ;
     RECT  73.037 33.552 73.109 35.544 ;
     RECT  72.904 59.664 73.145 61.176 ;
     RECT  72.904 16.032 73.289 24.552 ;
     RECT  72.904 37.008 73.289 53.592 ;
     RECT  73.289 16.032 73.325 17.688 ;
     RECT  73.289 18.768 73.325 24.552 ;
     RECT  72.904 62.16 73.325 62.184 ;
     RECT  73.325 18.768 73.379 21.144 ;
     RECT  72.904 2.496 73.433 9.672 ;
     RECT  73.379 18.768 73.433 20.712 ;
     RECT  73.289 41.088 73.469 53.592 ;
     RECT  73.433 3.12 73.577 9.672 ;
     RECT  73.109 27.072 73.577 28.968 ;
     RECT  72.904 54.72 73.613 58.68 ;
     RECT  73.469 41.088 73.649 42.024 ;
     RECT  73.109 30.096 73.685 32.328 ;
     RECT  73.649 41.088 73.685 41.784 ;
     RECT  73.685 31.68 73.793 32.328 ;
     RECT  73.613 57.12 73.829 58.68 ;
     RECT  73.793 31.728 73.865 32.328 ;
     RECT  73.829 57.12 73.937 57.192 ;
     RECT  72.904 10.992 73.969 14.904 ;
     RECT  73.325 16.032 73.973 17.64 ;
     RECT  73.613 54.72 73.973 56.136 ;
     RECT  73.865 31.776 74.045 32.328 ;
     RECT  73.577 28.944 74.077 28.968 ;
     RECT  73.109 33.6 74.077 35.544 ;
     RECT  73.325 22.128 74.099 24.552 ;
     RECT  73.685 41.088 74.189 41.208 ;
     RECT  74.077 28.944 74.197 29.064 ;
     RECT  74.099 22.656 74.221 24.552 ;
     RECT  74.101 25.68 74.221 25.704 ;
     RECT  74.197 28.944 74.221 29.112 ;
     RECT  73.685 30.096 74.221 30.12 ;
     RECT  73.145 61.008 74.221 61.176 ;
     RECT  73.289 37.008 74.252 39.816 ;
     RECT  74.221 22.656 74.261 25.704 ;
     RECT  73.973 54.864 74.261 56.136 ;
     RECT  73.829 58.32 74.293 58.68 ;
     RECT  73.145 59.664 74.293 59.688 ;
     RECT  73.973 16.032 74.297 17.448 ;
     RECT  73.969 10.992 74.329 15 ;
     RECT  74.297 16.032 74.329 16.584 ;
     RECT  74.077 33.552 74.341 35.544 ;
     RECT  74.252 37.008 74.341 39.864 ;
     RECT  74.261 54.864 74.369 55.224 ;
     RECT  74.341 33.552 74.387 39.864 ;
     RECT  74.387 39.792 74.401 39.864 ;
     RECT  73.577 3.36 74.437 9.672 ;
     RECT  74.329 10.992 74.437 16.584 ;
     RECT  74.293 58.32 74.437 59.688 ;
     RECT  74.221 61.008 74.437 61.512 ;
     RECT  73.433 18.768 74.441 20.52 ;
     RECT  73.577 27.072 74.441 27.96 ;
     RECT  74.261 22.656 74.477 25.128 ;
     RECT  73.469 43.008 74.477 53.592 ;
     RECT  74.189 41.088 74.513 41.112 ;
     RECT  74.221 28.944 74.521 30.12 ;
     RECT  74.437 3.36 74.549 16.584 ;
     RECT  74.549 3.36 74.581 14.52 ;
     RECT  74.477 22.752 74.585 25.128 ;
     RECT  74.387 33.552 74.657 38.568 ;
     RECT  74.045 32.304 74.677 32.328 ;
     RECT  74.657 33.552 74.677 37.368 ;
     RECT  74.581 3.216 74.761 14.52 ;
     RECT  74.677 32.304 74.764 37.368 ;
     RECT  74.761 2.976 74.801 14.52 ;
     RECT  74.764 32.304 74.801 32.328 ;
     RECT  74.477 43.008 74.821 53.4 ;
     RECT  74.657 38.4 74.837 38.568 ;
     RECT  74.441 18.768 74.869 19.8 ;
     RECT  74.521 30.096 74.869 30.12 ;
     RECT  74.821 42.576 74.869 53.4 ;
     RECT  74.549 15.696 74.981 16.584 ;
     RECT  74.869 30.096 74.981 30.696 ;
     RECT  74.401 39.792 75.085 40.056 ;
     RECT  74.441 27.312 75.125 27.96 ;
     RECT  74.369 54.864 75.193 55.032 ;
     RECT  74.869 42.144 75.251 53.4 ;
     RECT  74.585 22.752 75.269 24.36 ;
     RECT  75.251 42.144 75.269 49.368 ;
     RECT  75.049 31.872 75.373 31.896 ;
     RECT  74.837 38.496 75.445 38.568 ;
     RECT  75.085 39.792 75.445 40.92 ;
     RECT  74.801 2.976 75.449 14.472 ;
     RECT  75.449 2.976 75.485 5.256 ;
     RECT  74.981 30.096 75.485 30.648 ;
     RECT  75.517 20.832 75.589 20.856 ;
     RECT  74.764 33.84 75.593 37.368 ;
     RECT  75.485 2.976 75.637 5.208 ;
     RECT  74.869 18.72 75.665 19.8 ;
     RECT  75.269 42.144 75.665 48.696 ;
     RECT  75.251 50.352 75.697 53.4 ;
     RECT  75.193 54.72 75.697 55.032 ;
     RECT  75.637 2.976 75.701 4.104 ;
     RECT  74.437 58.32 75.701 61.512 ;
     RECT  75.697 50.352 75.733 55.032 ;
     RECT  75.665 19.776 75.781 19.8 ;
     RECT  75.589 20.832 75.781 21.672 ;
     RECT  75.373 25.68 75.788 25.704 ;
     RECT  75.788 25.68 75.805 26.136 ;
     RECT  75.593 33.84 75.805 36.936 ;
     RECT  75.701 61.152 75.805 61.512 ;
     RECT  75.805 61.152 75.809 62.04 ;
     RECT  75.781 19.776 75.841 21.672 ;
     RECT  75.485 30.288 75.845 30.648 ;
     RECT  75.373 31.776 75.845 31.896 ;
     RECT  75.805 25.68 75.875 26.232 ;
     RECT  75.701 2.976 75.877 3.816 ;
     RECT  74.149 0.528 75.881 0.552 ;
     RECT  75.845 30.288 75.881 30.312 ;
     RECT  75.809 61.488 75.881 62.04 ;
     RECT  75.125 27.312 75.909 27.336 ;
     RECT  75.733 50.352 75.917 55.848 ;
     RECT  73.937 57.12 75.985 57.144 ;
     RECT  75.701 58.32 75.985 60.12 ;
     RECT  75.917 53.376 75.989 55.848 ;
     RECT  75.269 23.28 76.057 24.36 ;
     RECT  75.877 2.832 76.061 3.816 ;
     RECT  75.665 18.72 76.061 18.744 ;
     RECT  75.665 42.144 76.061 42.168 ;
     RECT  75.989 53.376 76.097 54.168 ;
     RECT  75.637 5.136 76.205 5.208 ;
     RECT  74.521 28.944 76.205 29.064 ;
     RECT  75.445 38.496 76.205 40.92 ;
     RECT  76.205 38.496 76.241 40.584 ;
     RECT  75.841 19.776 76.309 22.008 ;
     RECT  76.057 23.28 76.309 25.224 ;
     RECT  75.665 43.344 76.313 48.696 ;
     RECT  76.061 2.832 76.453 3.72 ;
     RECT  74.981 15.696 76.489 15.72 ;
     RECT  76.453 2.256 76.547 3.72 ;
     RECT  76.205 28.944 76.549 28.968 ;
     RECT  76.508 30 76.595 30.024 ;
     RECT  75.805 33.552 76.601 36.936 ;
     RECT  76.489 15.6 76.633 15.72 ;
     RECT  76.597 17.232 76.633 17.256 ;
     RECT  76.601 35.472 76.669 36.936 ;
     RECT  75.989 55.824 76.669 55.848 ;
     RECT  76.633 15.6 76.741 17.256 ;
     RECT  76.669 35.472 76.745 37.176 ;
     RECT  76.741 15.6 76.813 17.736 ;
     RECT  75.449 6.432 76.837 14.472 ;
     RECT  76.813 15.456 76.837 17.736 ;
     RECT  76.837 6.432 76.849 17.736 ;
     RECT  75.985 57.12 76.885 60.12 ;
     RECT  75.881 62.016 76.885 62.04 ;
     RECT  76.241 38.496 77.209 39.336 ;
     RECT  76.241 40.512 77.209 40.584 ;
     RECT  76.885 57.12 77.221 62.04 ;
     RECT  76.549 28.224 77.245 28.968 ;
     RECT  77.209 38.496 77.245 40.584 ;
     RECT  75.917 50.352 77.281 52.344 ;
     RECT  76.097 53.568 77.281 54.168 ;
     RECT  76.309 19.776 77.317 25.224 ;
     RECT  76.313 43.344 77.389 48.504 ;
     RECT  77.281 50.352 77.413 54.168 ;
     RECT  76.669 55.824 77.425 55.944 ;
     RECT  75.875 26.208 77.461 26.232 ;
     RECT  76.849 6.288 77.497 17.736 ;
     RECT  77.317 19.056 77.497 25.224 ;
     RECT  76.601 33.552 77.533 34.152 ;
     RECT  77.389 42.768 77.533 48.504 ;
     RECT  77.413 49.536 77.533 54.168 ;
     RECT  76.745 35.52 77.569 37.176 ;
     RECT  77.245 38.16 77.569 40.584 ;
     RECT  77.533 42.768 77.66 54.168 ;
     RECT  77.425 55.824 77.66 56.04 ;
     RECT  77.137 30.816 77.785 30.84 ;
     RECT  75.845 31.872 77.785 31.896 ;
     RECT  77.785 30.144 77.821 31.896 ;
     RECT  77.533 33.36 77.821 34.152 ;
     RECT  77.569 35.52 77.821 40.584 ;
     RECT  76.205 5.136 77.893 5.16 ;
     RECT  77.497 6.288 77.893 25.224 ;
     RECT  76.547 2.784 78.008 3.72 ;
     RECT  77.893 5.136 78.008 25.224 ;
     RECT  77.461 26.208 78.008 26.808 ;
     RECT  77.245 28.224 78.008 29.016 ;
     RECT  77.821 30.144 78.008 34.152 ;
     RECT  77.821 35.472 78.008 40.584 ;
     RECT  77.66 42.768 78.008 56.04 ;
     RECT  77.221 57.024 78.008 62.04 ;
     RECT  77.845 0.528 78.041 0.552 ;
     RECT  78.008 2.148 78.112 62.652 ;
     RECT  78.112 2.148 78.217 62.382 ;
     RECT  78.217 1.728 78.304 62.382 ;
     RECT  78.304 27.984 78.365 30.936 ;
     RECT  78.304 5.664 78.419 21.144 ;
     RECT  78.304 32.16 78.419 41.592 ;
     RECT  78.419 5.664 78.437 19.944 ;
     RECT  78.365 29.52 78.467 30.936 ;
     RECT  78.304 26.784 78.473 26.808 ;
     RECT  78.304 47.28 78.509 59.112 ;
     RECT  78.467 29.52 78.515 30.168 ;
     RECT  78.419 21.072 78.545 21.144 ;
     RECT  78.304 1.728 78.707 4.44 ;
     RECT  78.509 47.28 78.707 58.728 ;
     RECT  78.437 14.352 78.725 19.944 ;
     RECT  78.515 30.144 78.833 30.168 ;
     RECT  78.707 47.28 78.869 55.272 ;
     RECT  78.725 14.352 78.977 19.08 ;
     RECT  78.869 47.28 79.049 52.632 ;
     RECT  78.419 34.608 79.085 41.592 ;
     RECT  78.437 5.664 79.121 13.272 ;
     RECT  78.707 56.352 79.139 58.728 ;
     RECT  78.757 0.048 79.157 0.072 ;
     RECT  78.707 2.688 79.229 4.44 ;
     RECT  79.049 49.008 79.265 52.296 ;
     RECT  78.419 32.16 79.297 33.576 ;
     RECT  79.139 56.832 79.301 58.728 ;
     RECT  78.977 14.352 79.337 16.2 ;
     RECT  79.229 3.024 79.373 4.44 ;
     RECT  79.297 31.632 79.441 33.576 ;
     RECT  79.085 34.608 79.441 40.488 ;
     RECT  79.301 58.128 79.477 58.728 ;
     RECT  78.304 60.24 79.477 61.032 ;
     RECT  79.441 31.632 79.481 40.488 ;
     RECT  79.301 56.832 79.481 56.856 ;
     RECT  79.121 9.792 79.513 13.272 ;
     RECT  79.337 14.352 79.513 14.904 ;
     RECT  78.304 24.624 79.513 25.224 ;
     RECT  78.977 17.472 79.517 19.08 ;
     RECT  78.304 42.624 79.517 46.296 ;
     RECT  78.545 21.072 79.628 21.096 ;
     RECT  79.477 58.128 79.667 61.032 ;
     RECT  79.373 3.312 79.669 4.44 ;
     RECT  79.121 5.664 79.669 8.424 ;
     RECT  79.549 26.784 79.693 26.808 ;
     RECT  78.365 27.984 79.693 28.296 ;
     RECT  79.513 9.792 79.697 14.904 ;
     RECT  79.517 17.472 79.715 18.84 ;
     RECT  79.628 20.208 79.715 21.096 ;
     RECT  79.693 26.784 79.715 28.296 ;
     RECT  79.481 31.632 79.715 38.52 ;
     RECT  79.481 39.792 79.769 40.488 ;
     RECT  79.693 30 79.801 30.024 ;
     RECT  79.715 27.312 79.811 28.296 ;
     RECT  79.715 31.632 79.841 34.92 ;
     RECT  79.085 41.568 79.873 41.592 ;
     RECT  79.667 60.384 79.877 60.552 ;
     RECT  79.841 31.632 79.913 34.632 ;
     RECT  79.517 43.104 79.913 46.296 ;
     RECT  79.811 27.36 79.945 28.296 ;
     RECT  79.049 47.28 80.017 47.688 ;
     RECT  79.513 24.096 80.053 25.224 ;
     RECT  80.053 23.904 80.099 25.224 ;
     RECT  80.099 23.904 80.14 23.928 ;
     RECT  79.669 3.312 80.161 8.424 ;
     RECT  79.697 9.792 80.161 14.856 ;
     RECT  78.869 53.616 80.161 55.272 ;
     RECT  79.715 17.472 80.165 18.264 ;
     RECT  80.099 25.104 80.345 25.224 ;
     RECT  79.913 33.072 80.345 34.632 ;
     RECT  79.945 27.36 80.377 29.016 ;
     RECT  79.801 30 80.377 30.456 ;
     RECT  79.769 40.464 80.377 40.488 ;
     RECT  79.873 41.568 80.377 41.928 ;
     RECT  79.265 49.008 80.387 51.672 ;
     RECT  80.165 17.616 80.417 18.264 ;
     RECT  79.913 31.632 80.417 31.944 ;
     RECT  80.377 40.464 80.417 41.928 ;
     RECT  80.387 50.736 80.437 51.672 ;
     RECT  80.161 52.848 80.449 55.272 ;
     RECT  80.389 23.712 80.476 23.736 ;
     RECT  79.765 21.12 80.485 21.576 ;
     RECT  80.377 27.36 80.521 30.456 ;
     RECT  80.017 46.704 80.521 47.688 ;
     RECT  80.345 34.32 80.525 34.632 ;
     RECT  80.521 27.36 80.669 30.936 ;
     RECT  80.485 21.12 80.701 22.44 ;
     RECT  79.667 58.128 80.701 59.304 ;
     RECT  80.669 27.408 80.705 30.936 ;
     RECT  79.337 15.984 80.821 16.2 ;
     RECT  80.821 16.176 80.837 16.2 ;
     RECT  80.821 19.344 80.869 19.368 ;
     RECT  79.913 43.104 80.881 45.72 ;
     RECT  80.387 49.008 80.957 49.656 ;
     RECT  79.877 60.384 80.957 60.408 ;
     RECT  80.449 52.848 80.963 55.32 ;
     RECT  80.837 16.176 80.993 16.584 ;
     RECT  80.963 52.848 80.993 54.456 ;
     RECT  80.701 57.216 80.993 59.304 ;
     RECT  80.161 3.312 81.029 14.856 ;
     RECT  80.705 27.408 81.029 29.784 ;
     RECT  80.881 42.96 81.061 45.72 ;
     RECT  80.521 46.704 81.061 47.832 ;
     RECT  80.705 30.912 81.065 30.936 ;
     RECT  80.345 33.072 81.101 33.096 ;
     RECT  80.417 17.616 81.133 17.64 ;
     RECT  81.061 24.912 81.133 24.936 ;
     RECT  80.993 52.848 81.137 53.928 ;
     RECT  80.701 20.928 81.169 22.44 ;
     RECT  80.701 2.304 81.173 2.328 ;
     RECT  81.029 27.408 81.245 29.736 ;
     RECT  81.169 20.64 81.313 22.44 ;
     RECT  80.417 40.992 81.349 41.928 ;
     RECT  81.061 42.96 81.349 47.832 ;
     RECT  80.993 57.216 81.389 58.488 ;
     RECT  81.133 16.944 81.421 17.64 ;
     RECT  80.525 34.32 81.445 34.344 ;
     RECT  79.715 36.288 81.445 38.52 ;
     RECT  81.421 39.888 81.445 39.912 ;
     RECT  80.437 50.736 81.457 51.816 ;
     RECT  81.137 52.848 81.457 53.832 ;
     RECT  81.029 3.312 81.493 14.088 ;
     RECT  81.445 36.288 81.505 39.912 ;
     RECT  81.445 33.504 81.532 34.344 ;
     RECT  81.245 27.888 81.533 29.736 ;
     RECT  81.493 3.168 81.569 14.088 ;
     RECT  81.349 40.992 81.605 47.832 ;
     RECT  81.133 24.528 81.709 24.936 ;
     RECT  81.605 41.616 81.781 47.832 ;
     RECT  80.957 49.008 81.781 49.464 ;
     RECT  81.569 3.168 81.821 13.464 ;
     RECT  81.389 57.216 81.821 58.152 ;
     RECT  81.457 50.736 81.857 53.832 ;
     RECT  81.313 20.448 81.893 22.44 ;
     RECT  81.533 27.888 81.916 29.448 ;
     RECT  81.709 24.432 81.961 24.936 ;
     RECT  81.821 3.6 81.971 13.464 ;
     RECT  80.869 18.72 81.997 19.368 ;
     RECT  81.781 41.616 82.037 49.464 ;
     RECT  81.857 51.648 82.067 53.832 ;
     RECT  81.821 57.216 82.069 57.72 ;
     RECT  82.067 51.648 82.073 52.824 ;
     RECT  81.893 21.696 82.109 22.44 ;
     RECT  82.069 56.448 82.109 57.72 ;
     RECT  81.961 24.144 82.141 24.936 ;
     RECT  81.971 3.6 82.145 11.4 ;
     RECT  81.421 16.944 82.177 17.688 ;
     RECT  81.916 27.984 82.181 29.448 ;
     RECT  82.181 28.272 82.204 29.448 ;
     RECT  82.109 56.448 82.213 56.472 ;
     RECT  82.037 42.96 82.225 49.464 ;
     RECT  82.109 22.08 82.253 22.44 ;
     RECT  82.204 28.272 82.253 29.352 ;
     RECT  82.177 16.8 82.285 17.688 ;
     RECT  81.971 12.528 82.289 13.464 ;
     RECT  82.213 14.832 82.297 14.856 ;
     RECT  82.225 46.848 82.307 49.464 ;
     RECT  82.307 46.848 82.348 47.832 ;
     RECT  82.285 16.032 82.393 17.688 ;
     RECT  82.109 57.552 82.433 57.72 ;
     RECT  81.997 18.72 82.645 19.416 ;
     RECT  81.893 20.448 82.645 20.664 ;
     RECT  82.357 34.944 82.645 34.968 ;
     RECT  81.505 36.288 82.645 39.336 ;
     RECT  82.067 53.808 82.645 53.832 ;
     RECT  82.213 55.584 82.645 56.472 ;
     RECT  82.645 34.8 82.681 34.968 ;
     RECT  82.645 36.288 83.105 40.056 ;
     RECT  82.145 3.6 83.408 11.352 ;
     RECT  82.289 12.528 83.408 12.552 ;
     RECT  82.393 15.216 83.408 17.688 ;
     RECT  82.645 18.72 83.408 20.664 ;
     RECT  82.253 22.416 83.408 22.44 ;
     RECT  82.141 23.616 83.408 24.936 ;
     RECT  82.253 28.272 83.408 29.016 ;
     RECT  82.645 30.576 83.408 30.6 ;
     RECT  80.417 31.92 83.408 31.944 ;
     RECT  81.532 33.504 83.408 33.528 ;
     RECT  82.681 34.8 83.408 35.16 ;
     RECT  83.105 36.288 83.408 40.488 ;
     RECT  82.037 41.616 83.408 41.64 ;
     RECT  82.225 42.96 83.408 45.816 ;
     RECT  82.348 47.808 83.408 47.832 ;
     RECT  82.307 49.008 83.408 49.464 ;
     RECT  82.073 52.368 83.408 52.824 ;
     RECT  82.645 53.808 83.408 54.072 ;
     RECT  82.645 55.248 83.408 56.472 ;
     RECT  82.433 57.696 83.408 57.72 ;
     RECT  83.408 2.148 83.512 62.652 ;
     RECT  83.512 2.418 83.704 62.382 ;
     RECT  83.704 52.704 83.765 52.728 ;
     RECT  83.704 15.408 84.053 15.864 ;
     RECT  83.704 11.856 84.131 11.88 ;
     RECT  84.053 15.408 84.131 15.432 ;
    LAYER M5 ;
     RECT  5.76 0.037 5.784 0.085 ;
     RECT  48.336 0.016 51.336 0.085 ;
     RECT  52.464 0.037 52.488 0.085 ;
     RECT  58.464 0.037 58.488 0.085 ;
     RECT  48.336 0.085 52.488 0.131 ;
     RECT  5.76 0.085 6.024 0.373 ;
     RECT  53.616 0.037 53.64 0.469 ;
     RECT  3.216 0.037 3.624 0.517 ;
     RECT  5.76 0.373 6.264 0.517 ;
     RECT  53.616 0.469 53.88 0.517 ;
     RECT  57.984 0.085 58.488 0.565 ;
     RECT  67.536 0.016 70.536 0.611 ;
     RECT  67.632 0.611 70.536 0.659 ;
     RECT  57.36 0.565 58.488 1.717 ;
     RECT  77.856 0.517 77.88 1.717 ;
     RECT  48.432 0.131 52.488 1.763 ;
     RECT  67.728 0.659 70.536 1.763 ;
     RECT  9.936 0.016 19.08 1.811 ;
     RECT  67.728 1.763 70.44 1.811 ;
     RECT  3.072 0.517 3.624 2.137 ;
     RECT  55.488 0.037 55.512 2.137 ;
     RECT  56.784 1.717 58.488 2.137 ;
     RECT  7.8 2.137 7.92 2.151 ;
     RECT  24 2.137 24.12 2.151 ;
     RECT  29.4 2.137 29.52 2.151 ;
     RECT  34.8 2.137 34.92 2.151 ;
     RECT  40.2 2.137 40.32 2.151 ;
     RECT  45.6 2.137 45.72 2.151 ;
     RECT  61.8 2.137 61.92 2.151 ;
     RECT  72.6 2.137 72.72 2.151 ;
     RECT  83.4 2.137 83.52 2.151 ;
     RECT  9.936 1.811 18.912 2.197 ;
     RECT  53.616 0.517 53.976 2.197 ;
     RECT  45.6 2.151 45.912 2.245 ;
     RECT  48.72 1.763 52.488 2.245 ;
     RECT  53.616 2.197 54.408 2.245 ;
     RECT  72.6 2.151 72.912 2.245 ;
     RECT  75.6 0.517 75.624 2.245 ;
     RECT  68.688 1.811 70.44 2.291 ;
     RECT  9.648 2.197 18.912 2.533 ;
     RECT  71.616 2.245 72.912 2.677 ;
     RECT  5.328 0.517 6.264 2.725 ;
     RECT  2.4 2.137 3.624 2.773 ;
     RECT  7.8 2.151 8.112 2.773 ;
     RECT  9.504 2.533 18.912 2.773 ;
     RECT  48.72 2.245 54.408 2.773 ;
     RECT  55.488 2.137 58.488 2.773 ;
     RECT  61.8 2.151 62.112 2.773 ;
     RECT  2.304 2.773 3.624 2.821 ;
     RECT  4.608 2.725 6.36 2.821 ;
     RECT  7.8 2.773 18.912 2.821 ;
     RECT  45.6 2.245 46.152 2.821 ;
     RECT  67.2 2.137 67.512 2.821 ;
     RECT  77.856 1.717 78.696 2.821 ;
     RECT  71.616 2.677 73.032 2.867 ;
     RECT  48.72 2.773 58.488 2.917 ;
     RECT  59.616 2.245 59.64 2.917 ;
     RECT  74.16 0.517 74.184 3.013 ;
     RECT  75.6 2.245 76.536 3.013 ;
     RECT  44.88 2.821 46.152 3.059 ;
     RECT  7.392 2.821 18.912 3.157 ;
     RECT  61.68 2.773 62.112 3.205 ;
     RECT  2.304 2.821 6.36 3.301 ;
     RECT  7.392 3.157 19.56 3.301 ;
     RECT  48.72 2.917 59.64 3.301 ;
     RECT  74.16 3.013 76.536 3.301 ;
     RECT  77.712 2.821 78.696 3.301 ;
     RECT  48.048 3.301 59.64 3.397 ;
     RECT  66.096 2.821 66.12 3.683 ;
     RECT  24 2.151 24.312 3.733 ;
     RECT  47.664 3.397 59.64 3.925 ;
     RECT  80.352 3.733 80.376 3.925 ;
     RECT  24 3.733 24.984 3.971 ;
     RECT  30.72 2.821 30.744 4.115 ;
     RECT  67.2 2.821 67.608 4.261 ;
     RECT  44.88 3.059 45.912 4.403 ;
     RECT  47.664 3.925 59.736 4.405 ;
     RECT  66 4.357 66.024 4.501 ;
     RECT  67.2 4.261 67.752 4.501 ;
     RECT  81.504 3.157 81.528 4.691 ;
     RECT  80.208 3.925 80.376 4.885 ;
     RECT  45.6 4.403 45.912 4.981 ;
     RECT  47.328 4.405 59.736 4.981 ;
     RECT  34.8 2.151 35.112 5.029 ;
     RECT  37.776 3.349 37.8 5.029 ;
     RECT  67.104 4.501 67.752 5.171 ;
     RECT  70.416 2.291 70.44 5.171 ;
     RECT  37.392 5.029 37.8 5.173 ;
     RECT  34.8 5.029 35.88 5.219 ;
     RECT  61.68 3.205 62.376 5.269 ;
     RECT  72.6 2.867 73.032 5.365 ;
     RECT  82.08 5.077 82.104 5.365 ;
     RECT  83.4 2.151 83.712 5.365 ;
     RECT  61.68 5.269 62.76 5.461 ;
     RECT  45.6 4.981 59.736 5.509 ;
     RECT  61.632 5.461 62.76 5.603 ;
     RECT  40.2 2.151 40.512 5.605 ;
     RECT  45.6 5.509 60.456 5.605 ;
     RECT  61.632 5.603 62.376 5.605 ;
     RECT  65.808 4.501 66.024 5.605 ;
     RECT  65.616 5.605 66.024 5.653 ;
     RECT  74.16 3.301 78.696 5.653 ;
     RECT  79.68 4.885 80.376 5.653 ;
     RECT  82.08 5.365 83.712 5.653 ;
     RECT  2.304 3.301 19.56 5.747 ;
     RECT  37.392 5.173 38.28 5.747 ;
     RECT  74.16 5.653 80.376 5.747 ;
     RECT  29.4 2.151 29.712 5.893 ;
     RECT  69.312 5.701 69.336 6.083 ;
     RECT  65.616 5.653 66.12 6.179 ;
     RECT  67.2 5.171 67.752 6.229 ;
     RECT  71.232 5.365 73.032 6.229 ;
     RECT  74.16 5.747 79.704 6.229 ;
     RECT  38.256 5.747 38.28 6.563 ;
     RECT  2.4 5.747 19.56 6.709 ;
     RECT  21.504 6.181 21.528 6.805 ;
     RECT  24 3.971 24.312 6.805 ;
     RECT  33.024 5.125 33.048 6.805 ;
     RECT  67.2 6.229 67.8 6.805 ;
     RECT  68.976 6.229 69 6.805 ;
     RECT  37.056 6.517 37.08 6.851 ;
     RECT  2.4 6.709 20.52 6.853 ;
     RECT  21.504 6.805 21.864 6.853 ;
     RECT  2.4 6.853 21.864 6.901 ;
     RECT  2.304 6.901 21.864 6.995 ;
     RECT  71.232 6.229 79.704 6.995 ;
     RECT  67.2 6.805 69 7.139 ;
     RECT  71.232 6.995 75.912 7.333 ;
     RECT  28.464 5.893 29.712 7.381 ;
     RECT  70.752 7.333 75.912 7.427 ;
     RECT  43.728 5.077 43.752 7.429 ;
     RECT  43.728 7.429 44.52 7.571 ;
     RECT  81.36 5.653 83.712 7.763 ;
     RECT  65.904 6.179 66.12 7.765 ;
     RECT  67.2 7.139 68.856 7.765 ;
     RECT  21.84 6.995 21.864 8.003 ;
     RECT  28.464 7.381 29.928 8.003 ;
     RECT  70.752 7.427 72.912 8.003 ;
     RECT  32.16 6.805 33.048 8.195 ;
     RECT  45.6 5.605 62.376 8.293 ;
     RECT  44.496 7.571 44.52 8.339 ;
     RECT  65.904 7.765 68.856 8.341 ;
     RECT  65.904 8.341 69.384 8.389 ;
     RECT  72.432 8.003 72.912 8.437 ;
     RECT  73.92 7.427 75.912 8.437 ;
     RECT  77.376 6.995 79.704 8.437 ;
     RECT  43.296 7.861 43.32 8.579 ;
     RECT  70.752 8.003 71.304 8.723 ;
     RECT  24 6.805 24.408 8.773 ;
     RECT  28.464 8.003 29.712 8.819 ;
     RECT  45.6 8.293 62.952 8.867 ;
     RECT  2.304 6.995 20.52 8.869 ;
     RECT  41.568 7.189 41.592 9.011 ;
     RECT  65.904 8.389 69.72 9.059 ;
     RECT  24 8.773 25.032 9.109 ;
     RECT  39.84 5.605 40.512 9.155 ;
     RECT  77.376 8.437 80.376 9.155 ;
     RECT  65.904 9.059 69.384 9.203 ;
     RECT  67.104 9.203 69.384 9.347 ;
     RECT  72.432 8.437 75.912 9.395 ;
     RECT  75.888 9.395 75.912 9.397 ;
     RECT  24 9.109 25.128 9.541 ;
     RECT  21.552 8.437 21.576 9.635 ;
     RECT  71.232 8.723 71.304 9.683 ;
     RECT  45.6 8.867 62.376 9.731 ;
     RECT  34.8 5.219 35.256 9.781 ;
     RECT  23.376 9.541 25.128 10.213 ;
     RECT  32.16 8.195 32.184 10.213 ;
     RECT  69.36 9.347 69.384 10.213 ;
     RECT  75.888 9.397 76.296 10.213 ;
     RECT  77.376 9.155 80.328 10.213 ;
     RECT  23.04 10.213 25.128 10.259 ;
     RECT  2.256 8.869 20.52 10.307 ;
     RECT  83.04 7.763 83.712 10.307 ;
     RECT  45.6 9.731 60.504 10.355 ;
     RECT  67.104 9.347 68.376 10.355 ;
     RECT  31.248 10.213 32.184 10.453 ;
     RECT  72.432 9.395 74.808 10.499 ;
     RECT  45.6 10.355 45.912 10.597 ;
     RECT  81.36 7.763 82.056 10.693 ;
     RECT  45.36 10.597 45.912 10.741 ;
     RECT  42.144 9.637 42.168 10.883 ;
     RECT  69.36 10.213 69.72 10.883 ;
     RECT  34.8 9.781 35.304 10.885 ;
     RECT  75.888 10.213 80.328 10.885 ;
     RECT  81.36 10.693 82.248 10.885 ;
     RECT  69.696 10.883 69.72 10.981 ;
     RECT  71.28 9.683 71.304 10.981 ;
     RECT  64.32 9.157 64.344 11.027 ;
     RECT  69.696 10.981 71.304 11.363 ;
     RECT  34.272 10.885 35.304 11.365 ;
     RECT  72.48 10.499 74.808 11.413 ;
     RECT  75.888 10.885 82.248 11.413 ;
     RECT  47.184 10.355 60.504 11.459 ;
     RECT  72.48 11.413 82.248 11.459 ;
     RECT  67.2 10.355 68.376 11.507 ;
     RECT  72.48 11.459 78.936 11.507 ;
     RECT  70.08 11.363 71.304 11.845 ;
     RECT  83.4 10.307 83.712 11.845 ;
     RECT  61.632 9.731 62.376 11.893 ;
     RECT  28.512 8.819 29.712 11.939 ;
     RECT  70.08 11.845 71.4 11.939 ;
     RECT  61.584 11.893 62.376 12.181 ;
     RECT  61.44 12.181 62.376 12.323 ;
     RECT  31.248 10.453 32.76 12.469 ;
     RECT  34.272 11.365 36.024 12.469 ;
     RECT  37.632 9.637 37.656 12.563 ;
     RECT  63.84 11.797 63.864 12.563 ;
     RECT  31.248 12.469 36.024 12.659 ;
     RECT  74.592 11.507 78.936 12.659 ;
     RECT  34.8 12.659 36.024 12.707 ;
     RECT  65.904 9.203 65.928 12.997 ;
     RECT  70.08 11.939 70.248 13.091 ;
     RECT  71.232 11.939 71.4 13.091 ;
     RECT  26.976 11.413 27 13.139 ;
     RECT  47.184 11.459 60.072 13.139 ;
     RECT  70.08 13.091 70.104 13.187 ;
     RECT  68.688 13.093 68.712 13.235 ;
     RECT  31.248 12.659 33.384 13.283 ;
     RECT  75.6 12.659 78.936 13.283 ;
     RECT  34.8 12.707 35.256 13.331 ;
     RECT  65.904 12.997 66.168 13.667 ;
     RECT  23.04 10.259 24.6 13.669 ;
     RECT  71.232 13.091 71.256 13.715 ;
     RECT  44.784 10.741 45.912 13.811 ;
     RECT  33.36 13.283 33.384 13.859 ;
     RECT  23.04 13.669 25.128 14.003 ;
     RECT  61.584 12.323 62.376 14.003 ;
     RECT  2.256 10.307 15.336 14.005 ;
     RECT  16.32 10.307 20.52 14.005 ;
     RECT  2.256 14.005 20.52 14.051 ;
     RECT  47.184 13.139 59.736 14.099 ;
     RECT  75.6 13.283 78.312 14.099 ;
     RECT  80.016 11.459 82.248 14.101 ;
     RECT  2.256 14.051 14.088 14.339 ;
     RECT  21.936 13.957 21.96 14.387 ;
     RECT  39.936 9.155 40.512 14.485 ;
     RECT  69.792 13.957 69.816 14.485 ;
     RECT  2.256 14.339 14.04 14.531 ;
     RECT  69.792 14.485 70.104 14.531 ;
     RECT  75.84 14.099 78.312 14.533 ;
     RECT  15.168 14.051 20.52 14.675 ;
     RECT  15.216 14.675 20.52 14.819 ;
     RECT  39.312 14.485 40.512 14.867 ;
     RECT  43.92 14.677 43.944 14.867 ;
     RECT  47.904 14.099 59.736 14.867 ;
     RECT  63.888 14.341 63.912 14.867 ;
     RECT  79.776 14.101 82.248 14.867 ;
     RECT  72.48 11.507 73.512 14.915 ;
     RECT  24 14.003 25.128 15.155 ;
     RECT  39.936 14.867 40.512 15.157 ;
     RECT  39.936 15.157 41.112 15.443 ;
     RECT  65.904 13.667 65.928 15.443 ;
     RECT  83.4 11.845 84.12 15.443 ;
     RECT  31.248 13.283 31.272 15.445 ;
     RECT  36.288 13.861 36.312 15.731 ;
     RECT  75.84 14.533 78.792 15.731 ;
     RECT  67.2 11.507 67.608 15.779 ;
     RECT  83.4 15.443 83.712 15.829 ;
     RECT  2.256 14.531 8.904 16.019 ;
     RECT  15.216 14.819 20.424 16.019 ;
     RECT  76.752 15.731 78.792 16.019 ;
     RECT  79.776 14.867 79.8 16.019 ;
     RECT  80.784 14.867 81.768 16.019 ;
     RECT  15.216 16.019 17.208 16.115 ;
     RECT  72.48 14.915 73.368 16.501 ;
     RECT  6.48 16.019 8.904 16.595 ;
     RECT  10.032 14.531 14.04 16.595 ;
     RECT  15.216 16.115 15.336 16.595 ;
     RECT  16.32 16.115 17.208 16.595 ;
     RECT  24 15.155 24.6 16.595 ;
     RECT  37.728 15.301 37.752 16.595 ;
     RECT  47.952 14.867 59.736 16.595 ;
     RECT  80.88 16.019 81.768 16.595 ;
     RECT  16.32 16.595 16.632 16.643 ;
     RECT  70.08 14.531 70.104 16.739 ;
     RECT  18.24 16.019 18.912 16.835 ;
     RECT  72.432 16.501 73.368 17.029 ;
     RECT  15.216 16.595 15.24 17.075 ;
     RECT  31.248 15.445 32.232 17.075 ;
     RECT  50.304 16.595 59.736 17.123 ;
     RECT  81.744 16.595 81.768 17.123 ;
     RECT  12.096 16.595 14.04 17.171 ;
     RECT  43.776 17.221 43.8 17.363 ;
     RECT  29.4 11.939 29.712 17.413 ;
     RECT  18.288 16.835 18.912 17.461 ;
     RECT  22.896 17.413 22.92 17.555 ;
     RECT  72.384 17.029 73.368 17.555 ;
     RECT  76.8 16.019 78.312 17.603 ;
     RECT  10.224 16.595 10.92 17.605 ;
     RECT  45.36 13.811 45.912 17.605 ;
     RECT  47.952 16.595 49.032 17.605 ;
     RECT  16.32 16.643 16.344 17.699 ;
     RECT  47.952 17.605 49.08 17.699 ;
     RECT  76.8 17.603 76.92 17.747 ;
     RECT  58.512 17.123 59.448 17.891 ;
     RECT  6.72 16.595 6.744 17.893 ;
     RECT  7.8 16.595 8.904 17.893 ;
     RECT  13.104 17.171 14.04 18.035 ;
     RECT  40.2 15.443 41.112 18.181 ;
     RECT  67.2 15.779 67.512 18.181 ;
     RECT  79.68 16.165 79.704 18.181 ;
     RECT  18.288 17.461 19.032 18.227 ;
     RECT  50.304 17.123 57.384 18.275 ;
     RECT  6.72 17.893 8.904 18.563 ;
     RECT  2.256 16.019 5.496 18.757 ;
     RECT  50.304 18.275 56.856 18.851 ;
     RECT  79.68 18.181 79.8 18.851 ;
     RECT  80.88 17.605 80.904 18.851 ;
     RECT  7.8 18.563 8.904 18.899 ;
     RECT  45.36 17.605 46.728 18.947 ;
     RECT  67.2 18.181 67.848 19.091 ;
     RECT  26.256 18.853 26.616 19.187 ;
     RECT  10.08 17.605 10.92 19.235 ;
     RECT  16.896 18.805 16.92 19.235 ;
     RECT  58.512 17.891 58.632 19.333 ;
     RECT  78 17.603 78.312 19.333 ;
     RECT  53.28 18.851 56.856 19.379 ;
     RECT  2.256 18.757 5.688 19.427 ;
     RECT  48.576 17.699 49.08 19.427 ;
     RECT  55.056 19.379 56.856 19.427 ;
     RECT  49.056 19.427 49.08 19.475 ;
     RECT  56.4 19.427 56.856 19.571 ;
     RECT  64.368 18.565 64.392 19.667 ;
     RECT  26.256 19.187 26.28 19.715 ;
     RECT  72.432 17.555 73.368 19.765 ;
     RECT  74.592 12.659 74.616 19.765 ;
     RECT  13.2 18.035 14.04 19.861 ;
     RECT  45.36 18.947 45.912 19.909 ;
     RECT  61.8 14.003 62.376 19.909 ;
     RECT  72.432 19.765 74.616 19.909 ;
     RECT  56.4 19.571 56.808 19.955 ;
     RECT  29.4 17.413 30.024 19.957 ;
     RECT  31.248 17.075 31.272 19.957 ;
     RECT  29.4 19.957 31.272 20.003 ;
     RECT  55.056 19.427 55.224 20.003 ;
     RECT  76.8 17.747 76.824 20.003 ;
     RECT  55.056 20.003 55.176 20.051 ;
     RECT  79.776 18.851 79.8 20.197 ;
     RECT  13.104 19.861 14.04 20.293 ;
     RECT  67.2 19.091 67.512 20.293 ;
     RECT  2.256 19.427 5.496 20.579 ;
     RECT  58.512 19.333 59.352 20.579 ;
     RECT  78 19.333 78.408 20.579 ;
     RECT  21.648 19.909 21.672 20.675 ;
     RECT  72.336 19.909 74.616 20.723 ;
     RECT  53.28 19.379 53.976 20.725 ;
     RECT  75.84 20.293 75.864 20.725 ;
     RECT  29.4 20.003 31.032 20.821 ;
     RECT  75.792 20.725 75.864 20.867 ;
     RECT  53.28 20.725 54.12 20.963 ;
     RECT  55.152 20.051 55.176 21.013 ;
     RECT  56.4 19.955 56.712 21.013 ;
     RECT  80.832 19.333 80.856 21.013 ;
     RECT  50.304 18.851 52.008 21.155 ;
     RECT  13.104 20.293 14.184 21.251 ;
     RECT  61.8 19.909 62.616 21.397 ;
     RECT  67.2 20.293 67.608 21.445 ;
     RECT  56.4 21.013 56.808 21.493 ;
     RECT  78 20.579 78.312 21.493 ;
     RECT  80.832 21.013 80.952 21.589 ;
     RECT  66.48 21.445 67.608 21.635 ;
     RECT  32.448 20.149 32.472 21.637 ;
     RECT  12.096 17.171 12.12 21.683 ;
     RECT  58.512 20.579 58.536 21.683 ;
     RECT  32.448 21.637 33.192 21.731 ;
     RECT  61.104 21.397 62.616 21.779 ;
     RECT  80.832 21.589 81.192 21.923 ;
     RECT  53.28 20.963 53.976 22.165 ;
     RECT  55.104 21.013 55.176 22.165 ;
     RECT  53.28 22.165 55.176 22.259 ;
     RECT  80.832 21.923 80.856 22.451 ;
     RECT  13.2 21.251 14.184 22.453 ;
     RECT  56.208 21.493 56.808 22.499 ;
     RECT  77.04 21.493 78.312 22.499 ;
     RECT  70.368 18.757 70.392 22.501 ;
     RECT  29.28 20.821 31.032 22.739 ;
     RECT  66.48 21.635 67.512 22.739 ;
     RECT  50.304 21.155 51.312 22.741 ;
     RECT  70.368 22.501 70.68 22.741 ;
     RECT  72.432 20.723 74.616 22.741 ;
     RECT  10.896 19.235 10.92 22.789 ;
     RECT  6.72 18.563 6.744 22.835 ;
     RECT  63.84 21.061 63.864 22.835 ;
     RECT  13.2 22.453 14.904 22.883 ;
     RECT  18.6 18.227 19.032 23.029 ;
     RECT  53.952 22.259 55.176 23.123 ;
     RECT  32.592 21.731 33.192 23.267 ;
     RECT  70.368 22.741 71.208 23.315 ;
     RECT  2.256 20.579 5.016 23.411 ;
     RECT  72.288 22.741 74.664 23.411 ;
     RECT  72.432 23.411 74.616 23.459 ;
     RECT  4.176 23.411 5.016 23.509 ;
     RECT  10.896 22.789 11.304 23.555 ;
     RECT  66.96 22.739 67.512 23.603 ;
     RECT  79.68 20.197 79.8 23.701 ;
     RECT  4.176 23.509 5.592 23.795 ;
     RECT  56.4 22.499 56.808 24.181 ;
     RECT  36.672 22.741 36.696 24.371 ;
     RECT  56.304 24.181 56.808 24.371 ;
     RECT  61.8 21.779 62.616 24.373 ;
     RECT  10.896 23.555 10.92 24.469 ;
     RECT  34.8 13.331 35.112 24.469 ;
     RECT  50.304 22.741 52.248 24.563 ;
     RECT  53.952 23.123 53.976 24.563 ;
     RECT  72.6 23.459 74.616 24.563 ;
     RECT  2.256 23.411 3.096 24.659 ;
     RECT  55.152 23.123 55.176 24.853 ;
     RECT  54.72 24.853 55.176 24.899 ;
     RECT  70.56 23.315 71.208 24.901 ;
     RECT  33.168 23.267 33.192 25.045 ;
     RECT  13.2 22.883 13.944 25.093 ;
     RECT  10.752 24.469 10.92 25.139 ;
     RECT  31.008 22.739 31.032 25.139 ;
     RECT  34.464 24.469 35.112 25.139 ;
     RECT  33.168 25.045 33.336 25.141 ;
     RECT  56.4 24.371 56.808 25.141 ;
     RECT  33.168 25.141 33.432 25.187 ;
     RECT  51 24.563 52.248 25.187 ;
     RECT  13.104 25.093 13.944 25.283 ;
     RECT  29.28 22.739 30.024 25.285 ;
     RECT  40.08 18.181 41.112 25.525 ;
     RECT  43.968 25.045 43.992 25.667 ;
     RECT  74.112 24.563 74.616 25.715 ;
     RECT  75.792 20.867 75.816 25.715 ;
     RECT  56.4 25.141 57 25.955 ;
     RECT  29.28 25.285 30.312 26.003 ;
     RECT  27.408 24.469 27.432 26.101 ;
     RECT  27.408 26.101 27.912 26.243 ;
     RECT  33.312 25.187 33.432 26.243 ;
     RECT  40.032 25.525 41.112 26.531 ;
     RECT  51 25.187 51.312 26.629 ;
     RECT  29.28 26.003 30.024 26.771 ;
     RECT  53.568 25.621 53.592 26.771 ;
     RECT  27.888 26.243 27.912 26.819 ;
     RECT  79.68 23.701 80.424 26.819 ;
     RECT  45.36 19.909 46.296 26.915 ;
     RECT  70.128 24.901 71.208 27.059 ;
     RECT  7.8 18.899 8.856 27.061 ;
     RECT  13.2 25.283 13.944 27.061 ;
     RECT  51 26.629 51.432 27.061 ;
     RECT  61.632 24.373 62.616 27.061 ;
     RECT  54.72 24.899 54.744 27.107 ;
     RECT  61.584 27.061 62.616 27.251 ;
     RECT  75.84 26.101 75.864 27.347 ;
     RECT  74.208 25.715 74.616 27.395 ;
     RECT  13.2 27.061 14.136 27.397 ;
     RECT  33.408 26.243 33.432 27.587 ;
     RECT  58.608 22.741 58.632 27.589 ;
     RECT  58.416 27.589 58.632 27.635 ;
     RECT  70.992 27.059 71.208 27.731 ;
     RECT  22.752 20.533 22.776 27.877 ;
     RECT  26.736 27.061 26.76 27.877 ;
     RECT  45.36 26.915 45.912 27.877 ;
     RECT  56.4 25.955 56.712 27.877 ;
     RECT  61.632 27.251 62.616 27.877 ;
     RECT  7.8 27.061 9.432 27.923 ;
     RECT  42.72 26.725 42.744 27.923 ;
     RECT  79.776 26.819 80.424 28.019 ;
     RECT  63.888 25.621 63.912 28.115 ;
     RECT  78 22.499 78.312 28.261 ;
     RECT  81.84 27.877 81.864 28.261 ;
     RECT  81.84 28.261 82.152 28.307 ;
     RECT  56.256 27.877 56.712 28.405 ;
     RECT  61.632 27.877 62.76 28.453 ;
     RECT  45.36 27.877 46.056 28.499 ;
     RECT  36.432 27.733 36.456 28.547 ;
     RECT  50.832 27.061 51.432 28.547 ;
     RECT  10.992 27.781 11.016 28.643 ;
     RECT  12.96 27.397 14.136 28.643 ;
     RECT  68.64 24.085 68.664 28.979 ;
     RECT  7.8 27.923 8.856 28.981 ;
     RECT  13.2 28.643 14.136 28.981 ;
     RECT  56.208 28.405 56.712 28.981 ;
     RECT  67.2 23.603 67.512 28.981 ;
     RECT  61.008 28.453 62.76 29.027 ;
     RECT  34.8 25.139 35.112 29.029 ;
     RECT  13.2 28.981 14.808 29.123 ;
     RECT  38.16 27.205 38.184 29.123 ;
     RECT  61.632 29.027 62.76 29.123 ;
     RECT  74.208 27.395 74.472 29.123 ;
     RECT  47.088 28.981 47.112 29.459 ;
     RECT  78 28.261 78.504 29.555 ;
     RECT  22.656 27.877 22.776 29.605 ;
     RECT  26.736 27.877 27 29.605 ;
     RECT  6.96 28.981 8.856 29.651 ;
     RECT  50.832 28.547 51.312 29.699 ;
     RECT  55.008 28.453 55.032 29.699 ;
     RECT  7.68 29.651 8.856 29.795 ;
     RECT  34.8 29.029 35.208 29.795 ;
     RECT  51 29.699 51.312 29.941 ;
     RECT  76.56 28.213 76.584 30.035 ;
     RECT  69.744 27.349 69.768 30.181 ;
     RECT  18.6 23.029 19.848 30.275 ;
     RECT  40.08 26.531 41.112 30.323 ;
     RECT  42.48 29.029 42.504 30.371 ;
     RECT  42.816 30.469 43.32 30.611 ;
     RECT  65.52 29.749 65.544 30.611 ;
     RECT  24 16.595 24.312 30.661 ;
     RECT  58.416 27.635 58.44 30.661 ;
     RECT  49.392 28.837 49.416 30.757 ;
     RECT  26.736 29.605 27.384 30.803 ;
     RECT  51 29.941 51.576 30.803 ;
     RECT  67.2 28.981 67.608 30.803 ;
     RECT  48.72 30.757 49.416 30.805 ;
     RECT  2.4 24.659 3.096 30.851 ;
     RECT  24 30.661 25.08 30.851 ;
     RECT  69.552 30.181 69.768 30.851 ;
     RECT  58.416 30.661 58.728 30.899 ;
     RECT  78 29.555 78.312 30.901 ;
     RECT  61.632 29.123 62.616 30.949 ;
     RECT  56.208 28.981 57.24 31.093 ;
     RECT  72.6 24.563 72.912 31.093 ;
     RECT  27.36 30.803 27.384 31.379 ;
     RECT  43.296 30.611 43.32 31.379 ;
     RECT  47.808 30.805 49.56 31.379 ;
     RECT  56.208 31.093 57.336 31.379 ;
     RECT  58.416 30.899 58.44 31.379 ;
     RECT  7.8 29.795 8.856 31.523 ;
     RECT  4.176 23.795 5.016 31.669 ;
     RECT  67.2 30.803 67.512 31.861 ;
     RECT  48.72 31.379 49.56 31.907 ;
     RECT  45.6 28.499 46.056 31.909 ;
     RECT  4.176 31.669 5.88 31.955 ;
     RECT  54.288 31.093 54.312 31.955 ;
     RECT  72.6 31.093 73.032 31.955 ;
     RECT  82.128 28.307 82.152 31.955 ;
     RECT  45.024 31.909 46.056 32.051 ;
     RECT  78 30.901 78.456 32.195 ;
     RECT  0.192 24.709 0.216 32.291 ;
     RECT  34.8 29.795 35.112 32.341 ;
     RECT  4.992 31.955 5.88 32.387 ;
     RECT  2.4 30.851 2.712 32.437 ;
     RECT  29.4 26.771 30.024 32.437 ;
     RECT  61.632 30.949 63 32.437 ;
     RECT  22.032 29.605 22.776 32.483 ;
     RECT  61.152 32.437 63 32.531 ;
     RECT  29.28 32.437 30.024 32.579 ;
     RECT  22.032 32.483 22.584 32.723 ;
     RECT  40.2 30.323 41.112 32.725 ;
     RECT  24 30.851 24.504 32.771 ;
     RECT  18.6 30.275 18.912 32.869 ;
     RECT  48.72 31.907 48.744 32.869 ;
     RECT  53.184 32.725 53.208 32.915 ;
     RECT  74.448 29.123 74.472 33.013 ;
     RECT  72.6 31.955 72.912 33.061 ;
     RECT  44.448 32.437 44.472 33.107 ;
     RECT  37.344 32.341 37.368 33.299 ;
     RECT  18.24 32.869 18.912 33.587 ;
     RECT  34.8 32.341 35.352 33.587 ;
     RECT  45.6 32.051 46.056 33.589 ;
     RECT  47.088 32.437 47.112 33.635 ;
     RECT  74.448 33.013 74.712 33.683 ;
     RECT  31.344 33.013 31.368 33.827 ;
     RECT  39.648 32.725 41.112 33.827 ;
     RECT  22.56 32.723 22.584 33.829 ;
     RECT  69.744 30.851 69.768 33.829 ;
     RECT  70.992 27.731 71.016 33.829 ;
     RECT  79.776 28.019 79.8 33.923 ;
     RECT  48.432 32.869 48.744 33.925 ;
     RECT  69.744 33.829 71.016 33.971 ;
     RECT  24 32.771 24.408 34.069 ;
     RECT  47.904 33.925 48.744 34.069 ;
     RECT  29.4 32.579 30.024 34.117 ;
     RECT  56.208 31.379 56.712 34.117 ;
     RECT  61.152 32.531 62.424 34.117 ;
     RECT  7.8 31.523 8.112 34.165 ;
     RECT  13.2 29.123 14.136 34.165 ;
     RECT  27.072 32.773 27.096 34.213 ;
     RECT  2.4 32.437 3.192 34.259 ;
     RECT  72.48 33.061 72.912 34.355 ;
     RECT  81.456 33.493 81.48 34.355 ;
     RECT  74.688 33.683 74.712 34.643 ;
     RECT  7.8 34.165 8.712 34.741 ;
     RECT  61.152 34.117 62.76 34.741 ;
     RECT  60.48 34.741 62.76 34.787 ;
     RECT  63.84 34.549 63.864 34.835 ;
     RECT  67.2 31.861 68.424 34.835 ;
     RECT  78 32.195 78.408 34.885 ;
     RECT  47.904 34.069 49.08 34.979 ;
     RECT  74.496 34.789 74.52 34.979 ;
     RECT  40.2 33.827 41.112 35.221 ;
     RECT  51 30.803 51.312 35.317 ;
     RECT  29.4 34.117 30.888 35.363 ;
     RECT  56.208 34.117 57.48 35.363 ;
     RECT  48 34.979 49.08 35.459 ;
     RECT  78 34.885 78.648 35.843 ;
     RECT  44.88 33.589 46.056 35.939 ;
     RECT  60.48 34.787 60.504 35.939 ;
     RECT  61.632 34.787 62.76 35.939 ;
     RECT  65.904 34.597 65.928 36.085 ;
     RECT  65.568 36.085 65.928 36.131 ;
     RECT  34.8 33.587 35.112 36.229 ;
     RECT  36.432 35.269 36.456 36.373 ;
     RECT  67.2 34.835 67.704 36.373 ;
     RECT  70.992 33.971 71.016 36.373 ;
     RECT  72.6 34.355 72.912 36.373 ;
     RECT  15.936 34.165 15.96 36.421 ;
     RECT  27.072 34.213 27.528 36.421 ;
     RECT  18.48 33.587 18.912 36.515 ;
     RECT  24 34.069 25.176 36.515 ;
     RECT  7.8 34.741 9.672 36.659 ;
     RECT  52.512 36.373 52.536 36.659 ;
     RECT  36.336 36.373 36.456 36.851 ;
     RECT  38.736 34.933 38.76 36.899 ;
     RECT  33.024 36.373 33.048 36.901 ;
     RECT  39.888 35.221 41.112 36.901 ;
     RECT  67.2 36.373 67.944 36.995 ;
     RECT  45.024 35.939 46.056 36.997 ;
     RECT  50.688 35.317 51.312 36.997 ;
     RECT  78 35.843 78.312 36.997 ;
     RECT  79.68 35.317 79.704 36.997 ;
     RECT  36.432 36.851 36.456 37.043 ;
     RECT  65.568 36.131 65.592 37.043 ;
     RECT  21.936 33.829 22.584 37.045 ;
     RECT  32.4 36.901 33.048 37.091 ;
     RECT  48 35.459 48.744 37.091 ;
     RECT  78 36.997 79.704 37.091 ;
     RECT  69.744 33.971 69.768 37.525 ;
     RECT  70.992 36.373 72.912 37.525 ;
     RECT  15.936 36.421 16.344 37.571 ;
     RECT  21.072 37.045 22.584 37.619 ;
     RECT  32.4 37.091 32.952 37.619 ;
     RECT  50.688 36.997 52.248 37.667 ;
     RECT  13.2 34.165 14.184 37.861 ;
     RECT  7.8 36.659 8.712 37.907 ;
     RECT  24 36.515 24.312 38.005 ;
     RECT  34.704 36.229 35.112 38.195 ;
     RECT  69.744 37.525 72.912 38.195 ;
     RECT  78 37.091 79.176 38.195 ;
     RECT  48.72 37.091 48.744 38.197 ;
     RECT  15.936 37.571 15.96 38.581 ;
     RECT  27.072 36.421 27.912 38.675 ;
     RECT  38.832 36.901 41.112 38.675 ;
     RECT  69.744 38.195 71.016 38.675 ;
     RECT  38.832 38.675 38.904 38.723 ;
     RECT  50.688 37.667 51.312 38.725 ;
     RECT  21.072 37.619 21.096 38.915 ;
     RECT  48.48 38.197 48.744 39.109 ;
     RECT  83.28 15.829 83.712 39.109 ;
     RECT  67.2 36.995 67.704 39.203 ;
     RECT  18.6 36.515 18.912 39.301 ;
     RECT  24 38.005 24.6 39.301 ;
     RECT  15.936 38.581 16.488 39.347 ;
     RECT  24 39.301 25.56 39.395 ;
     RECT  74.352 35.173 74.376 39.395 ;
     RECT  48.48 39.109 49.512 39.491 ;
     RECT  61.632 35.939 62.424 39.493 ;
     RECT  70.992 38.675 71.016 39.589 ;
     RECT  72.6 38.195 72.912 39.589 ;
     RECT  34.8 38.195 35.112 39.733 ;
     RECT  27.072 38.675 27.096 39.781 ;
     RECT  64.704 39.445 64.728 39.781 ;
     RECT  64.704 39.781 64.776 39.877 ;
     RECT  38.88 38.723 38.904 39.923 ;
     RECT  53.568 37.573 53.592 39.923 ;
     RECT  81.456 38.149 81.48 39.923 ;
     RECT  12.336 37.861 14.184 39.971 ;
     RECT  64.704 39.877 64.824 39.971 ;
     RECT  17.616 39.301 18.912 40.019 ;
     RECT  50.688 38.725 52.152 40.019 ;
     RECT  78 38.195 78.456 40.019 ;
     RECT  64.752 39.971 64.824 40.355 ;
     RECT  25.536 39.395 25.56 40.499 ;
     RECT  48.72 39.491 49.512 40.499 ;
     RECT  59.952 39.781 59.976 40.499 ;
     RECT  83.136 39.109 83.712 40.499 ;
     RECT  12.336 39.971 13.512 40.547 ;
     RECT  27.072 39.781 27.912 40.547 ;
     RECT  34.512 39.733 35.112 40.547 ;
     RECT  48.72 40.499 48.744 40.547 ;
     RECT  32.4 37.619 32.424 40.595 ;
     RECT  27.312 40.547 27.912 40.643 ;
     RECT  10.368 39.877 10.392 40.835 ;
     RECT  61.536 39.493 62.424 40.931 ;
     RECT  29.4 35.363 30.024 40.933 ;
     RECT  33.696 40.597 33.72 40.979 ;
     RECT  56.208 35.363 56.712 40.981 ;
     RECT  57.888 35.413 57.912 40.981 ;
     RECT  38.016 40.741 38.184 41.027 ;
     RECT  78 40.019 78.312 41.029 ;
     RECT  61.632 40.931 62.424 41.123 ;
     RECT  61.632 41.123 62.28 41.171 ;
     RECT  78 41.029 79.032 41.171 ;
     RECT  54.96 40.405 54.984 41.173 ;
     RECT  64.752 40.355 64.776 41.219 ;
     RECT  40.2 38.675 41.112 41.221 ;
     RECT  69.744 38.675 69.768 41.221 ;
     RECT  70.992 39.589 72.912 41.221 ;
     RECT  34.8 40.547 35.112 41.269 ;
     RECT  54.96 41.173 55.08 41.365 ;
     RECT  69.744 41.221 72.912 41.411 ;
     RECT  29.4 40.933 30.36 41.557 ;
     RECT  31.872 40.981 31.896 41.557 ;
     RECT  4.992 32.387 5.016 41.651 ;
     RECT  29.4 41.557 31.896 41.651 ;
     RECT  20.64 39.301 20.664 41.891 ;
     RECT  38.16 41.027 38.184 41.891 ;
     RECT  6.336 41.605 6.36 41.893 ;
     RECT  7.8 37.907 8.112 41.893 ;
     RECT  15.936 39.347 15.96 41.987 ;
     RECT  12.384 40.547 13.512 41.989 ;
     RECT  26.16 40.981 26.184 42.179 ;
     RECT  39.408 41.221 41.112 42.179 ;
     RECT  48.624 41.029 48.648 42.275 ;
     RECT  69.744 41.411 71.256 42.419 ;
     RECT  72.432 41.411 72.912 42.419 ;
     RECT  52.992 41.221 53.016 42.565 ;
     RECT  74.304 39.829 74.328 42.565 ;
     RECT  52.992 42.565 53.112 42.611 ;
     RECT  24 39.395 24.312 42.661 ;
     RECT  34.8 41.269 35.352 42.709 ;
     RECT  54.816 41.365 55.08 42.709 ;
     RECT  56.208 40.981 57.912 42.709 ;
     RECT  14.832 41.557 14.856 42.755 ;
     RECT  54.816 42.709 57.912 42.755 ;
     RECT  43.728 35.173 43.752 42.757 ;
     RECT  78 41.171 78.312 42.757 ;
     RECT  79.776 41.557 79.8 42.757 ;
     RECT  6.336 41.893 8.232 42.803 ;
     RECT  34.8 42.709 36.072 42.851 ;
     RECT  9.792 42.181 9.816 42.899 ;
     RECT  39.408 42.179 40.512 42.995 ;
     RECT  43.344 42.757 43.752 42.995 ;
     RECT  74.304 42.565 74.856 43.139 ;
     RECT  27.312 40.643 27.336 43.285 ;
     RECT  24 42.661 24.408 43.331 ;
     RECT  53.088 42.611 53.112 43.331 ;
     RECT  65.184 42.325 65.208 43.379 ;
     RECT  44.928 36.997 46.056 43.525 ;
     RECT  47.088 41.365 47.112 43.525 ;
     RECT  60.288 41.509 60.312 43.571 ;
     RECT  40.2 42.995 40.512 43.621 ;
     RECT  4.56 42.709 4.584 43.861 ;
     RECT  4.56 43.861 4.728 43.907 ;
     RECT  18.6 40.019 18.912 43.909 ;
     RECT  22.56 37.619 22.584 43.955 ;
     RECT  34.8 42.851 35.496 43.955 ;
     RECT  78 42.757 79.8 43.955 ;
     RECT  54.816 42.755 56.712 44.003 ;
     RECT  69.744 42.419 69.768 44.003 ;
     RECT  20.544 43.525 20.568 44.051 ;
     RECT  67.2 39.203 67.656 44.099 ;
     RECT  78 43.955 78.312 44.149 ;
     RECT  74.304 43.139 74.328 44.339 ;
     RECT  4.704 43.907 4.728 44.483 ;
     RECT  7.8 42.803 8.232 44.483 ;
     RECT  79.776 43.955 79.8 44.483 ;
     RECT  42.528 43.285 42.552 44.485 ;
     RECT  40.2 43.621 41.064 44.531 ;
     RECT  11.376 42.181 11.4 44.579 ;
     RECT  72.48 42.419 72.912 44.581 ;
     RECT  18.6 43.909 19.512 44.627 ;
     RECT  26.448 43.285 27.336 44.627 ;
     RECT  44.928 43.525 47.112 44.627 ;
     RECT  12.384 41.989 13.608 44.773 ;
     RECT  12 44.773 13.608 44.819 ;
     RECT  77.376 44.149 78.312 44.821 ;
     RECT  51 40.019 51.312 44.869 ;
     RECT  67.2 44.099 67.512 44.869 ;
     RECT  34.8 43.955 35.112 44.965 ;
     RECT  74.688 44.869 74.712 44.965 ;
     RECT  82.272 44.725 82.296 44.965 ;
     RECT  76.416 44.821 78.312 45.011 ;
     RECT  49.008 44.581 49.032 45.013 ;
     RECT  6.336 42.803 6.36 45.059 ;
     RECT  44.928 44.627 46.872 45.059 ;
     RECT  49.008 45.013 49.128 45.155 ;
     RECT  55.056 44.003 56.712 45.155 ;
     RECT  60.768 43.861 60.792 45.157 ;
     RECT  26.784 44.627 27.336 45.203 ;
     RECT  60.72 45.157 60.792 45.349 ;
     RECT  61.8 41.171 62.28 45.349 ;
     RECT  69.84 45.253 69.864 45.397 ;
     RECT  50.88 44.869 51.312 45.491 ;
     RECT  60.72 45.349 62.28 45.493 ;
     RECT  34.464 44.965 35.112 45.539 ;
     RECT  66.72 44.869 67.512 45.539 ;
     RECT  74.688 44.965 75.24 45.539 ;
     RECT  18.6 44.627 18.912 45.541 ;
     RECT  24 43.331 24.312 45.541 ;
     RECT  29.4 41.651 30.984 45.541 ;
     RECT  58.944 43.861 58.968 45.587 ;
     RECT  74.688 45.539 74.856 45.589 ;
     RECT  43.728 42.995 43.752 45.635 ;
     RECT  57.888 42.755 57.912 45.635 ;
     RECT  12 44.819 12.024 45.731 ;
     RECT  80.928 45.013 80.952 45.731 ;
     RECT  44.928 45.059 46.728 45.877 ;
     RECT  44.88 45.877 46.728 46.067 ;
     RECT  22.272 45.685 22.296 46.117 ;
     RECT  77.376 45.011 78.312 46.211 ;
     RECT  14.784 44.965 14.808 46.213 ;
     RECT  66.768 45.539 67.512 46.693 ;
     RECT  5.712 46.069 5.736 46.787 ;
     RECT  29.4 45.541 31.032 46.787 ;
     RECT  33.312 45.493 33.336 46.787 ;
     RECT  63.792 45.733 63.816 46.787 ;
     RECT  24 45.541 24.648 46.835 ;
     RECT  26.784 45.203 26.808 46.837 ;
     RECT  11.376 46.117 11.4 46.883 ;
     RECT  21.84 46.117 22.296 46.883 ;
     RECT  42.096 44.485 42.552 46.931 ;
     RECT  14.784 46.213 15 47.075 ;
     RECT  69.648 45.397 69.864 47.221 ;
     RECT  82.176 44.965 82.296 47.221 ;
     RECT  69.6 47.221 69.864 47.267 ;
     RECT  44.88 46.067 46.056 47.269 ;
     RECT  60.144 45.493 62.28 47.269 ;
     RECT  26.784 46.837 26.904 47.315 ;
     RECT  66.768 46.693 67.608 47.317 ;
     RECT  21.84 46.883 21.912 47.363 ;
     RECT  72.432 44.581 72.912 47.363 ;
     RECT  74.448 45.589 74.856 47.363 ;
     RECT  18.48 45.541 18.912 47.701 ;
     RECT  26.88 47.315 26.904 47.701 ;
     RECT  51 45.491 51.312 47.701 ;
     RECT  55.056 45.155 55.08 47.701 ;
     RECT  82.128 47.221 82.296 47.797 ;
     RECT  56.4 45.155 56.712 47.845 ;
     RECT  78 46.211 78.312 47.845 ;
     RECT  24 46.835 24.456 47.891 ;
     RECT  42.144 46.931 42.552 47.891 ;
     RECT  60.144 47.269 62.376 48.131 ;
     RECT  11.424 47.893 12.072 48.179 ;
     RECT  44.88 47.269 46.152 48.277 ;
     RECT  26.88 47.701 27.432 48.373 ;
     RECT  44.208 48.277 46.152 48.373 ;
     RECT  63.936 47.701 63.96 48.421 ;
     RECT  66.192 47.317 67.608 48.421 ;
     RECT  78 47.845 78.456 48.515 ;
     RECT  82.032 47.797 82.296 48.515 ;
     RECT  63.264 48.421 63.96 48.755 ;
     RECT  42.528 47.891 42.552 48.805 ;
     RECT  43.776 48.373 46.152 48.805 ;
     RECT  66.144 48.421 67.608 48.899 ;
     RECT  2.4 34.259 2.712 48.901 ;
     RECT  9.648 48.133 9.672 48.947 ;
     RECT  36.432 47.845 36.456 48.947 ;
     RECT  40.2 44.531 40.512 48.949 ;
     RECT  43.776 48.805 46.248 48.949 ;
     RECT  74.784 47.363 74.856 48.949 ;
     RECT  54.912 47.701 55.08 48.995 ;
     RECT  13.2 44.819 13.608 48.997 ;
     RECT  18.144 47.701 18.912 48.997 ;
     RECT  60.144 48.131 62.28 48.997 ;
     RECT  2.4 48.901 3.384 49.043 ;
     RECT  82.032 48.515 82.056 49.043 ;
     RECT  83.28 40.499 83.712 49.043 ;
     RECT  43.632 48.949 46.248 49.091 ;
     RECT  42.528 48.805 42.648 49.187 ;
     RECT  34.8 45.539 35.112 49.189 ;
     RECT  51 47.701 51.912 49.235 ;
     RECT  69.6 47.267 69.768 49.237 ;
     RECT  17.664 48.997 18.912 49.283 ;
     RECT  71.232 42.419 71.256 49.333 ;
     RECT  72.48 47.363 72.912 49.333 ;
     RECT  24 47.891 24.312 49.477 ;
     RECT  59.904 48.997 62.28 49.477 ;
     RECT  63.264 48.755 63.288 49.477 ;
     RECT  78 48.515 78.408 49.525 ;
     RECT  40.2 48.949 41.064 49.571 ;
     RECT  59.904 49.477 63.288 49.571 ;
     RECT  12.048 48.179 12.072 49.619 ;
     RECT  13.2 48.997 13.704 49.619 ;
     RECT  66.144 48.899 66.168 49.667 ;
     RECT  60.048 49.571 63.288 49.715 ;
     RECT  42.528 49.187 42.552 49.861 ;
     RECT  74.784 48.949 75.24 49.955 ;
     RECT  26.88 48.373 28.248 50.051 ;
     RECT  43.632 49.091 46.152 50.051 ;
     RECT  18.192 49.283 18.912 50.053 ;
     RECT  33.936 49.189 35.112 50.053 ;
     RECT  18.192 50.053 19.8 50.195 ;
     RECT  43.632 50.051 43.8 50.195 ;
     RECT  64.944 49.381 64.968 50.195 ;
     RECT  60.048 49.715 63.048 50.243 ;
     RECT  4.56 48.997 4.584 50.291 ;
     RECT  60.048 50.243 62.28 50.291 ;
     RECT  29.4 46.787 30.984 50.339 ;
     RECT  77.424 49.525 78.408 50.387 ;
     RECT  71.232 49.333 72.912 50.437 ;
     RECT  32.496 49.525 32.52 50.531 ;
     RECT  61.632 50.291 62.28 50.531 ;
     RECT  69.312 49.237 69.768 50.531 ;
     RECT  30.96 50.339 30.984 50.533 ;
     RECT  24 49.477 25.224 50.579 ;
     RECT  71.232 50.437 73.176 50.579 ;
     RECT  75.216 49.955 75.24 50.579 ;
     RECT  21.888 47.363 21.912 50.627 ;
     RECT  5.904 47.845 5.928 50.677 ;
     RECT  24 50.579 24.312 50.677 ;
     RECT  69.312 50.531 69.336 50.723 ;
     RECT  13.2 49.619 13.608 50.725 ;
     RECT  14.976 47.075 15 50.725 ;
     RECT  37.056 50.581 37.08 50.725 ;
     RECT  33.936 50.053 35.736 50.771 ;
     RECT  36.96 50.725 37.08 50.771 ;
     RECT  18.6 50.195 19.8 50.819 ;
     RECT  13.2 50.725 15 50.965 ;
     RECT  55.056 48.995 55.08 50.965 ;
     RECT  56.4 47.845 57.048 50.965 ;
     RECT  80.352 49.813 80.376 50.965 ;
     RECT  52.944 49.909 52.968 51.059 ;
     RECT  71.232 50.579 72.912 51.107 ;
     RECT  80.352 50.965 80.472 51.157 ;
     RECT  23.904 50.677 24.312 51.203 ;
     RECT  80.352 51.157 80.952 51.203 ;
     RECT  40.2 49.571 40.776 51.299 ;
     RECT  5.808 50.677 5.928 51.347 ;
     RECT  26.88 50.051 26.904 51.347 ;
     RECT  33.936 50.771 35.112 51.347 ;
     RECT  55.056 50.965 57.048 51.347 ;
     RECT  77.52 50.387 78.408 51.347 ;
     RECT  67.2 48.899 67.608 51.349 ;
     RECT  4.272 50.677 4.296 51.395 ;
     RECT  5.808 51.347 5.832 51.395 ;
     RECT  77.712 51.347 78.408 51.445 ;
     RECT  7.8 44.483 8.112 51.541 ;
     RECT  60.048 50.291 60.216 51.587 ;
     RECT  66.672 51.349 67.608 51.637 ;
     RECT  48.96 49.525 48.984 51.733 ;
     RECT  58.752 48.997 58.776 51.827 ;
     RECT  28.224 50.051 28.248 51.877 ;
     RECT  29.4 50.339 29.712 51.877 ;
     RECT  9.408 51.205 9.432 51.923 ;
     RECT  28.224 51.877 29.712 51.923 ;
     RECT  74.064 51.253 74.088 51.923 ;
     RECT  36.96 50.771 36.984 51.971 ;
     RECT  56.016 51.347 57.048 51.971 ;
     RECT  64.752 51.205 64.776 52.067 ;
     RECT  72.432 51.107 72.912 52.163 ;
     RECT  56.4 51.971 57.048 52.259 ;
     RECT  66.672 51.637 67.8 52.261 ;
     RECT  24 51.203 24.312 52.309 ;
     RECT  71.232 51.107 71.256 52.405 ;
     RECT  13.2 50.965 15.288 52.499 ;
     RECT  66.672 52.261 68.136 52.499 ;
     RECT  40.2 51.299 40.512 52.501 ;
     RECT  41.808 49.861 42.552 52.501 ;
     RECT  51 49.235 51.312 52.501 ;
     RECT  17.088 51.541 17.112 52.547 ;
     RECT  21.648 50.725 21.672 52.549 ;
     RECT  21.312 52.549 21.672 52.595 ;
     RECT  11.664 52.165 11.688 52.691 ;
     RECT  55.008 51.637 55.032 52.691 ;
     RECT  27.072 51.781 27.096 52.741 ;
     RECT  40.2 52.501 42.552 52.741 ;
     RECT  40.2 52.741 42.648 52.883 ;
     RECT  41.808 52.883 42.648 52.931 ;
     RECT  7.8 51.541 8.424 52.979 ;
     RECT  44.928 50.051 46.152 53.027 ;
     RECT  67.2 52.499 68.136 53.027 ;
     RECT  77.712 51.445 78.648 53.027 ;
     RECT  82.032 52.357 82.056 53.027 ;
     RECT  58.416 52.981 58.44 53.029 ;
     RECT  30.96 50.533 31.896 53.075 ;
     RECT  41.808 52.931 42.552 53.075 ;
     RECT  60.048 51.587 60.072 53.075 ;
     RECT  26.496 52.741 27.096 53.363 ;
     RECT  48.96 51.733 49.512 53.363 ;
     RECT  18.6 50.819 18.912 53.413 ;
     RECT  29.088 51.923 29.712 53.557 ;
     RECT  50.88 52.501 51.312 53.557 ;
     RECT  56.4 52.259 57 53.557 ;
     RECT  72.6 52.163 72.912 53.557 ;
     RECT  6.096 52.981 6.12 53.699 ;
     RECT  76.368 50.341 76.392 53.843 ;
     RECT  58.32 53.029 58.44 53.939 ;
     RECT  21.312 52.595 21.336 54.083 ;
     RECT  24 52.309 24.84 54.083 ;
     RECT  70.416 52.405 71.256 54.131 ;
     RECT  77.712 53.027 78.312 54.133 ;
     RECT  44.928 53.027 46.056 54.179 ;
     RECT  42.528 53.075 42.552 54.227 ;
     RECT  17.616 53.413 18.912 54.371 ;
     RECT  13.2 52.499 13.512 54.373 ;
     RECT  14.544 52.499 14.568 54.373 ;
     RECT  80.448 51.203 80.952 54.563 ;
     RECT  72.48 53.557 72.912 54.661 ;
     RECT  56.304 53.557 57 54.707 ;
     RECT  70.704 54.131 71.256 54.707 ;
     RECT  34.8 51.347 35.112 54.853 ;
     RECT  13.2 54.373 14.568 54.899 ;
     RECT  26.496 53.363 26.52 54.899 ;
     RECT  56.4 54.707 57 54.899 ;
     RECT  50.736 53.557 51.312 54.995 ;
     RECT  29.088 53.557 30.264 55.187 ;
     RECT  2.4 49.043 2.712 55.237 ;
     RECT  83.4 49.043 83.712 55.237 ;
     RECT  61.8 50.531 62.28 55.331 ;
     RECT  80.928 54.563 80.952 55.331 ;
     RECT  29.28 55.187 30.264 55.475 ;
     RECT  58.32 53.939 58.392 55.477 ;
     RECT  58.32 55.477 58.68 55.523 ;
     RECT  48.96 53.363 48.984 55.621 ;
     RECT  48.672 55.621 48.984 55.667 ;
     RECT  67.2 53.027 67.8 55.669 ;
     RECT  76.944 54.133 78.312 55.669 ;
     RECT  33.84 54.853 35.112 55.715 ;
     RECT  58.368 55.523 58.68 55.715 ;
     RECT  63.36 54.373 63.384 55.715 ;
     RECT  7.8 52.979 8.112 55.813 ;
     RECT  75.744 54.037 75.768 55.859 ;
     RECT  16.128 54.661 16.152 55.907 ;
     RECT  60.048 55.237 60.072 55.907 ;
     RECT  2.4 55.237 2.904 55.909 ;
     RECT  76.944 55.669 78.696 55.955 ;
     RECT  72.24 54.661 72.912 56.243 ;
     RECT  77.232 55.955 78.696 56.341 ;
     RECT  22.944 55.237 22.968 56.387 ;
     RECT  82.656 55.237 83.712 56.483 ;
     RECT  64.944 55.669 64.968 56.531 ;
     RECT  48.672 55.667 48.696 56.629 ;
     RECT  37.872 54.901 37.896 56.723 ;
     RECT  67.2 55.669 67.848 56.917 ;
     RECT  58.656 55.715 58.68 56.965 ;
     RECT  13.2 54.899 14.28 57.059 ;
     RECT  67.2 56.917 67.896 57.059 ;
     RECT  77.232 56.341 79.128 57.059 ;
     RECT  56.4 54.899 56.904 57.061 ;
     RECT  58.128 56.965 58.68 57.061 ;
     RECT  28.08 55.957 28.104 57.107 ;
     RECT  56.4 57.061 58.68 57.107 ;
     RECT  7.8 55.813 8.856 57.157 ;
     RECT  51 54.995 51.312 57.445 ;
     RECT  77.712 57.059 79.128 57.587 ;
     RECT  45.6 54.179 46.056 57.635 ;
     RECT  34.704 55.715 35.112 57.683 ;
     RECT  56.4 57.107 57.816 57.827 ;
     RECT  37.296 56.869 37.848 58.021 ;
     RECT  24 54.083 24.312 58.117 ;
     RECT  51 57.445 52.2 58.117 ;
     RECT  72.6 56.243 72.912 58.117 ;
     RECT  74.064 56.101 74.088 58.117 ;
     RECT  50.688 58.117 52.2 58.163 ;
     RECT  81.504 57.205 81.528 58.163 ;
     RECT  72.6 58.117 74.088 58.355 ;
     RECT  6.864 57.157 8.856 58.403 ;
     RECT  77.712 57.587 78.312 58.499 ;
     RECT  67.2 57.059 67.8 58.501 ;
     RECT  10.224 56.965 10.248 58.549 ;
     RECT  9.936 58.549 10.248 58.645 ;
     RECT  9.936 58.645 11.208 58.691 ;
     RECT  29.28 55.475 29.712 58.691 ;
     RECT  36.384 58.021 37.848 58.691 ;
     RECT  50.688 58.163 51.312 58.691 ;
     RECT  2.4 55.909 3.432 58.739 ;
     RECT  69.888 56.389 69.912 58.739 ;
     RECT  56.4 57.827 56.904 58.741 ;
     RECT  11.184 58.691 11.208 58.787 ;
     RECT  23.376 58.117 24.312 58.931 ;
     RECT  56.304 58.741 56.904 58.931 ;
     RECT  29.4 58.691 29.712 59.173 ;
     RECT  37.296 58.691 37.848 59.173 ;
     RECT  27.936 57.109 27.96 59.221 ;
     RECT  13.2 57.059 14.184 59.267 ;
     RECT  43.632 50.195 43.656 59.267 ;
     RECT  67.2 58.501 67.848 59.267 ;
     RECT  47.952 56.629 48.696 59.315 ;
     RECT  53.616 58.117 53.64 59.315 ;
     RECT  27.264 59.221 27.96 59.459 ;
     RECT  58.56 58.645 58.584 59.459 ;
     RECT  61.8 55.331 62.112 59.461 ;
     RECT  31.968 59.221 31.992 59.603 ;
     RECT  72.6 58.355 73.656 59.699 ;
     RECT  75.84 58.357 75.864 59.699 ;
     RECT  37.296 59.173 38.568 59.747 ;
     RECT  29.4 59.173 29.832 59.749 ;
     RECT  21.648 59.173 21.672 59.891 ;
     RECT  27.264 59.459 27.288 59.891 ;
     RECT  29.28 59.749 29.832 59.891 ;
     RECT  9.936 58.691 9.96 59.987 ;
     RECT  37.584 59.747 38.568 60.323 ;
     RECT  56.4 58.931 56.904 60.373 ;
     RECT  65.472 59.029 65.496 60.419 ;
     RECT  31.872 59.749 31.896 60.661 ;
     RECT  45.6 57.635 45.912 60.661 ;
     RECT  71.232 54.707 71.256 60.661 ;
     RECT  72.6 59.699 72.912 60.661 ;
     RECT  31.344 60.661 31.896 60.707 ;
     RECT  71.232 60.661 72.912 60.707 ;
     RECT  24 58.931 24.312 60.949 ;
     RECT  17.712 54.371 18.912 61.043 ;
     RECT  55.44 60.373 56.904 61.043 ;
     RECT  79.632 58.117 79.656 61.043 ;
     RECT  61.68 59.461 62.112 61.187 ;
     RECT  5.184 60.373 5.208 61.379 ;
     RECT  55.44 61.043 56.712 61.379 ;
     RECT  72.048 60.707 72.912 61.571 ;
     RECT  7.8 58.403 8.856 61.619 ;
     RECT  38.544 60.323 38.568 61.619 ;
     RECT  45.6 60.661 46.152 61.619 ;
     RECT  48.672 59.315 48.696 61.619 ;
     RECT  69.552 60.373 69.576 61.907 ;
     RECT  31.344 60.707 31.368 62.195 ;
     RECT  52.464 60.661 52.488 62.195 ;
     RECT  54.624 61.525 54.648 62.195 ;
     RECT  67.2 59.267 67.8 62.195 ;
     RECT  24 60.949 24.408 62.291 ;
     RECT  27.792 60.421 27.816 62.435 ;
     RECT  36.384 60.997 36.408 62.435 ;
     RECT  43.248 62.581 43.656 62.629 ;
     RECT  2.4 58.739 2.712 62.649 ;
     RECT  7.8 61.619 8.112 62.649 ;
     RECT  13.2 59.267 13.512 62.649 ;
     RECT  18.6 61.043 18.912 62.649 ;
     RECT  24 62.291 24.312 62.649 ;
     RECT  29.4 59.891 29.712 62.649 ;
     RECT  34.8 57.683 35.112 62.649 ;
     RECT  40.2 52.883 40.512 62.649 ;
     RECT  45.6 61.619 45.912 62.649 ;
     RECT  51 58.691 51.312 62.649 ;
     RECT  56.4 61.379 56.712 62.649 ;
     RECT  61.8 61.187 62.112 62.649 ;
     RECT  67.2 62.195 67.512 62.649 ;
     RECT  72.6 61.571 72.912 62.649 ;
     RECT  78 58.499 78.312 62.649 ;
     RECT  83.4 56.483 83.712 62.649 ;
     RECT  2.4 62.649 2.52 62.663 ;
     RECT  7.8 62.649 7.92 62.663 ;
     RECT  13.2 62.649 13.32 62.663 ;
     RECT  18.6 62.649 18.72 62.663 ;
     RECT  24 62.649 24.12 62.663 ;
     RECT  29.4 62.649 29.52 62.663 ;
     RECT  34.8 62.649 34.92 62.663 ;
     RECT  40.2 62.649 40.32 62.663 ;
     RECT  45.6 62.649 45.72 62.663 ;
     RECT  51 62.649 51.12 62.663 ;
     RECT  56.4 62.649 56.52 62.663 ;
     RECT  61.8 62.649 61.92 62.663 ;
     RECT  67.2 62.649 67.32 62.663 ;
     RECT  72.6 62.649 72.72 62.663 ;
     RECT  78 62.649 78.12 62.663 ;
     RECT  83.4 62.649 83.52 62.663 ;
     RECT  43.152 62.629 43.752 62.725 ;
     RECT  43.056 62.725 43.752 63.253 ;
     RECT  42.96 63.253 43.752 63.301 ;
     RECT  42.864 63.301 43.752 63.349 ;
     RECT  42.672 63.349 43.752 64.784 ;
     RECT  51.384 0.037 52.464 0.085 ;
     RECT  52.488 0.037 53.616 2.245 ;
     RECT  53.976 0.517 55.488 2.197 ;
     RECT  74.184 0.517 75.6 3.013 ;
     RECT  67.536 0.611 67.632 0.659 ;
     RECT  67.536 0.659 67.728 1.811 ;
     RECT  55.512 1.717 56.784 2.137 ;
     RECT  70.44 1.763 70.536 2.245 ;
     RECT  18.912 1.811 19.08 3.157 ;
     RECT  67.536 1.811 68.688 2.137 ;
     RECT  67.512 2.137 68.688 2.291 ;
     RECT  72.72 2.137 74.16 2.151 ;
     RECT  72.912 2.151 74.16 2.677 ;
     RECT  54.408 2.197 55.488 2.773 ;
     RECT  58.488 2.245 59.616 2.917 ;
     RECT  70.44 2.245 71.616 2.867 ;
     RECT  76.536 2.245 77.856 2.821 ;
     RECT  67.512 2.291 67.608 2.821 ;
     RECT  8.112 2.533 9.504 2.773 ;
     RECT  73.032 2.677 74.16 6.229 ;
     RECT  3.624 2.725 4.608 2.821 ;
     RECT  6.36 2.725 7.8 2.821 ;
     RECT  6.36 2.821 7.392 3.301 ;
     RECT  29.712 2.821 30.72 4.115 ;
     RECT  66.12 2.821 67.2 3.683 ;
     RECT  76.536 2.821 77.712 3.301 ;
     RECT  45.912 3.059 46.152 3.397 ;
     RECT  45.912 3.397 47.664 4.405 ;
     RECT  66.096 3.683 67.2 4.357 ;
     RECT  80.376 3.733 81.504 4.691 ;
     RECT  78.696 3.925 80.208 4.885 ;
     RECT  66.024 4.357 67.2 4.501 ;
     RECT  45.912 4.405 47.328 4.981 ;
     RECT  66.024 4.501 67.104 5.171 ;
     RECT  80.376 4.691 81.528 5.077 ;
     RECT  78.696 4.885 79.68 5.653 ;
     RECT  35.88 5.029 37.392 5.219 ;
     RECT  80.376 5.077 82.08 5.653 ;
     RECT  82.104 5.077 83.4 5.365 ;
     RECT  66.024 5.171 67.2 5.653 ;
     RECT  37.056 5.219 37.392 5.747 ;
     RECT  60.456 5.509 61.632 5.605 ;
     RECT  66.12 5.653 67.2 7.765 ;
     RECT  80.376 5.653 81.36 5.747 ;
     RECT  2.304 5.747 2.4 6.901 ;
     RECT  37.056 5.747 38.256 6.517 ;
     RECT  67.8 6.229 68.976 6.805 ;
     RECT  37.08 6.517 38.256 6.563 ;
     RECT  20.52 6.709 21.504 6.853 ;
     RECT  20.52 6.995 21.84 8.003 ;
     RECT  75.912 6.995 77.376 9.397 ;
     RECT  68.856 7.139 69 8.341 ;
     RECT  40.512 7.189 41.568 9.011 ;
     RECT  72.912 7.427 73.92 8.437 ;
     RECT  44.52 7.429 45.6 8.339 ;
     RECT  43.728 7.571 44.496 7.861 ;
     RECT  82.056 7.763 83.04 10.307 ;
     RECT  43.32 7.861 44.496 8.339 ;
     RECT  20.52 8.003 21.576 8.437 ;
     RECT  71.304 8.003 72.432 10.499 ;
     RECT  69.384 8.341 70.752 8.389 ;
     RECT  69.72 8.389 70.752 8.723 ;
     RECT  20.52 8.437 21.552 9.635 ;
     RECT  80.376 8.437 81.36 9.155 ;
     RECT  69.72 8.723 71.232 9.059 ;
     RECT  69.384 9.059 71.232 9.683 ;
     RECT  80.328 9.155 81.36 10.885 ;
     RECT  65.928 9.203 67.104 10.355 ;
     RECT  68.376 9.347 69.36 10.883 ;
     RECT  74.808 9.395 75.888 11.413 ;
     RECT  76.296 9.397 77.376 10.213 ;
     RECT  69.384 9.683 71.28 10.213 ;
     RECT  60.504 9.731 61.632 11.459 ;
     RECT  69.72 10.213 71.28 10.981 ;
     RECT  15.336 10.307 16.32 14.005 ;
     RECT  82.056 10.307 83.4 10.693 ;
     RECT  45.912 10.355 47.184 14.099 ;
     RECT  65.928 10.355 67.2 12.997 ;
     RECT  71.304 10.499 72.48 11.845 ;
     RECT  82.248 10.693 83.4 14.867 ;
     RECT  68.376 10.883 69.696 11.363 ;
     RECT  32.76 10.885 34.272 12.469 ;
     RECT  27 11.413 28.512 11.939 ;
     RECT  60.072 11.459 61.632 11.893 ;
     RECT  78.936 11.459 80.016 13.283 ;
     RECT  73.512 11.507 74.592 14.915 ;
     RECT  62.376 11.797 63.84 12.563 ;
     RECT  71.4 11.845 72.48 13.091 ;
     RECT  60.072 11.893 61.584 12.181 ;
     RECT  70.248 11.939 71.232 13.091 ;
     RECT  60.072 12.181 61.44 12.323 ;
     RECT  60.072 12.323 61.584 13.139 ;
     RECT  33.384 12.659 34.8 13.859 ;
     RECT  74.616 12.659 75.6 14.099 ;
     RECT  35.256 12.707 36.024 13.331 ;
     RECT  66.168 12.997 67.2 13.667 ;
     RECT  70.104 13.091 71.232 13.187 ;
     RECT  71.256 13.091 72.48 13.715 ;
     RECT  67.608 13.093 68.688 13.235 ;
     RECT  68.712 13.093 70.08 13.187 ;
     RECT  68.712 13.187 71.232 13.235 ;
     RECT  69.792 13.235 71.232 13.715 ;
     RECT  78.312 13.283 80.016 14.101 ;
     RECT  35.112 13.331 36.024 13.861 ;
     RECT  65.928 13.667 67.2 15.443 ;
     RECT  69.792 13.715 70.104 13.957 ;
     RECT  44.784 13.811 45.36 14.677 ;
     RECT  35.112 13.861 36.288 15.731 ;
     RECT  20.52 13.957 21.936 14.387 ;
     RECT  21.96 13.957 23.04 14.003 ;
     RECT  69.816 13.957 70.104 14.485 ;
     RECT  14.088 14.051 15.168 14.339 ;
     RECT  74.616 14.099 75.84 15.731 ;
     RECT  78.312 14.101 79.776 14.533 ;
     RECT  14.04 14.339 15.168 14.675 ;
     RECT  62.376 14.341 63.888 14.867 ;
     RECT  8.904 14.531 10.032 16.595 ;
     RECT  78.792 14.533 79.776 16.019 ;
     RECT  14.04 14.675 15.216 17.075 ;
     RECT  43.944 14.677 45.36 14.867 ;
     RECT  79.8 14.867 80.784 16.019 ;
     RECT  81.768 14.867 83.4 15.829 ;
     RECT  73.368 14.915 74.592 19.765 ;
     RECT  36.312 15.301 37.728 15.731 ;
     RECT  81.768 15.829 83.28 17.123 ;
     RECT  5.496 16.019 6.48 16.595 ;
     RECT  17.208 16.019 18.24 16.595 ;
     RECT  18.912 16.019 19.032 17.461 ;
     RECT  78.312 16.019 80.88 16.165 ;
     RECT  15.336 16.115 16.32 16.595 ;
     RECT  78.312 16.165 79.68 18.851 ;
     RECT  79.704 16.165 80.88 16.595 ;
     RECT  5.496 16.595 6.72 18.757 ;
     RECT  6.744 16.595 7.8 17.893 ;
     RECT  8.904 16.595 10.224 17.605 ;
     RECT  10.92 16.595 12.096 21.683 ;
     RECT  15.24 16.595 16.32 17.075 ;
     RECT  49.032 16.595 50.304 17.605 ;
     RECT  79.704 16.595 81.744 17.123 ;
     RECT  57.384 17.123 58.512 18.275 ;
     RECT  79.704 17.123 80.904 17.605 ;
     RECT  12.12 17.171 13.104 18.035 ;
     RECT  22.92 17.413 24 17.555 ;
     RECT  30.024 17.413 31.248 19.957 ;
     RECT  76.92 17.603 78 17.747 ;
     RECT  8.904 17.605 10.08 18.899 ;
     RECT  46.728 17.605 47.952 17.699 ;
     RECT  49.08 17.605 50.304 19.475 ;
     RECT  79.704 17.605 80.88 18.181 ;
     RECT  76.824 17.747 78 20.003 ;
     RECT  58.632 17.891 59.352 19.333 ;
     RECT  12.12 18.035 13.2 19.861 ;
     RECT  79.8 18.181 80.88 18.851 ;
     RECT  6.744 18.563 7.8 22.835 ;
     RECT  5.688 18.757 6.72 19.427 ;
     RECT  52.008 18.851 53.28 21.155 ;
     RECT  78.312 18.851 79.776 19.333 ;
     RECT  79.8 18.851 80.856 19.333 ;
     RECT  8.856 18.899 10.08 19.235 ;
     RECT  45.912 18.947 46.296 19.909 ;
     RECT  67.512 19.091 67.608 20.293 ;
     RECT  78.408 19.333 79.776 20.197 ;
     RECT  79.8 19.333 80.832 22.451 ;
     RECT  53.976 19.379 55.056 20.051 ;
     RECT  5.496 19.427 6.72 20.579 ;
     RECT  55.224 19.427 56.4 20.003 ;
     RECT  12.12 19.861 13.104 21.251 ;
     RECT  56.712 19.955 56.808 21.013 ;
     RECT  31.032 20.003 31.272 20.149 ;
     RECT  55.176 20.003 56.4 21.493 ;
     RECT  76.8 20.003 78 20.293 ;
     RECT  53.976 20.051 55.152 20.725 ;
     RECT  31.032 20.149 32.448 21.731 ;
     RECT  78.408 20.197 79.68 20.579 ;
     RECT  74.616 20.293 75.84 20.725 ;
     RECT  75.864 20.293 78 20.867 ;
     RECT  21.672 20.533 22.752 20.675 ;
     RECT  22.776 20.533 24 32.483 ;
     RECT  78.312 20.579 79.68 26.819 ;
     RECT  54.12 20.725 55.152 20.963 ;
     RECT  74.616 20.725 75.792 22.741 ;
     RECT  75.816 20.867 78 21.493 ;
     RECT  53.976 20.963 55.152 21.013 ;
     RECT  53.976 21.013 55.104 22.165 ;
     RECT  62.616 21.061 63.84 22.835 ;
     RECT  12.12 21.251 13.2 21.683 ;
     RECT  55.176 21.493 56.208 22.499 ;
     RECT  75.816 21.493 77.04 22.499 ;
     RECT  10.92 21.683 11.304 22.789 ;
     RECT  79.8 22.451 80.424 23.701 ;
     RECT  55.176 22.499 56.4 24.181 ;
     RECT  30.024 22.739 31.008 25.139 ;
     RECT  71.208 22.741 72.288 23.411 ;
     RECT  74.664 22.741 75.792 23.411 ;
     RECT  53.976 23.123 55.152 24.563 ;
     RECT  3.096 23.411 4.176 30.851 ;
     RECT  71.208 23.411 72.432 23.459 ;
     RECT  74.616 23.411 75.792 25.715 ;
     RECT  71.208 23.459 72.6 27.731 ;
     RECT  67.512 24.085 68.64 28.979 ;
     RECT  55.176 24.181 56.304 24.371 ;
     RECT  55.176 24.371 56.4 24.899 ;
     RECT  33.192 24.469 34.464 25.045 ;
     RECT  53.952 24.563 55.152 24.853 ;
     RECT  72.912 24.563 74.112 25.715 ;
     RECT  53.952 24.853 54.72 25.621 ;
     RECT  68.664 24.901 70.128 27.059 ;
     RECT  33.336 25.045 34.464 25.139 ;
     RECT  43.992 25.045 45.36 25.667 ;
     RECT  30.024 25.139 30.312 25.285 ;
     RECT  33.336 25.139 34.8 25.141 ;
     RECT  33.432 25.141 34.8 27.587 ;
     RECT  51.312 25.187 51.432 26.629 ;
     RECT  53.592 25.621 54.72 26.771 ;
     RECT  62.616 25.621 63.888 27.877 ;
     RECT  72.912 25.715 74.208 29.123 ;
     RECT  74.616 25.715 75.816 26.101 ;
     RECT  27.912 26.101 29.28 26.771 ;
     RECT  74.616 26.101 75.84 27.347 ;
     RECT  27.912 26.771 29.4 26.819 ;
     RECT  78.312 26.819 79.776 28.261 ;
     RECT  45.912 26.915 46.056 27.877 ;
     RECT  68.664 27.059 70.992 27.349 ;
     RECT  61.584 27.251 61.632 28.453 ;
     RECT  68.664 27.349 69.744 28.979 ;
     RECT  69.768 27.349 70.992 33.829 ;
     RECT  35.112 27.733 36.432 28.547 ;
     RECT  62.76 27.877 63.888 28.115 ;
     RECT  80.424 27.877 81.84 28.019 ;
     RECT  81.864 27.877 83.28 28.261 ;
     RECT  76.584 28.213 78 30.035 ;
     RECT  78.504 28.261 79.776 29.555 ;
     RECT  82.152 28.261 83.28 31.955 ;
     RECT  55.032 28.453 56.208 29.699 ;
     RECT  35.112 28.547 35.208 29.029 ;
     RECT  51.312 28.547 51.432 29.941 ;
     RECT  49.416 28.837 50.832 29.699 ;
     RECT  67.512 28.979 67.608 28.981 ;
     RECT  69.552 28.979 69.744 30.181 ;
     RECT  46.056 28.981 47.088 29.459 ;
     RECT  57.24 28.981 58.416 31.093 ;
     RECT  41.112 29.029 42.48 30.371 ;
     RECT  78.312 29.555 79.776 30.901 ;
     RECT  49.416 29.699 51 30.805 ;
     RECT  67.512 30.803 67.608 31.861 ;
     RECT  49.56 30.805 51 31.907 ;
     RECT  2.712 30.851 4.176 31.955 ;
     RECT  69.552 30.851 69.744 31.861 ;
     RECT  78.456 30.901 79.776 32.195 ;
     RECT  57.336 31.093 58.416 31.379 ;
     RECT  73.032 31.093 74.448 31.955 ;
     RECT  47.808 31.379 48.72 32.437 ;
     RECT  68.424 31.861 69.744 34.835 ;
     RECT  2.712 31.955 3.192 32.437 ;
     RECT  45.024 32.051 45.6 32.437 ;
     RECT  78.408 32.195 79.776 33.923 ;
     RECT  44.472 32.437 45.6 33.107 ;
     RECT  46.056 32.437 47.088 33.635 ;
     RECT  47.112 32.437 48.72 32.869 ;
     RECT  22.584 32.483 24 43.955 ;
     RECT  22.032 32.723 22.56 33.829 ;
     RECT  24.408 32.771 24.504 34.069 ;
     RECT  47.112 32.869 48.432 33.635 ;
     RECT  30.024 33.013 31.344 33.827 ;
     RECT  71.016 33.061 72.48 34.355 ;
     RECT  44.88 33.107 45.6 33.589 ;
     RECT  47.904 33.635 48.432 33.925 ;
     RECT  74.496 33.683 74.688 34.643 ;
     RECT  30.024 33.827 30.888 34.117 ;
     RECT  39.648 33.827 40.2 34.933 ;
     RECT  78.408 33.923 79.704 34.885 ;
     RECT  69.768 33.971 70.992 37.525 ;
     RECT  62.76 34.549 63.84 34.835 ;
     RECT  65.928 34.597 67.2 36.131 ;
     RECT  74.496 34.643 74.52 34.789 ;
     RECT  60.504 34.787 61.632 35.939 ;
     RECT  78.648 34.885 79.704 35.317 ;
     RECT  38.76 34.933 40.2 35.221 ;
     RECT  43.752 35.173 44.88 35.939 ;
     RECT  72.912 35.173 74.352 39.395 ;
     RECT  38.76 35.221 39.888 36.899 ;
     RECT  35.112 35.269 36.432 36.373 ;
     RECT  78.648 35.317 79.68 35.843 ;
     RECT  56.712 35.363 57.48 35.413 ;
     RECT  56.712 35.413 57.888 40.981 ;
     RECT  78.312 35.843 79.68 36.997 ;
     RECT  43.752 35.939 45.024 36.997 ;
     RECT  35.112 36.373 36.336 36.851 ;
     RECT  51.312 36.373 52.512 36.659 ;
     RECT  27.912 36.421 29.4 38.675 ;
     RECT  24.312 36.515 24.6 38.005 ;
     RECT  51.312 36.659 52.536 36.997 ;
     RECT  35.112 36.851 36.432 37.043 ;
     RECT  38.832 36.899 39.888 36.901 ;
     RECT  43.752 36.997 44.928 45.635 ;
     RECT  52.248 36.997 52.536 37.573 ;
     RECT  48.48 37.091 48.72 38.197 ;
     RECT  15.96 37.571 16.344 38.581 ;
     RECT  52.248 37.573 53.568 37.667 ;
     RECT  21.096 37.619 22.56 38.915 ;
     RECT  51.312 37.667 53.568 38.725 ;
     RECT  71.016 38.195 72.6 39.589 ;
     RECT  27.096 38.675 29.4 39.781 ;
     RECT  38.904 38.675 40.2 39.923 ;
     RECT  69.768 38.675 70.992 41.221 ;
     RECT  52.152 38.725 53.568 39.923 ;
     RECT  49.512 39.109 50.688 40.019 ;
     RECT  16.488 39.301 17.616 39.347 ;
     RECT  25.56 39.301 27.072 40.499 ;
     RECT  24.312 39.395 25.536 40.499 ;
     RECT  72.912 39.395 74.328 39.829 ;
     RECT  27.912 39.781 29.4 40.643 ;
     RECT  72.912 39.829 74.304 44.339 ;
     RECT  38.88 39.923 40.2 40.741 ;
     RECT  52.152 39.923 53.016 40.019 ;
     RECT  49.512 40.019 51 40.499 ;
     RECT  52.992 40.019 53.016 41.221 ;
     RECT  78.312 40.019 78.456 41.029 ;
     RECT  54.984 40.405 56.208 41.173 ;
     RECT  26.16 40.499 27.072 40.547 ;
     RECT  26.16 40.547 27.312 40.981 ;
     RECT  34.512 40.547 34.8 40.597 ;
     RECT  33.72 40.597 34.8 40.979 ;
     RECT  38.184 40.741 40.2 41.221 ;
     RECT  61.536 40.931 61.632 41.171 ;
     RECT  26.184 40.981 27.312 42.179 ;
     RECT  30.36 40.981 31.872 41.557 ;
     RECT  61.536 41.171 61.8 41.509 ;
     RECT  78.312 41.171 79.032 41.557 ;
     RECT  55.08 41.173 56.208 42.709 ;
     RECT  38.184 41.221 39.408 41.891 ;
     RECT  46.056 41.365 47.088 43.525 ;
     RECT  47.112 41.365 48.624 42.275 ;
     RECT  71.256 41.411 72.432 42.419 ;
     RECT  60.312 41.509 61.8 43.571 ;
     RECT  13.512 41.557 14.832 41.989 ;
     RECT  14.856 41.557 15.936 41.987 ;
     RECT  78.312 41.557 79.776 42.757 ;
     RECT  5.016 41.605 6.336 41.651 ;
     RECT  6.36 41.605 7.8 41.893 ;
     RECT  13.608 41.989 14.832 42.755 ;
     RECT  26.448 42.179 27.312 43.285 ;
     RECT  40.512 42.179 41.112 43.285 ;
     RECT  11.4 42.181 12.384 44.579 ;
     RECT  69.768 42.419 71.232 44.003 ;
     RECT  71.256 42.419 72.48 44.581 ;
     RECT  56.712 42.755 57.888 45.635 ;
     RECT  6.36 42.803 7.8 45.059 ;
     RECT  43.344 42.995 43.728 43.285 ;
     RECT  40.512 43.285 42.528 43.621 ;
     RECT  42.552 43.285 43.728 45.635 ;
     RECT  60.768 43.571 61.8 43.861 ;
     RECT  41.064 43.621 42.528 44.485 ;
     RECT  57.912 43.861 58.944 45.587 ;
     RECT  60.792 43.861 61.8 45.349 ;
     RECT  19.512 43.909 20.544 44.051 ;
     RECT  78.312 43.955 79.776 44.483 ;
     RECT  69.744 44.003 71.232 45.253 ;
     RECT  41.064 44.485 42.096 44.531 ;
     RECT  12 44.579 12.384 44.773 ;
     RECT  71.256 44.581 72.432 47.363 ;
     RECT  82.296 44.725 83.28 48.515 ;
     RECT  12.024 44.819 13.2 45.731 ;
     RECT  13.608 44.965 14.784 47.075 ;
     RECT  75.24 44.965 76.416 45.011 ;
     RECT  80.952 45.013 82.176 45.731 ;
     RECT  55.08 45.155 56.4 50.965 ;
     RECT  69.744 45.253 69.84 45.397 ;
     RECT  69.864 45.253 71.232 47.267 ;
     RECT  33.336 45.493 34.464 45.539 ;
     RECT  58.968 45.493 60.144 45.587 ;
     RECT  33.336 45.539 34.8 46.787 ;
     RECT  44.88 45.635 44.928 45.877 ;
     RECT  82.128 45.731 82.176 47.221 ;
     RECT  62.28 45.733 63.792 46.787 ;
     RECT  46.056 46.067 46.152 47.269 ;
     RECT  62.28 46.787 62.376 47.269 ;
     RECT  13.608 47.075 14.976 48.997 ;
     RECT  69.768 47.267 71.232 50.531 ;
     RECT  71.256 47.363 72.48 49.333 ;
     RECT  35.112 47.845 36.432 48.947 ;
     RECT  42.144 47.891 42.528 48.949 ;
     RECT  12.072 47.893 13.2 49.619 ;
     RECT  62.28 48.131 62.376 48.421 ;
     RECT  28.248 48.373 29.4 51.877 ;
     RECT  42.552 48.373 43.776 48.805 ;
     RECT  62.28 48.421 63.264 49.477 ;
     RECT  82.056 48.515 83.28 49.043 ;
     RECT  42.648 48.805 43.776 48.949 ;
     RECT  66.168 48.899 67.2 49.667 ;
     RECT  35.112 48.947 35.736 50.053 ;
     RECT  41.064 48.949 42.528 49.571 ;
     RECT  42.648 48.949 43.632 49.187 ;
     RECT  3.384 48.997 4.56 49.043 ;
     RECT  4.584 48.997 5.904 50.291 ;
     RECT  13.704 48.997 14.976 49.619 ;
     RECT  58.776 48.997 59.904 49.571 ;
     RECT  42.552 49.187 43.632 52.741 ;
     RECT  64.968 49.381 66.144 49.667 ;
     RECT  30.984 49.525 32.496 50.531 ;
     RECT  32.52 49.525 33.936 50.531 ;
     RECT  40.776 49.571 42.528 49.861 ;
     RECT  58.776 49.571 60.048 51.827 ;
     RECT  13.608 49.619 14.976 50.725 ;
     RECT  40.776 49.861 41.808 51.299 ;
     RECT  26.904 50.051 28.224 51.347 ;
     RECT  43.8 50.051 44.928 50.195 ;
     RECT  18.192 50.195 18.6 51.541 ;
     RECT  43.656 50.195 44.928 54.179 ;
     RECT  4.56 50.291 5.904 50.677 ;
     RECT  60.216 50.291 61.632 50.531 ;
     RECT  29.712 50.339 30.96 53.075 ;
     RECT  75.24 50.341 76.368 50.579 ;
     RECT  76.392 50.341 77.424 50.387 ;
     RECT  76.392 50.387 77.52 51.347 ;
     RECT  30.984 50.531 31.896 50.533 ;
     RECT  72.912 50.579 73.176 51.253 ;
     RECT  35.736 50.581 37.056 50.725 ;
     RECT  4.296 50.677 5.808 51.395 ;
     RECT  35.736 50.725 36.96 50.771 ;
     RECT  71.256 51.107 72.432 52.163 ;
     RECT  8.112 51.205 9.408 51.541 ;
     RECT  72.912 51.253 74.064 51.923 ;
     RECT  40.512 51.299 41.808 52.501 ;
     RECT  26.88 51.347 28.224 51.781 ;
     RECT  55.056 51.347 56.016 51.637 ;
     RECT  76.392 51.347 77.712 53.843 ;
     RECT  8.424 51.541 9.408 51.923 ;
     RECT  17.112 51.541 18.6 52.547 ;
     RECT  55.032 51.637 56.016 51.971 ;
     RECT  49.512 51.733 51 52.501 ;
     RECT  26.88 51.781 27.072 52.741 ;
     RECT  27.096 51.781 28.224 51.923 ;
     RECT  55.032 51.971 56.4 52.691 ;
     RECT  71.256 52.163 72.6 53.557 ;
     RECT  11.688 52.165 13.2 52.691 ;
     RECT  57 52.259 57.048 52.981 ;
     RECT  80.952 52.357 82.032 53.027 ;
     RECT  82.056 52.357 83.4 53.027 ;
     RECT  13.512 52.499 14.544 54.373 ;
     RECT  49.512 52.501 50.88 53.363 ;
     RECT  17.616 52.547 18.6 53.413 ;
     RECT  56.304 52.691 56.4 53.557 ;
     RECT  42.648 52.741 43.632 52.931 ;
     RECT  40.512 52.883 41.808 53.075 ;
     RECT  42.552 52.931 43.632 54.227 ;
     RECT  57 52.981 58.416 53.029 ;
     RECT  57 53.029 58.32 54.899 ;
     RECT  29.712 53.075 30.264 53.557 ;
     RECT  50.736 53.363 50.88 53.557 ;
     RECT  71.256 53.557 72.48 54.661 ;
     RECT  76.368 53.843 77.712 54.037 ;
     RECT  75.768 54.037 77.712 54.133 ;
     RECT  75.768 54.133 76.944 55.859 ;
     RECT  62.28 54.373 63.36 55.331 ;
     RECT  71.256 54.661 72.24 56.243 ;
     RECT  56.904 54.899 58.32 55.523 ;
     RECT  29.088 55.187 29.28 55.957 ;
     RECT  22.968 55.237 24 56.387 ;
     RECT  62.112 55.331 63.36 55.715 ;
     RECT  58.68 55.477 60.048 55.907 ;
     RECT  56.904 55.523 58.368 55.715 ;
     RECT  56.904 55.715 58.656 56.965 ;
     RECT  28.104 55.957 29.28 57.107 ;
     RECT  72.912 56.101 74.064 58.117 ;
     RECT  71.256 56.243 72.6 60.661 ;
     RECT  69.912 56.389 71.232 58.739 ;
     RECT  8.856 56.965 10.224 58.549 ;
     RECT  56.904 56.965 58.128 57.061 ;
     RECT  67.8 57.059 67.848 58.501 ;
     RECT  28.08 57.107 29.28 57.109 ;
     RECT  27.96 57.109 29.28 58.691 ;
     RECT  78.312 57.587 79.128 58.117 ;
     RECT  35.112 58.021 36.384 58.691 ;
     RECT  52.2 58.117 53.616 58.163 ;
     RECT  78.312 58.117 79.632 61.043 ;
     RECT  8.856 58.549 9.936 59.987 ;
     RECT  9.96 58.691 11.184 58.787 ;
     RECT  27.96 58.691 29.4 59.459 ;
     RECT  56.304 58.931 56.4 60.373 ;
     RECT  27.288 59.459 29.4 59.749 ;
     RECT  27.288 59.749 29.28 59.891 ;
     RECT  27.792 59.891 27.816 60.421 ;
     RECT  51.312 60.661 52.464 62.195 ;
     RECT  35.112 60.997 36.384 62.435 ;
  END
END ot_hgi_idx_ix2_kp
END LIBRARY
